# Generated by FakeRAM 2.0
VERSION 5.7 ;
BUSBITCHARS "[]" ;
PROPERTYDEFINITIONS
  MACRO width INTEGER ;
  MACRO depth INTEGER ;
  MACRO banks INTEGER ;
END PROPERTYDEFINITIONS
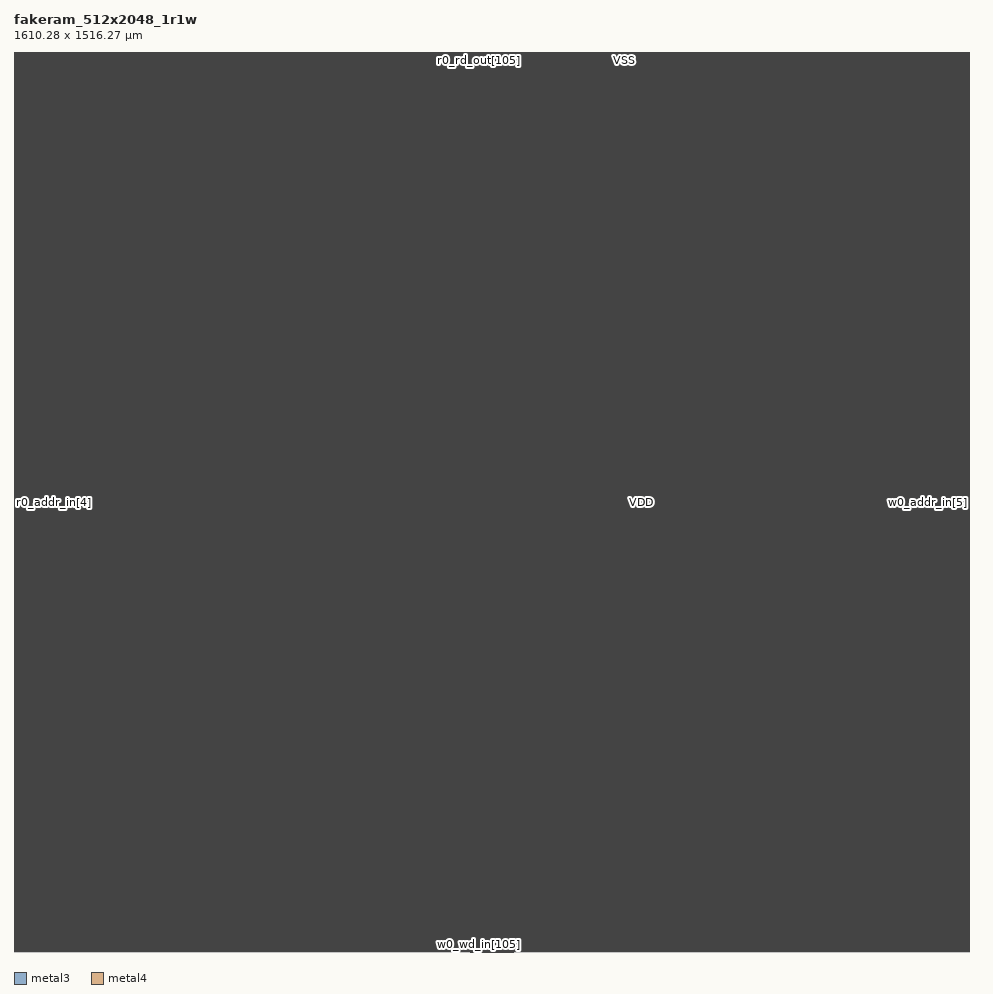
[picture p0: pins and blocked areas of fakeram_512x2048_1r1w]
MACRO fakeram_512x2048_1r1w
  PROPERTY width 512 ;
  PROPERTY depth 2048 ;
  PROPERTY banks 1 ;
  FOREIGN fakeram_512x2048_1r1w 0 0 ;
  SYMMETRY X Y R90 ;
  SIZE 1610.280 BY 1516.270 ;
  CLASS BLOCK ;
  PIN r0_addr_in[0]
    DIRECTION INPUT ;
    USE SIGNAL ;
    SHAPE ABUTMENT ;
    PORT
      LAYER metal3 ;
      RECT 0.000 757.260 0.070 757.330 ;
    END
  END r0_addr_in[0]
  PIN r0_addr_in[1]
    DIRECTION INPUT ;
    USE SIGNAL ;
    SHAPE ABUTMENT ;
    PORT
      LAYER metal3 ;
      RECT 0.000 757.400 0.070 757.470 ;
    END
  END r0_addr_in[1]
  PIN r0_addr_in[2]
    DIRECTION INPUT ;
    USE SIGNAL ;
    SHAPE ABUTMENT ;
    PORT
      LAYER metal3 ;
      RECT 0.000 757.540 0.070 757.610 ;
    END
  END r0_addr_in[2]
  PIN r0_addr_in[3]
    DIRECTION INPUT ;
    USE SIGNAL ;
    SHAPE ABUTMENT ;
    PORT
      LAYER metal3 ;
      RECT 0.000 757.680 0.070 757.750 ;
    END
  END r0_addr_in[3]
  PIN r0_addr_in[4]
    DIRECTION INPUT ;
    USE SIGNAL ;
    SHAPE ABUTMENT ;
    PORT
      LAYER metal3 ;
      RECT 0.000 757.820 0.070 757.890 ;
    END
  END r0_addr_in[4]
  PIN r0_addr_in[5]
    DIRECTION INPUT ;
    USE SIGNAL ;
    SHAPE ABUTMENT ;
    PORT
      LAYER metal3 ;
      RECT 0.000 757.960 0.070 758.030 ;
    END
  END r0_addr_in[5]
  PIN r0_addr_in[6]
    DIRECTION INPUT ;
    USE SIGNAL ;
    SHAPE ABUTMENT ;
    PORT
      LAYER metal3 ;
      RECT 0.000 758.100 0.070 758.170 ;
    END
  END r0_addr_in[6]
  PIN r0_addr_in[7]
    DIRECTION INPUT ;
    USE SIGNAL ;
    SHAPE ABUTMENT ;
    PORT
      LAYER metal3 ;
      RECT 0.000 758.240 0.070 758.310 ;
    END
  END r0_addr_in[7]
  PIN r0_addr_in[8]
    DIRECTION INPUT ;
    USE SIGNAL ;
    SHAPE ABUTMENT ;
    PORT
      LAYER metal3 ;
      RECT 0.000 758.380 0.070 758.450 ;
    END
  END r0_addr_in[8]
  PIN r0_addr_in[9]
    DIRECTION INPUT ;
    USE SIGNAL ;
    SHAPE ABUTMENT ;
    PORT
      LAYER metal3 ;
      RECT 0.000 758.520 0.070 758.590 ;
    END
  END r0_addr_in[9]
  PIN r0_addr_in[10]
    DIRECTION INPUT ;
    USE SIGNAL ;
    SHAPE ABUTMENT ;
    PORT
      LAYER metal3 ;
      RECT 0.000 758.660 0.070 758.730 ;
    END
  END r0_addr_in[10]
  PIN r0_ce_in
    DIRECTION INPUT ;
    USE SIGNAL ;
    SHAPE ABUTMENT ;
    PORT
      LAYER metal3 ;
      RECT 0.000 758.940 0.070 759.010 ;
    END
  END r0_ce_in
  PIN r0_clk
    DIRECTION INPUT ;
    USE SIGNAL ;
    SHAPE ABUTMENT ;
    PORT
      LAYER metal3 ;
      RECT 0.000 759.080 0.070 759.150 ;
    END
  END r0_clk
  PIN r0_rd_out[0]
    DIRECTION OUTPUT ;
    USE SIGNAL ;
    SHAPE ABUTMENT ;
    PORT
      LAYER metal3 ;
      RECT 769.125 1516.200 769.195 1516.270 ;
    END
  END r0_rd_out[0]
  PIN r0_rd_out[1]
    DIRECTION OUTPUT ;
    USE SIGNAL ;
    SHAPE ABUTMENT ;
    PORT
      LAYER metal3 ;
      RECT 769.265 1516.200 769.335 1516.270 ;
    END
  END r0_rd_out[1]
  PIN r0_rd_out[2]
    DIRECTION OUTPUT ;
    USE SIGNAL ;
    SHAPE ABUTMENT ;
    PORT
      LAYER metal3 ;
      RECT 769.405 1516.200 769.475 1516.270 ;
    END
  END r0_rd_out[2]
  PIN r0_rd_out[3]
    DIRECTION OUTPUT ;
    USE SIGNAL ;
    SHAPE ABUTMENT ;
    PORT
      LAYER metal3 ;
      RECT 769.545 1516.200 769.615 1516.270 ;
    END
  END r0_rd_out[3]
  PIN r0_rd_out[4]
    DIRECTION OUTPUT ;
    USE SIGNAL ;
    SHAPE ABUTMENT ;
    PORT
      LAYER metal3 ;
      RECT 769.685 1516.200 769.755 1516.270 ;
    END
  END r0_rd_out[4]
  PIN r0_rd_out[5]
    DIRECTION OUTPUT ;
    USE SIGNAL ;
    SHAPE ABUTMENT ;
    PORT
      LAYER metal3 ;
      RECT 769.825 1516.200 769.895 1516.270 ;
    END
  END r0_rd_out[5]
  PIN r0_rd_out[6]
    DIRECTION OUTPUT ;
    USE SIGNAL ;
    SHAPE ABUTMENT ;
    PORT
      LAYER metal3 ;
      RECT 769.965 1516.200 770.035 1516.270 ;
    END
  END r0_rd_out[6]
  PIN r0_rd_out[7]
    DIRECTION OUTPUT ;
    USE SIGNAL ;
    SHAPE ABUTMENT ;
    PORT
      LAYER metal3 ;
      RECT 770.105 1516.200 770.175 1516.270 ;
    END
  END r0_rd_out[7]
  PIN r0_rd_out[8]
    DIRECTION OUTPUT ;
    USE SIGNAL ;
    SHAPE ABUTMENT ;
    PORT
      LAYER metal3 ;
      RECT 770.245 1516.200 770.315 1516.270 ;
    END
  END r0_rd_out[8]
  PIN r0_rd_out[9]
    DIRECTION OUTPUT ;
    USE SIGNAL ;
    SHAPE ABUTMENT ;
    PORT
      LAYER metal3 ;
      RECT 770.385 1516.200 770.455 1516.270 ;
    END
  END r0_rd_out[9]
  PIN r0_rd_out[10]
    DIRECTION OUTPUT ;
    USE SIGNAL ;
    SHAPE ABUTMENT ;
    PORT
      LAYER metal3 ;
      RECT 770.525 1516.200 770.595 1516.270 ;
    END
  END r0_rd_out[10]
  PIN r0_rd_out[11]
    DIRECTION OUTPUT ;
    USE SIGNAL ;
    SHAPE ABUTMENT ;
    PORT
      LAYER metal3 ;
      RECT 770.665 1516.200 770.735 1516.270 ;
    END
  END r0_rd_out[11]
  PIN r0_rd_out[12]
    DIRECTION OUTPUT ;
    USE SIGNAL ;
    SHAPE ABUTMENT ;
    PORT
      LAYER metal3 ;
      RECT 770.805 1516.200 770.875 1516.270 ;
    END
  END r0_rd_out[12]
  PIN r0_rd_out[13]
    DIRECTION OUTPUT ;
    USE SIGNAL ;
    SHAPE ABUTMENT ;
    PORT
      LAYER metal3 ;
      RECT 770.945 1516.200 771.015 1516.270 ;
    END
  END r0_rd_out[13]
  PIN r0_rd_out[14]
    DIRECTION OUTPUT ;
    USE SIGNAL ;
    SHAPE ABUTMENT ;
    PORT
      LAYER metal3 ;
      RECT 771.085 1516.200 771.155 1516.270 ;
    END
  END r0_rd_out[14]
  PIN r0_rd_out[15]
    DIRECTION OUTPUT ;
    USE SIGNAL ;
    SHAPE ABUTMENT ;
    PORT
      LAYER metal3 ;
      RECT 771.225 1516.200 771.295 1516.270 ;
    END
  END r0_rd_out[15]
  PIN r0_rd_out[16]
    DIRECTION OUTPUT ;
    USE SIGNAL ;
    SHAPE ABUTMENT ;
    PORT
      LAYER metal3 ;
      RECT 771.365 1516.200 771.435 1516.270 ;
    END
  END r0_rd_out[16]
  PIN r0_rd_out[17]
    DIRECTION OUTPUT ;
    USE SIGNAL ;
    SHAPE ABUTMENT ;
    PORT
      LAYER metal3 ;
      RECT 771.505 1516.200 771.575 1516.270 ;
    END
  END r0_rd_out[17]
  PIN r0_rd_out[18]
    DIRECTION OUTPUT ;
    USE SIGNAL ;
    SHAPE ABUTMENT ;
    PORT
      LAYER metal3 ;
      RECT 771.645 1516.200 771.715 1516.270 ;
    END
  END r0_rd_out[18]
  PIN r0_rd_out[19]
    DIRECTION OUTPUT ;
    USE SIGNAL ;
    SHAPE ABUTMENT ;
    PORT
      LAYER metal3 ;
      RECT 771.785 1516.200 771.855 1516.270 ;
    END
  END r0_rd_out[19]
  PIN r0_rd_out[20]
    DIRECTION OUTPUT ;
    USE SIGNAL ;
    SHAPE ABUTMENT ;
    PORT
      LAYER metal3 ;
      RECT 771.925 1516.200 771.995 1516.270 ;
    END
  END r0_rd_out[20]
  PIN r0_rd_out[21]
    DIRECTION OUTPUT ;
    USE SIGNAL ;
    SHAPE ABUTMENT ;
    PORT
      LAYER metal3 ;
      RECT 772.065 1516.200 772.135 1516.270 ;
    END
  END r0_rd_out[21]
  PIN r0_rd_out[22]
    DIRECTION OUTPUT ;
    USE SIGNAL ;
    SHAPE ABUTMENT ;
    PORT
      LAYER metal3 ;
      RECT 772.205 1516.200 772.275 1516.270 ;
    END
  END r0_rd_out[22]
  PIN r0_rd_out[23]
    DIRECTION OUTPUT ;
    USE SIGNAL ;
    SHAPE ABUTMENT ;
    PORT
      LAYER metal3 ;
      RECT 772.345 1516.200 772.415 1516.270 ;
    END
  END r0_rd_out[23]
  PIN r0_rd_out[24]
    DIRECTION OUTPUT ;
    USE SIGNAL ;
    SHAPE ABUTMENT ;
    PORT
      LAYER metal3 ;
      RECT 772.485 1516.200 772.555 1516.270 ;
    END
  END r0_rd_out[24]
  PIN r0_rd_out[25]
    DIRECTION OUTPUT ;
    USE SIGNAL ;
    SHAPE ABUTMENT ;
    PORT
      LAYER metal3 ;
      RECT 772.625 1516.200 772.695 1516.270 ;
    END
  END r0_rd_out[25]
  PIN r0_rd_out[26]
    DIRECTION OUTPUT ;
    USE SIGNAL ;
    SHAPE ABUTMENT ;
    PORT
      LAYER metal3 ;
      RECT 772.765 1516.200 772.835 1516.270 ;
    END
  END r0_rd_out[26]
  PIN r0_rd_out[27]
    DIRECTION OUTPUT ;
    USE SIGNAL ;
    SHAPE ABUTMENT ;
    PORT
      LAYER metal3 ;
      RECT 772.905 1516.200 772.975 1516.270 ;
    END
  END r0_rd_out[27]
  PIN r0_rd_out[28]
    DIRECTION OUTPUT ;
    USE SIGNAL ;
    SHAPE ABUTMENT ;
    PORT
      LAYER metal3 ;
      RECT 773.045 1516.200 773.115 1516.270 ;
    END
  END r0_rd_out[28]
  PIN r0_rd_out[29]
    DIRECTION OUTPUT ;
    USE SIGNAL ;
    SHAPE ABUTMENT ;
    PORT
      LAYER metal3 ;
      RECT 773.185 1516.200 773.255 1516.270 ;
    END
  END r0_rd_out[29]
  PIN r0_rd_out[30]
    DIRECTION OUTPUT ;
    USE SIGNAL ;
    SHAPE ABUTMENT ;
    PORT
      LAYER metal3 ;
      RECT 773.325 1516.200 773.395 1516.270 ;
    END
  END r0_rd_out[30]
  PIN r0_rd_out[31]
    DIRECTION OUTPUT ;
    USE SIGNAL ;
    SHAPE ABUTMENT ;
    PORT
      LAYER metal3 ;
      RECT 773.465 1516.200 773.535 1516.270 ;
    END
  END r0_rd_out[31]
  PIN r0_rd_out[32]
    DIRECTION OUTPUT ;
    USE SIGNAL ;
    SHAPE ABUTMENT ;
    PORT
      LAYER metal3 ;
      RECT 773.605 1516.200 773.675 1516.270 ;
    END
  END r0_rd_out[32]
  PIN r0_rd_out[33]
    DIRECTION OUTPUT ;
    USE SIGNAL ;
    SHAPE ABUTMENT ;
    PORT
      LAYER metal3 ;
      RECT 773.745 1516.200 773.815 1516.270 ;
    END
  END r0_rd_out[33]
  PIN r0_rd_out[34]
    DIRECTION OUTPUT ;
    USE SIGNAL ;
    SHAPE ABUTMENT ;
    PORT
      LAYER metal3 ;
      RECT 773.885 1516.200 773.955 1516.270 ;
    END
  END r0_rd_out[34]
  PIN r0_rd_out[35]
    DIRECTION OUTPUT ;
    USE SIGNAL ;
    SHAPE ABUTMENT ;
    PORT
      LAYER metal3 ;
      RECT 774.025 1516.200 774.095 1516.270 ;
    END
  END r0_rd_out[35]
  PIN r0_rd_out[36]
    DIRECTION OUTPUT ;
    USE SIGNAL ;
    SHAPE ABUTMENT ;
    PORT
      LAYER metal3 ;
      RECT 774.165 1516.200 774.235 1516.270 ;
    END
  END r0_rd_out[36]
  PIN r0_rd_out[37]
    DIRECTION OUTPUT ;
    USE SIGNAL ;
    SHAPE ABUTMENT ;
    PORT
      LAYER metal3 ;
      RECT 774.305 1516.200 774.375 1516.270 ;
    END
  END r0_rd_out[37]
  PIN r0_rd_out[38]
    DIRECTION OUTPUT ;
    USE SIGNAL ;
    SHAPE ABUTMENT ;
    PORT
      LAYER metal3 ;
      RECT 774.445 1516.200 774.515 1516.270 ;
    END
  END r0_rd_out[38]
  PIN r0_rd_out[39]
    DIRECTION OUTPUT ;
    USE SIGNAL ;
    SHAPE ABUTMENT ;
    PORT
      LAYER metal3 ;
      RECT 774.585 1516.200 774.655 1516.270 ;
    END
  END r0_rd_out[39]
  PIN r0_rd_out[40]
    DIRECTION OUTPUT ;
    USE SIGNAL ;
    SHAPE ABUTMENT ;
    PORT
      LAYER metal3 ;
      RECT 774.725 1516.200 774.795 1516.270 ;
    END
  END r0_rd_out[40]
  PIN r0_rd_out[41]
    DIRECTION OUTPUT ;
    USE SIGNAL ;
    SHAPE ABUTMENT ;
    PORT
      LAYER metal3 ;
      RECT 774.865 1516.200 774.935 1516.270 ;
    END
  END r0_rd_out[41]
  PIN r0_rd_out[42]
    DIRECTION OUTPUT ;
    USE SIGNAL ;
    SHAPE ABUTMENT ;
    PORT
      LAYER metal3 ;
      RECT 775.005 1516.200 775.075 1516.270 ;
    END
  END r0_rd_out[42]
  PIN r0_rd_out[43]
    DIRECTION OUTPUT ;
    USE SIGNAL ;
    SHAPE ABUTMENT ;
    PORT
      LAYER metal3 ;
      RECT 775.145 1516.200 775.215 1516.270 ;
    END
  END r0_rd_out[43]
  PIN r0_rd_out[44]
    DIRECTION OUTPUT ;
    USE SIGNAL ;
    SHAPE ABUTMENT ;
    PORT
      LAYER metal3 ;
      RECT 775.285 1516.200 775.355 1516.270 ;
    END
  END r0_rd_out[44]
  PIN r0_rd_out[45]
    DIRECTION OUTPUT ;
    USE SIGNAL ;
    SHAPE ABUTMENT ;
    PORT
      LAYER metal3 ;
      RECT 775.425 1516.200 775.495 1516.270 ;
    END
  END r0_rd_out[45]
  PIN r0_rd_out[46]
    DIRECTION OUTPUT ;
    USE SIGNAL ;
    SHAPE ABUTMENT ;
    PORT
      LAYER metal3 ;
      RECT 775.565 1516.200 775.635 1516.270 ;
    END
  END r0_rd_out[46]
  PIN r0_rd_out[47]
    DIRECTION OUTPUT ;
    USE SIGNAL ;
    SHAPE ABUTMENT ;
    PORT
      LAYER metal3 ;
      RECT 775.705 1516.200 775.775 1516.270 ;
    END
  END r0_rd_out[47]
  PIN r0_rd_out[48]
    DIRECTION OUTPUT ;
    USE SIGNAL ;
    SHAPE ABUTMENT ;
    PORT
      LAYER metal3 ;
      RECT 775.845 1516.200 775.915 1516.270 ;
    END
  END r0_rd_out[48]
  PIN r0_rd_out[49]
    DIRECTION OUTPUT ;
    USE SIGNAL ;
    SHAPE ABUTMENT ;
    PORT
      LAYER metal3 ;
      RECT 775.985 1516.200 776.055 1516.270 ;
    END
  END r0_rd_out[49]
  PIN r0_rd_out[50]
    DIRECTION OUTPUT ;
    USE SIGNAL ;
    SHAPE ABUTMENT ;
    PORT
      LAYER metal3 ;
      RECT 776.125 1516.200 776.195 1516.270 ;
    END
  END r0_rd_out[50]
  PIN r0_rd_out[51]
    DIRECTION OUTPUT ;
    USE SIGNAL ;
    SHAPE ABUTMENT ;
    PORT
      LAYER metal3 ;
      RECT 776.265 1516.200 776.335 1516.270 ;
    END
  END r0_rd_out[51]
  PIN r0_rd_out[52]
    DIRECTION OUTPUT ;
    USE SIGNAL ;
    SHAPE ABUTMENT ;
    PORT
      LAYER metal3 ;
      RECT 776.405 1516.200 776.475 1516.270 ;
    END
  END r0_rd_out[52]
  PIN r0_rd_out[53]
    DIRECTION OUTPUT ;
    USE SIGNAL ;
    SHAPE ABUTMENT ;
    PORT
      LAYER metal3 ;
      RECT 776.545 1516.200 776.615 1516.270 ;
    END
  END r0_rd_out[53]
  PIN r0_rd_out[54]
    DIRECTION OUTPUT ;
    USE SIGNAL ;
    SHAPE ABUTMENT ;
    PORT
      LAYER metal3 ;
      RECT 776.685 1516.200 776.755 1516.270 ;
    END
  END r0_rd_out[54]
  PIN r0_rd_out[55]
    DIRECTION OUTPUT ;
    USE SIGNAL ;
    SHAPE ABUTMENT ;
    PORT
      LAYER metal3 ;
      RECT 776.825 1516.200 776.895 1516.270 ;
    END
  END r0_rd_out[55]
  PIN r0_rd_out[56]
    DIRECTION OUTPUT ;
    USE SIGNAL ;
    SHAPE ABUTMENT ;
    PORT
      LAYER metal3 ;
      RECT 776.965 1516.200 777.035 1516.270 ;
    END
  END r0_rd_out[56]
  PIN r0_rd_out[57]
    DIRECTION OUTPUT ;
    USE SIGNAL ;
    SHAPE ABUTMENT ;
    PORT
      LAYER metal3 ;
      RECT 777.105 1516.200 777.175 1516.270 ;
    END
  END r0_rd_out[57]
  PIN r0_rd_out[58]
    DIRECTION OUTPUT ;
    USE SIGNAL ;
    SHAPE ABUTMENT ;
    PORT
      LAYER metal3 ;
      RECT 777.245 1516.200 777.315 1516.270 ;
    END
  END r0_rd_out[58]
  PIN r0_rd_out[59]
    DIRECTION OUTPUT ;
    USE SIGNAL ;
    SHAPE ABUTMENT ;
    PORT
      LAYER metal3 ;
      RECT 777.385 1516.200 777.455 1516.270 ;
    END
  END r0_rd_out[59]
  PIN r0_rd_out[60]
    DIRECTION OUTPUT ;
    USE SIGNAL ;
    SHAPE ABUTMENT ;
    PORT
      LAYER metal3 ;
      RECT 777.525 1516.200 777.595 1516.270 ;
    END
  END r0_rd_out[60]
  PIN r0_rd_out[61]
    DIRECTION OUTPUT ;
    USE SIGNAL ;
    SHAPE ABUTMENT ;
    PORT
      LAYER metal3 ;
      RECT 777.665 1516.200 777.735 1516.270 ;
    END
  END r0_rd_out[61]
  PIN r0_rd_out[62]
    DIRECTION OUTPUT ;
    USE SIGNAL ;
    SHAPE ABUTMENT ;
    PORT
      LAYER metal3 ;
      RECT 777.805 1516.200 777.875 1516.270 ;
    END
  END r0_rd_out[62]
  PIN r0_rd_out[63]
    DIRECTION OUTPUT ;
    USE SIGNAL ;
    SHAPE ABUTMENT ;
    PORT
      LAYER metal3 ;
      RECT 777.945 1516.200 778.015 1516.270 ;
    END
  END r0_rd_out[63]
  PIN r0_rd_out[64]
    DIRECTION OUTPUT ;
    USE SIGNAL ;
    SHAPE ABUTMENT ;
    PORT
      LAYER metal3 ;
      RECT 778.085 1516.200 778.155 1516.270 ;
    END
  END r0_rd_out[64]
  PIN r0_rd_out[65]
    DIRECTION OUTPUT ;
    USE SIGNAL ;
    SHAPE ABUTMENT ;
    PORT
      LAYER metal3 ;
      RECT 778.225 1516.200 778.295 1516.270 ;
    END
  END r0_rd_out[65]
  PIN r0_rd_out[66]
    DIRECTION OUTPUT ;
    USE SIGNAL ;
    SHAPE ABUTMENT ;
    PORT
      LAYER metal3 ;
      RECT 778.365 1516.200 778.435 1516.270 ;
    END
  END r0_rd_out[66]
  PIN r0_rd_out[67]
    DIRECTION OUTPUT ;
    USE SIGNAL ;
    SHAPE ABUTMENT ;
    PORT
      LAYER metal3 ;
      RECT 778.505 1516.200 778.575 1516.270 ;
    END
  END r0_rd_out[67]
  PIN r0_rd_out[68]
    DIRECTION OUTPUT ;
    USE SIGNAL ;
    SHAPE ABUTMENT ;
    PORT
      LAYER metal3 ;
      RECT 778.645 1516.200 778.715 1516.270 ;
    END
  END r0_rd_out[68]
  PIN r0_rd_out[69]
    DIRECTION OUTPUT ;
    USE SIGNAL ;
    SHAPE ABUTMENT ;
    PORT
      LAYER metal3 ;
      RECT 778.785 1516.200 778.855 1516.270 ;
    END
  END r0_rd_out[69]
  PIN r0_rd_out[70]
    DIRECTION OUTPUT ;
    USE SIGNAL ;
    SHAPE ABUTMENT ;
    PORT
      LAYER metal3 ;
      RECT 778.925 1516.200 778.995 1516.270 ;
    END
  END r0_rd_out[70]
  PIN r0_rd_out[71]
    DIRECTION OUTPUT ;
    USE SIGNAL ;
    SHAPE ABUTMENT ;
    PORT
      LAYER metal3 ;
      RECT 779.065 1516.200 779.135 1516.270 ;
    END
  END r0_rd_out[71]
  PIN r0_rd_out[72]
    DIRECTION OUTPUT ;
    USE SIGNAL ;
    SHAPE ABUTMENT ;
    PORT
      LAYER metal3 ;
      RECT 779.205 1516.200 779.275 1516.270 ;
    END
  END r0_rd_out[72]
  PIN r0_rd_out[73]
    DIRECTION OUTPUT ;
    USE SIGNAL ;
    SHAPE ABUTMENT ;
    PORT
      LAYER metal3 ;
      RECT 779.345 1516.200 779.415 1516.270 ;
    END
  END r0_rd_out[73]
  PIN r0_rd_out[74]
    DIRECTION OUTPUT ;
    USE SIGNAL ;
    SHAPE ABUTMENT ;
    PORT
      LAYER metal3 ;
      RECT 779.485 1516.200 779.555 1516.270 ;
    END
  END r0_rd_out[74]
  PIN r0_rd_out[75]
    DIRECTION OUTPUT ;
    USE SIGNAL ;
    SHAPE ABUTMENT ;
    PORT
      LAYER metal3 ;
      RECT 779.625 1516.200 779.695 1516.270 ;
    END
  END r0_rd_out[75]
  PIN r0_rd_out[76]
    DIRECTION OUTPUT ;
    USE SIGNAL ;
    SHAPE ABUTMENT ;
    PORT
      LAYER metal3 ;
      RECT 779.765 1516.200 779.835 1516.270 ;
    END
  END r0_rd_out[76]
  PIN r0_rd_out[77]
    DIRECTION OUTPUT ;
    USE SIGNAL ;
    SHAPE ABUTMENT ;
    PORT
      LAYER metal3 ;
      RECT 779.905 1516.200 779.975 1516.270 ;
    END
  END r0_rd_out[77]
  PIN r0_rd_out[78]
    DIRECTION OUTPUT ;
    USE SIGNAL ;
    SHAPE ABUTMENT ;
    PORT
      LAYER metal3 ;
      RECT 780.045 1516.200 780.115 1516.270 ;
    END
  END r0_rd_out[78]
  PIN r0_rd_out[79]
    DIRECTION OUTPUT ;
    USE SIGNAL ;
    SHAPE ABUTMENT ;
    PORT
      LAYER metal3 ;
      RECT 780.185 1516.200 780.255 1516.270 ;
    END
  END r0_rd_out[79]
  PIN r0_rd_out[80]
    DIRECTION OUTPUT ;
    USE SIGNAL ;
    SHAPE ABUTMENT ;
    PORT
      LAYER metal3 ;
      RECT 780.325 1516.200 780.395 1516.270 ;
    END
  END r0_rd_out[80]
  PIN r0_rd_out[81]
    DIRECTION OUTPUT ;
    USE SIGNAL ;
    SHAPE ABUTMENT ;
    PORT
      LAYER metal3 ;
      RECT 780.465 1516.200 780.535 1516.270 ;
    END
  END r0_rd_out[81]
  PIN r0_rd_out[82]
    DIRECTION OUTPUT ;
    USE SIGNAL ;
    SHAPE ABUTMENT ;
    PORT
      LAYER metal3 ;
      RECT 780.605 1516.200 780.675 1516.270 ;
    END
  END r0_rd_out[82]
  PIN r0_rd_out[83]
    DIRECTION OUTPUT ;
    USE SIGNAL ;
    SHAPE ABUTMENT ;
    PORT
      LAYER metal3 ;
      RECT 780.745 1516.200 780.815 1516.270 ;
    END
  END r0_rd_out[83]
  PIN r0_rd_out[84]
    DIRECTION OUTPUT ;
    USE SIGNAL ;
    SHAPE ABUTMENT ;
    PORT
      LAYER metal3 ;
      RECT 780.885 1516.200 780.955 1516.270 ;
    END
  END r0_rd_out[84]
  PIN r0_rd_out[85]
    DIRECTION OUTPUT ;
    USE SIGNAL ;
    SHAPE ABUTMENT ;
    PORT
      LAYER metal3 ;
      RECT 781.025 1516.200 781.095 1516.270 ;
    END
  END r0_rd_out[85]
  PIN r0_rd_out[86]
    DIRECTION OUTPUT ;
    USE SIGNAL ;
    SHAPE ABUTMENT ;
    PORT
      LAYER metal3 ;
      RECT 781.165 1516.200 781.235 1516.270 ;
    END
  END r0_rd_out[86]
  PIN r0_rd_out[87]
    DIRECTION OUTPUT ;
    USE SIGNAL ;
    SHAPE ABUTMENT ;
    PORT
      LAYER metal3 ;
      RECT 781.305 1516.200 781.375 1516.270 ;
    END
  END r0_rd_out[87]
  PIN r0_rd_out[88]
    DIRECTION OUTPUT ;
    USE SIGNAL ;
    SHAPE ABUTMENT ;
    PORT
      LAYER metal3 ;
      RECT 781.445 1516.200 781.515 1516.270 ;
    END
  END r0_rd_out[88]
  PIN r0_rd_out[89]
    DIRECTION OUTPUT ;
    USE SIGNAL ;
    SHAPE ABUTMENT ;
    PORT
      LAYER metal3 ;
      RECT 781.585 1516.200 781.655 1516.270 ;
    END
  END r0_rd_out[89]
  PIN r0_rd_out[90]
    DIRECTION OUTPUT ;
    USE SIGNAL ;
    SHAPE ABUTMENT ;
    PORT
      LAYER metal3 ;
      RECT 781.725 1516.200 781.795 1516.270 ;
    END
  END r0_rd_out[90]
  PIN r0_rd_out[91]
    DIRECTION OUTPUT ;
    USE SIGNAL ;
    SHAPE ABUTMENT ;
    PORT
      LAYER metal3 ;
      RECT 781.865 1516.200 781.935 1516.270 ;
    END
  END r0_rd_out[91]
  PIN r0_rd_out[92]
    DIRECTION OUTPUT ;
    USE SIGNAL ;
    SHAPE ABUTMENT ;
    PORT
      LAYER metal3 ;
      RECT 782.005 1516.200 782.075 1516.270 ;
    END
  END r0_rd_out[92]
  PIN r0_rd_out[93]
    DIRECTION OUTPUT ;
    USE SIGNAL ;
    SHAPE ABUTMENT ;
    PORT
      LAYER metal3 ;
      RECT 782.145 1516.200 782.215 1516.270 ;
    END
  END r0_rd_out[93]
  PIN r0_rd_out[94]
    DIRECTION OUTPUT ;
    USE SIGNAL ;
    SHAPE ABUTMENT ;
    PORT
      LAYER metal3 ;
      RECT 782.285 1516.200 782.355 1516.270 ;
    END
  END r0_rd_out[94]
  PIN r0_rd_out[95]
    DIRECTION OUTPUT ;
    USE SIGNAL ;
    SHAPE ABUTMENT ;
    PORT
      LAYER metal3 ;
      RECT 782.425 1516.200 782.495 1516.270 ;
    END
  END r0_rd_out[95]
  PIN r0_rd_out[96]
    DIRECTION OUTPUT ;
    USE SIGNAL ;
    SHAPE ABUTMENT ;
    PORT
      LAYER metal3 ;
      RECT 782.565 1516.200 782.635 1516.270 ;
    END
  END r0_rd_out[96]
  PIN r0_rd_out[97]
    DIRECTION OUTPUT ;
    USE SIGNAL ;
    SHAPE ABUTMENT ;
    PORT
      LAYER metal3 ;
      RECT 782.705 1516.200 782.775 1516.270 ;
    END
  END r0_rd_out[97]
  PIN r0_rd_out[98]
    DIRECTION OUTPUT ;
    USE SIGNAL ;
    SHAPE ABUTMENT ;
    PORT
      LAYER metal3 ;
      RECT 782.845 1516.200 782.915 1516.270 ;
    END
  END r0_rd_out[98]
  PIN r0_rd_out[99]
    DIRECTION OUTPUT ;
    USE SIGNAL ;
    SHAPE ABUTMENT ;
    PORT
      LAYER metal3 ;
      RECT 782.985 1516.200 783.055 1516.270 ;
    END
  END r0_rd_out[99]
  PIN r0_rd_out[100]
    DIRECTION OUTPUT ;
    USE SIGNAL ;
    SHAPE ABUTMENT ;
    PORT
      LAYER metal3 ;
      RECT 783.125 1516.200 783.195 1516.270 ;
    END
  END r0_rd_out[100]
  PIN r0_rd_out[101]
    DIRECTION OUTPUT ;
    USE SIGNAL ;
    SHAPE ABUTMENT ;
    PORT
      LAYER metal3 ;
      RECT 783.265 1516.200 783.335 1516.270 ;
    END
  END r0_rd_out[101]
  PIN r0_rd_out[102]
    DIRECTION OUTPUT ;
    USE SIGNAL ;
    SHAPE ABUTMENT ;
    PORT
      LAYER metal3 ;
      RECT 783.405 1516.200 783.475 1516.270 ;
    END
  END r0_rd_out[102]
  PIN r0_rd_out[103]
    DIRECTION OUTPUT ;
    USE SIGNAL ;
    SHAPE ABUTMENT ;
    PORT
      LAYER metal3 ;
      RECT 783.545 1516.200 783.615 1516.270 ;
    END
  END r0_rd_out[103]
  PIN r0_rd_out[104]
    DIRECTION OUTPUT ;
    USE SIGNAL ;
    SHAPE ABUTMENT ;
    PORT
      LAYER metal3 ;
      RECT 783.685 1516.200 783.755 1516.270 ;
    END
  END r0_rd_out[104]
  PIN r0_rd_out[105]
    DIRECTION OUTPUT ;
    USE SIGNAL ;
    SHAPE ABUTMENT ;
    PORT
      LAYER metal3 ;
      RECT 783.825 1516.200 783.895 1516.270 ;
    END
  END r0_rd_out[105]
  PIN r0_rd_out[106]
    DIRECTION OUTPUT ;
    USE SIGNAL ;
    SHAPE ABUTMENT ;
    PORT
      LAYER metal3 ;
      RECT 783.965 1516.200 784.035 1516.270 ;
    END
  END r0_rd_out[106]
  PIN r0_rd_out[107]
    DIRECTION OUTPUT ;
    USE SIGNAL ;
    SHAPE ABUTMENT ;
    PORT
      LAYER metal3 ;
      RECT 784.105 1516.200 784.175 1516.270 ;
    END
  END r0_rd_out[107]
  PIN r0_rd_out[108]
    DIRECTION OUTPUT ;
    USE SIGNAL ;
    SHAPE ABUTMENT ;
    PORT
      LAYER metal3 ;
      RECT 784.245 1516.200 784.315 1516.270 ;
    END
  END r0_rd_out[108]
  PIN r0_rd_out[109]
    DIRECTION OUTPUT ;
    USE SIGNAL ;
    SHAPE ABUTMENT ;
    PORT
      LAYER metal3 ;
      RECT 784.385 1516.200 784.455 1516.270 ;
    END
  END r0_rd_out[109]
  PIN r0_rd_out[110]
    DIRECTION OUTPUT ;
    USE SIGNAL ;
    SHAPE ABUTMENT ;
    PORT
      LAYER metal3 ;
      RECT 784.525 1516.200 784.595 1516.270 ;
    END
  END r0_rd_out[110]
  PIN r0_rd_out[111]
    DIRECTION OUTPUT ;
    USE SIGNAL ;
    SHAPE ABUTMENT ;
    PORT
      LAYER metal3 ;
      RECT 784.665 1516.200 784.735 1516.270 ;
    END
  END r0_rd_out[111]
  PIN r0_rd_out[112]
    DIRECTION OUTPUT ;
    USE SIGNAL ;
    SHAPE ABUTMENT ;
    PORT
      LAYER metal3 ;
      RECT 784.805 1516.200 784.875 1516.270 ;
    END
  END r0_rd_out[112]
  PIN r0_rd_out[113]
    DIRECTION OUTPUT ;
    USE SIGNAL ;
    SHAPE ABUTMENT ;
    PORT
      LAYER metal3 ;
      RECT 784.945 1516.200 785.015 1516.270 ;
    END
  END r0_rd_out[113]
  PIN r0_rd_out[114]
    DIRECTION OUTPUT ;
    USE SIGNAL ;
    SHAPE ABUTMENT ;
    PORT
      LAYER metal3 ;
      RECT 785.085 1516.200 785.155 1516.270 ;
    END
  END r0_rd_out[114]
  PIN r0_rd_out[115]
    DIRECTION OUTPUT ;
    USE SIGNAL ;
    SHAPE ABUTMENT ;
    PORT
      LAYER metal3 ;
      RECT 785.225 1516.200 785.295 1516.270 ;
    END
  END r0_rd_out[115]
  PIN r0_rd_out[116]
    DIRECTION OUTPUT ;
    USE SIGNAL ;
    SHAPE ABUTMENT ;
    PORT
      LAYER metal3 ;
      RECT 785.365 1516.200 785.435 1516.270 ;
    END
  END r0_rd_out[116]
  PIN r0_rd_out[117]
    DIRECTION OUTPUT ;
    USE SIGNAL ;
    SHAPE ABUTMENT ;
    PORT
      LAYER metal3 ;
      RECT 785.505 1516.200 785.575 1516.270 ;
    END
  END r0_rd_out[117]
  PIN r0_rd_out[118]
    DIRECTION OUTPUT ;
    USE SIGNAL ;
    SHAPE ABUTMENT ;
    PORT
      LAYER metal3 ;
      RECT 785.645 1516.200 785.715 1516.270 ;
    END
  END r0_rd_out[118]
  PIN r0_rd_out[119]
    DIRECTION OUTPUT ;
    USE SIGNAL ;
    SHAPE ABUTMENT ;
    PORT
      LAYER metal3 ;
      RECT 785.785 1516.200 785.855 1516.270 ;
    END
  END r0_rd_out[119]
  PIN r0_rd_out[120]
    DIRECTION OUTPUT ;
    USE SIGNAL ;
    SHAPE ABUTMENT ;
    PORT
      LAYER metal3 ;
      RECT 785.925 1516.200 785.995 1516.270 ;
    END
  END r0_rd_out[120]
  PIN r0_rd_out[121]
    DIRECTION OUTPUT ;
    USE SIGNAL ;
    SHAPE ABUTMENT ;
    PORT
      LAYER metal3 ;
      RECT 786.065 1516.200 786.135 1516.270 ;
    END
  END r0_rd_out[121]
  PIN r0_rd_out[122]
    DIRECTION OUTPUT ;
    USE SIGNAL ;
    SHAPE ABUTMENT ;
    PORT
      LAYER metal3 ;
      RECT 786.205 1516.200 786.275 1516.270 ;
    END
  END r0_rd_out[122]
  PIN r0_rd_out[123]
    DIRECTION OUTPUT ;
    USE SIGNAL ;
    SHAPE ABUTMENT ;
    PORT
      LAYER metal3 ;
      RECT 786.345 1516.200 786.415 1516.270 ;
    END
  END r0_rd_out[123]
  PIN r0_rd_out[124]
    DIRECTION OUTPUT ;
    USE SIGNAL ;
    SHAPE ABUTMENT ;
    PORT
      LAYER metal3 ;
      RECT 786.485 1516.200 786.555 1516.270 ;
    END
  END r0_rd_out[124]
  PIN r0_rd_out[125]
    DIRECTION OUTPUT ;
    USE SIGNAL ;
    SHAPE ABUTMENT ;
    PORT
      LAYER metal3 ;
      RECT 786.625 1516.200 786.695 1516.270 ;
    END
  END r0_rd_out[125]
  PIN r0_rd_out[126]
    DIRECTION OUTPUT ;
    USE SIGNAL ;
    SHAPE ABUTMENT ;
    PORT
      LAYER metal3 ;
      RECT 786.765 1516.200 786.835 1516.270 ;
    END
  END r0_rd_out[126]
  PIN r0_rd_out[127]
    DIRECTION OUTPUT ;
    USE SIGNAL ;
    SHAPE ABUTMENT ;
    PORT
      LAYER metal3 ;
      RECT 786.905 1516.200 786.975 1516.270 ;
    END
  END r0_rd_out[127]
  PIN r0_rd_out[128]
    DIRECTION OUTPUT ;
    USE SIGNAL ;
    SHAPE ABUTMENT ;
    PORT
      LAYER metal3 ;
      RECT 787.045 1516.200 787.115 1516.270 ;
    END
  END r0_rd_out[128]
  PIN r0_rd_out[129]
    DIRECTION OUTPUT ;
    USE SIGNAL ;
    SHAPE ABUTMENT ;
    PORT
      LAYER metal3 ;
      RECT 787.185 1516.200 787.255 1516.270 ;
    END
  END r0_rd_out[129]
  PIN r0_rd_out[130]
    DIRECTION OUTPUT ;
    USE SIGNAL ;
    SHAPE ABUTMENT ;
    PORT
      LAYER metal3 ;
      RECT 787.325 1516.200 787.395 1516.270 ;
    END
  END r0_rd_out[130]
  PIN r0_rd_out[131]
    DIRECTION OUTPUT ;
    USE SIGNAL ;
    SHAPE ABUTMENT ;
    PORT
      LAYER metal3 ;
      RECT 787.465 1516.200 787.535 1516.270 ;
    END
  END r0_rd_out[131]
  PIN r0_rd_out[132]
    DIRECTION OUTPUT ;
    USE SIGNAL ;
    SHAPE ABUTMENT ;
    PORT
      LAYER metal3 ;
      RECT 787.605 1516.200 787.675 1516.270 ;
    END
  END r0_rd_out[132]
  PIN r0_rd_out[133]
    DIRECTION OUTPUT ;
    USE SIGNAL ;
    SHAPE ABUTMENT ;
    PORT
      LAYER metal3 ;
      RECT 787.745 1516.200 787.815 1516.270 ;
    END
  END r0_rd_out[133]
  PIN r0_rd_out[134]
    DIRECTION OUTPUT ;
    USE SIGNAL ;
    SHAPE ABUTMENT ;
    PORT
      LAYER metal3 ;
      RECT 787.885 1516.200 787.955 1516.270 ;
    END
  END r0_rd_out[134]
  PIN r0_rd_out[135]
    DIRECTION OUTPUT ;
    USE SIGNAL ;
    SHAPE ABUTMENT ;
    PORT
      LAYER metal3 ;
      RECT 788.025 1516.200 788.095 1516.270 ;
    END
  END r0_rd_out[135]
  PIN r0_rd_out[136]
    DIRECTION OUTPUT ;
    USE SIGNAL ;
    SHAPE ABUTMENT ;
    PORT
      LAYER metal3 ;
      RECT 788.165 1516.200 788.235 1516.270 ;
    END
  END r0_rd_out[136]
  PIN r0_rd_out[137]
    DIRECTION OUTPUT ;
    USE SIGNAL ;
    SHAPE ABUTMENT ;
    PORT
      LAYER metal3 ;
      RECT 788.305 1516.200 788.375 1516.270 ;
    END
  END r0_rd_out[137]
  PIN r0_rd_out[138]
    DIRECTION OUTPUT ;
    USE SIGNAL ;
    SHAPE ABUTMENT ;
    PORT
      LAYER metal3 ;
      RECT 788.445 1516.200 788.515 1516.270 ;
    END
  END r0_rd_out[138]
  PIN r0_rd_out[139]
    DIRECTION OUTPUT ;
    USE SIGNAL ;
    SHAPE ABUTMENT ;
    PORT
      LAYER metal3 ;
      RECT 788.585 1516.200 788.655 1516.270 ;
    END
  END r0_rd_out[139]
  PIN r0_rd_out[140]
    DIRECTION OUTPUT ;
    USE SIGNAL ;
    SHAPE ABUTMENT ;
    PORT
      LAYER metal3 ;
      RECT 788.725 1516.200 788.795 1516.270 ;
    END
  END r0_rd_out[140]
  PIN r0_rd_out[141]
    DIRECTION OUTPUT ;
    USE SIGNAL ;
    SHAPE ABUTMENT ;
    PORT
      LAYER metal3 ;
      RECT 788.865 1516.200 788.935 1516.270 ;
    END
  END r0_rd_out[141]
  PIN r0_rd_out[142]
    DIRECTION OUTPUT ;
    USE SIGNAL ;
    SHAPE ABUTMENT ;
    PORT
      LAYER metal3 ;
      RECT 789.005 1516.200 789.075 1516.270 ;
    END
  END r0_rd_out[142]
  PIN r0_rd_out[143]
    DIRECTION OUTPUT ;
    USE SIGNAL ;
    SHAPE ABUTMENT ;
    PORT
      LAYER metal3 ;
      RECT 789.145 1516.200 789.215 1516.270 ;
    END
  END r0_rd_out[143]
  PIN r0_rd_out[144]
    DIRECTION OUTPUT ;
    USE SIGNAL ;
    SHAPE ABUTMENT ;
    PORT
      LAYER metal3 ;
      RECT 789.285 1516.200 789.355 1516.270 ;
    END
  END r0_rd_out[144]
  PIN r0_rd_out[145]
    DIRECTION OUTPUT ;
    USE SIGNAL ;
    SHAPE ABUTMENT ;
    PORT
      LAYER metal3 ;
      RECT 789.425 1516.200 789.495 1516.270 ;
    END
  END r0_rd_out[145]
  PIN r0_rd_out[146]
    DIRECTION OUTPUT ;
    USE SIGNAL ;
    SHAPE ABUTMENT ;
    PORT
      LAYER metal3 ;
      RECT 789.565 1516.200 789.635 1516.270 ;
    END
  END r0_rd_out[146]
  PIN r0_rd_out[147]
    DIRECTION OUTPUT ;
    USE SIGNAL ;
    SHAPE ABUTMENT ;
    PORT
      LAYER metal3 ;
      RECT 789.705 1516.200 789.775 1516.270 ;
    END
  END r0_rd_out[147]
  PIN r0_rd_out[148]
    DIRECTION OUTPUT ;
    USE SIGNAL ;
    SHAPE ABUTMENT ;
    PORT
      LAYER metal3 ;
      RECT 789.845 1516.200 789.915 1516.270 ;
    END
  END r0_rd_out[148]
  PIN r0_rd_out[149]
    DIRECTION OUTPUT ;
    USE SIGNAL ;
    SHAPE ABUTMENT ;
    PORT
      LAYER metal3 ;
      RECT 789.985 1516.200 790.055 1516.270 ;
    END
  END r0_rd_out[149]
  PIN r0_rd_out[150]
    DIRECTION OUTPUT ;
    USE SIGNAL ;
    SHAPE ABUTMENT ;
    PORT
      LAYER metal3 ;
      RECT 790.125 1516.200 790.195 1516.270 ;
    END
  END r0_rd_out[150]
  PIN r0_rd_out[151]
    DIRECTION OUTPUT ;
    USE SIGNAL ;
    SHAPE ABUTMENT ;
    PORT
      LAYER metal3 ;
      RECT 790.265 1516.200 790.335 1516.270 ;
    END
  END r0_rd_out[151]
  PIN r0_rd_out[152]
    DIRECTION OUTPUT ;
    USE SIGNAL ;
    SHAPE ABUTMENT ;
    PORT
      LAYER metal3 ;
      RECT 790.405 1516.200 790.475 1516.270 ;
    END
  END r0_rd_out[152]
  PIN r0_rd_out[153]
    DIRECTION OUTPUT ;
    USE SIGNAL ;
    SHAPE ABUTMENT ;
    PORT
      LAYER metal3 ;
      RECT 790.545 1516.200 790.615 1516.270 ;
    END
  END r0_rd_out[153]
  PIN r0_rd_out[154]
    DIRECTION OUTPUT ;
    USE SIGNAL ;
    SHAPE ABUTMENT ;
    PORT
      LAYER metal3 ;
      RECT 790.685 1516.200 790.755 1516.270 ;
    END
  END r0_rd_out[154]
  PIN r0_rd_out[155]
    DIRECTION OUTPUT ;
    USE SIGNAL ;
    SHAPE ABUTMENT ;
    PORT
      LAYER metal3 ;
      RECT 790.825 1516.200 790.895 1516.270 ;
    END
  END r0_rd_out[155]
  PIN r0_rd_out[156]
    DIRECTION OUTPUT ;
    USE SIGNAL ;
    SHAPE ABUTMENT ;
    PORT
      LAYER metal3 ;
      RECT 790.965 1516.200 791.035 1516.270 ;
    END
  END r0_rd_out[156]
  PIN r0_rd_out[157]
    DIRECTION OUTPUT ;
    USE SIGNAL ;
    SHAPE ABUTMENT ;
    PORT
      LAYER metal3 ;
      RECT 791.105 1516.200 791.175 1516.270 ;
    END
  END r0_rd_out[157]
  PIN r0_rd_out[158]
    DIRECTION OUTPUT ;
    USE SIGNAL ;
    SHAPE ABUTMENT ;
    PORT
      LAYER metal3 ;
      RECT 791.245 1516.200 791.315 1516.270 ;
    END
  END r0_rd_out[158]
  PIN r0_rd_out[159]
    DIRECTION OUTPUT ;
    USE SIGNAL ;
    SHAPE ABUTMENT ;
    PORT
      LAYER metal3 ;
      RECT 791.385 1516.200 791.455 1516.270 ;
    END
  END r0_rd_out[159]
  PIN r0_rd_out[160]
    DIRECTION OUTPUT ;
    USE SIGNAL ;
    SHAPE ABUTMENT ;
    PORT
      LAYER metal3 ;
      RECT 791.525 1516.200 791.595 1516.270 ;
    END
  END r0_rd_out[160]
  PIN r0_rd_out[161]
    DIRECTION OUTPUT ;
    USE SIGNAL ;
    SHAPE ABUTMENT ;
    PORT
      LAYER metal3 ;
      RECT 791.665 1516.200 791.735 1516.270 ;
    END
  END r0_rd_out[161]
  PIN r0_rd_out[162]
    DIRECTION OUTPUT ;
    USE SIGNAL ;
    SHAPE ABUTMENT ;
    PORT
      LAYER metal3 ;
      RECT 791.805 1516.200 791.875 1516.270 ;
    END
  END r0_rd_out[162]
  PIN r0_rd_out[163]
    DIRECTION OUTPUT ;
    USE SIGNAL ;
    SHAPE ABUTMENT ;
    PORT
      LAYER metal3 ;
      RECT 791.945 1516.200 792.015 1516.270 ;
    END
  END r0_rd_out[163]
  PIN r0_rd_out[164]
    DIRECTION OUTPUT ;
    USE SIGNAL ;
    SHAPE ABUTMENT ;
    PORT
      LAYER metal3 ;
      RECT 792.085 1516.200 792.155 1516.270 ;
    END
  END r0_rd_out[164]
  PIN r0_rd_out[165]
    DIRECTION OUTPUT ;
    USE SIGNAL ;
    SHAPE ABUTMENT ;
    PORT
      LAYER metal3 ;
      RECT 792.225 1516.200 792.295 1516.270 ;
    END
  END r0_rd_out[165]
  PIN r0_rd_out[166]
    DIRECTION OUTPUT ;
    USE SIGNAL ;
    SHAPE ABUTMENT ;
    PORT
      LAYER metal3 ;
      RECT 792.365 1516.200 792.435 1516.270 ;
    END
  END r0_rd_out[166]
  PIN r0_rd_out[167]
    DIRECTION OUTPUT ;
    USE SIGNAL ;
    SHAPE ABUTMENT ;
    PORT
      LAYER metal3 ;
      RECT 792.505 1516.200 792.575 1516.270 ;
    END
  END r0_rd_out[167]
  PIN r0_rd_out[168]
    DIRECTION OUTPUT ;
    USE SIGNAL ;
    SHAPE ABUTMENT ;
    PORT
      LAYER metal3 ;
      RECT 792.645 1516.200 792.715 1516.270 ;
    END
  END r0_rd_out[168]
  PIN r0_rd_out[169]
    DIRECTION OUTPUT ;
    USE SIGNAL ;
    SHAPE ABUTMENT ;
    PORT
      LAYER metal3 ;
      RECT 792.785 1516.200 792.855 1516.270 ;
    END
  END r0_rd_out[169]
  PIN r0_rd_out[170]
    DIRECTION OUTPUT ;
    USE SIGNAL ;
    SHAPE ABUTMENT ;
    PORT
      LAYER metal3 ;
      RECT 792.925 1516.200 792.995 1516.270 ;
    END
  END r0_rd_out[170]
  PIN r0_rd_out[171]
    DIRECTION OUTPUT ;
    USE SIGNAL ;
    SHAPE ABUTMENT ;
    PORT
      LAYER metal3 ;
      RECT 793.065 1516.200 793.135 1516.270 ;
    END
  END r0_rd_out[171]
  PIN r0_rd_out[172]
    DIRECTION OUTPUT ;
    USE SIGNAL ;
    SHAPE ABUTMENT ;
    PORT
      LAYER metal3 ;
      RECT 793.205 1516.200 793.275 1516.270 ;
    END
  END r0_rd_out[172]
  PIN r0_rd_out[173]
    DIRECTION OUTPUT ;
    USE SIGNAL ;
    SHAPE ABUTMENT ;
    PORT
      LAYER metal3 ;
      RECT 793.345 1516.200 793.415 1516.270 ;
    END
  END r0_rd_out[173]
  PIN r0_rd_out[174]
    DIRECTION OUTPUT ;
    USE SIGNAL ;
    SHAPE ABUTMENT ;
    PORT
      LAYER metal3 ;
      RECT 793.485 1516.200 793.555 1516.270 ;
    END
  END r0_rd_out[174]
  PIN r0_rd_out[175]
    DIRECTION OUTPUT ;
    USE SIGNAL ;
    SHAPE ABUTMENT ;
    PORT
      LAYER metal3 ;
      RECT 793.625 1516.200 793.695 1516.270 ;
    END
  END r0_rd_out[175]
  PIN r0_rd_out[176]
    DIRECTION OUTPUT ;
    USE SIGNAL ;
    SHAPE ABUTMENT ;
    PORT
      LAYER metal3 ;
      RECT 793.765 1516.200 793.835 1516.270 ;
    END
  END r0_rd_out[176]
  PIN r0_rd_out[177]
    DIRECTION OUTPUT ;
    USE SIGNAL ;
    SHAPE ABUTMENT ;
    PORT
      LAYER metal3 ;
      RECT 793.905 1516.200 793.975 1516.270 ;
    END
  END r0_rd_out[177]
  PIN r0_rd_out[178]
    DIRECTION OUTPUT ;
    USE SIGNAL ;
    SHAPE ABUTMENT ;
    PORT
      LAYER metal3 ;
      RECT 794.045 1516.200 794.115 1516.270 ;
    END
  END r0_rd_out[178]
  PIN r0_rd_out[179]
    DIRECTION OUTPUT ;
    USE SIGNAL ;
    SHAPE ABUTMENT ;
    PORT
      LAYER metal3 ;
      RECT 794.185 1516.200 794.255 1516.270 ;
    END
  END r0_rd_out[179]
  PIN r0_rd_out[180]
    DIRECTION OUTPUT ;
    USE SIGNAL ;
    SHAPE ABUTMENT ;
    PORT
      LAYER metal3 ;
      RECT 794.325 1516.200 794.395 1516.270 ;
    END
  END r0_rd_out[180]
  PIN r0_rd_out[181]
    DIRECTION OUTPUT ;
    USE SIGNAL ;
    SHAPE ABUTMENT ;
    PORT
      LAYER metal3 ;
      RECT 794.465 1516.200 794.535 1516.270 ;
    END
  END r0_rd_out[181]
  PIN r0_rd_out[182]
    DIRECTION OUTPUT ;
    USE SIGNAL ;
    SHAPE ABUTMENT ;
    PORT
      LAYER metal3 ;
      RECT 794.605 1516.200 794.675 1516.270 ;
    END
  END r0_rd_out[182]
  PIN r0_rd_out[183]
    DIRECTION OUTPUT ;
    USE SIGNAL ;
    SHAPE ABUTMENT ;
    PORT
      LAYER metal3 ;
      RECT 794.745 1516.200 794.815 1516.270 ;
    END
  END r0_rd_out[183]
  PIN r0_rd_out[184]
    DIRECTION OUTPUT ;
    USE SIGNAL ;
    SHAPE ABUTMENT ;
    PORT
      LAYER metal3 ;
      RECT 794.885 1516.200 794.955 1516.270 ;
    END
  END r0_rd_out[184]
  PIN r0_rd_out[185]
    DIRECTION OUTPUT ;
    USE SIGNAL ;
    SHAPE ABUTMENT ;
    PORT
      LAYER metal3 ;
      RECT 795.025 1516.200 795.095 1516.270 ;
    END
  END r0_rd_out[185]
  PIN r0_rd_out[186]
    DIRECTION OUTPUT ;
    USE SIGNAL ;
    SHAPE ABUTMENT ;
    PORT
      LAYER metal3 ;
      RECT 795.165 1516.200 795.235 1516.270 ;
    END
  END r0_rd_out[186]
  PIN r0_rd_out[187]
    DIRECTION OUTPUT ;
    USE SIGNAL ;
    SHAPE ABUTMENT ;
    PORT
      LAYER metal3 ;
      RECT 795.305 1516.200 795.375 1516.270 ;
    END
  END r0_rd_out[187]
  PIN r0_rd_out[188]
    DIRECTION OUTPUT ;
    USE SIGNAL ;
    SHAPE ABUTMENT ;
    PORT
      LAYER metal3 ;
      RECT 795.445 1516.200 795.515 1516.270 ;
    END
  END r0_rd_out[188]
  PIN r0_rd_out[189]
    DIRECTION OUTPUT ;
    USE SIGNAL ;
    SHAPE ABUTMENT ;
    PORT
      LAYER metal3 ;
      RECT 795.585 1516.200 795.655 1516.270 ;
    END
  END r0_rd_out[189]
  PIN r0_rd_out[190]
    DIRECTION OUTPUT ;
    USE SIGNAL ;
    SHAPE ABUTMENT ;
    PORT
      LAYER metal3 ;
      RECT 795.725 1516.200 795.795 1516.270 ;
    END
  END r0_rd_out[190]
  PIN r0_rd_out[191]
    DIRECTION OUTPUT ;
    USE SIGNAL ;
    SHAPE ABUTMENT ;
    PORT
      LAYER metal3 ;
      RECT 795.865 1516.200 795.935 1516.270 ;
    END
  END r0_rd_out[191]
  PIN r0_rd_out[192]
    DIRECTION OUTPUT ;
    USE SIGNAL ;
    SHAPE ABUTMENT ;
    PORT
      LAYER metal3 ;
      RECT 796.005 1516.200 796.075 1516.270 ;
    END
  END r0_rd_out[192]
  PIN r0_rd_out[193]
    DIRECTION OUTPUT ;
    USE SIGNAL ;
    SHAPE ABUTMENT ;
    PORT
      LAYER metal3 ;
      RECT 796.145 1516.200 796.215 1516.270 ;
    END
  END r0_rd_out[193]
  PIN r0_rd_out[194]
    DIRECTION OUTPUT ;
    USE SIGNAL ;
    SHAPE ABUTMENT ;
    PORT
      LAYER metal3 ;
      RECT 796.285 1516.200 796.355 1516.270 ;
    END
  END r0_rd_out[194]
  PIN r0_rd_out[195]
    DIRECTION OUTPUT ;
    USE SIGNAL ;
    SHAPE ABUTMENT ;
    PORT
      LAYER metal3 ;
      RECT 796.425 1516.200 796.495 1516.270 ;
    END
  END r0_rd_out[195]
  PIN r0_rd_out[196]
    DIRECTION OUTPUT ;
    USE SIGNAL ;
    SHAPE ABUTMENT ;
    PORT
      LAYER metal3 ;
      RECT 796.565 1516.200 796.635 1516.270 ;
    END
  END r0_rd_out[196]
  PIN r0_rd_out[197]
    DIRECTION OUTPUT ;
    USE SIGNAL ;
    SHAPE ABUTMENT ;
    PORT
      LAYER metal3 ;
      RECT 796.705 1516.200 796.775 1516.270 ;
    END
  END r0_rd_out[197]
  PIN r0_rd_out[198]
    DIRECTION OUTPUT ;
    USE SIGNAL ;
    SHAPE ABUTMENT ;
    PORT
      LAYER metal3 ;
      RECT 796.845 1516.200 796.915 1516.270 ;
    END
  END r0_rd_out[198]
  PIN r0_rd_out[199]
    DIRECTION OUTPUT ;
    USE SIGNAL ;
    SHAPE ABUTMENT ;
    PORT
      LAYER metal3 ;
      RECT 796.985 1516.200 797.055 1516.270 ;
    END
  END r0_rd_out[199]
  PIN r0_rd_out[200]
    DIRECTION OUTPUT ;
    USE SIGNAL ;
    SHAPE ABUTMENT ;
    PORT
      LAYER metal3 ;
      RECT 797.125 1516.200 797.195 1516.270 ;
    END
  END r0_rd_out[200]
  PIN r0_rd_out[201]
    DIRECTION OUTPUT ;
    USE SIGNAL ;
    SHAPE ABUTMENT ;
    PORT
      LAYER metal3 ;
      RECT 797.265 1516.200 797.335 1516.270 ;
    END
  END r0_rd_out[201]
  PIN r0_rd_out[202]
    DIRECTION OUTPUT ;
    USE SIGNAL ;
    SHAPE ABUTMENT ;
    PORT
      LAYER metal3 ;
      RECT 797.405 1516.200 797.475 1516.270 ;
    END
  END r0_rd_out[202]
  PIN r0_rd_out[203]
    DIRECTION OUTPUT ;
    USE SIGNAL ;
    SHAPE ABUTMENT ;
    PORT
      LAYER metal3 ;
      RECT 797.545 1516.200 797.615 1516.270 ;
    END
  END r0_rd_out[203]
  PIN r0_rd_out[204]
    DIRECTION OUTPUT ;
    USE SIGNAL ;
    SHAPE ABUTMENT ;
    PORT
      LAYER metal3 ;
      RECT 797.685 1516.200 797.755 1516.270 ;
    END
  END r0_rd_out[204]
  PIN r0_rd_out[205]
    DIRECTION OUTPUT ;
    USE SIGNAL ;
    SHAPE ABUTMENT ;
    PORT
      LAYER metal3 ;
      RECT 797.825 1516.200 797.895 1516.270 ;
    END
  END r0_rd_out[205]
  PIN r0_rd_out[206]
    DIRECTION OUTPUT ;
    USE SIGNAL ;
    SHAPE ABUTMENT ;
    PORT
      LAYER metal3 ;
      RECT 797.965 1516.200 798.035 1516.270 ;
    END
  END r0_rd_out[206]
  PIN r0_rd_out[207]
    DIRECTION OUTPUT ;
    USE SIGNAL ;
    SHAPE ABUTMENT ;
    PORT
      LAYER metal3 ;
      RECT 798.105 1516.200 798.175 1516.270 ;
    END
  END r0_rd_out[207]
  PIN r0_rd_out[208]
    DIRECTION OUTPUT ;
    USE SIGNAL ;
    SHAPE ABUTMENT ;
    PORT
      LAYER metal3 ;
      RECT 798.245 1516.200 798.315 1516.270 ;
    END
  END r0_rd_out[208]
  PIN r0_rd_out[209]
    DIRECTION OUTPUT ;
    USE SIGNAL ;
    SHAPE ABUTMENT ;
    PORT
      LAYER metal3 ;
      RECT 798.385 1516.200 798.455 1516.270 ;
    END
  END r0_rd_out[209]
  PIN r0_rd_out[210]
    DIRECTION OUTPUT ;
    USE SIGNAL ;
    SHAPE ABUTMENT ;
    PORT
      LAYER metal3 ;
      RECT 798.525 1516.200 798.595 1516.270 ;
    END
  END r0_rd_out[210]
  PIN r0_rd_out[211]
    DIRECTION OUTPUT ;
    USE SIGNAL ;
    SHAPE ABUTMENT ;
    PORT
      LAYER metal3 ;
      RECT 798.665 1516.200 798.735 1516.270 ;
    END
  END r0_rd_out[211]
  PIN r0_rd_out[212]
    DIRECTION OUTPUT ;
    USE SIGNAL ;
    SHAPE ABUTMENT ;
    PORT
      LAYER metal3 ;
      RECT 798.805 1516.200 798.875 1516.270 ;
    END
  END r0_rd_out[212]
  PIN r0_rd_out[213]
    DIRECTION OUTPUT ;
    USE SIGNAL ;
    SHAPE ABUTMENT ;
    PORT
      LAYER metal3 ;
      RECT 798.945 1516.200 799.015 1516.270 ;
    END
  END r0_rd_out[213]
  PIN r0_rd_out[214]
    DIRECTION OUTPUT ;
    USE SIGNAL ;
    SHAPE ABUTMENT ;
    PORT
      LAYER metal3 ;
      RECT 799.085 1516.200 799.155 1516.270 ;
    END
  END r0_rd_out[214]
  PIN r0_rd_out[215]
    DIRECTION OUTPUT ;
    USE SIGNAL ;
    SHAPE ABUTMENT ;
    PORT
      LAYER metal3 ;
      RECT 799.225 1516.200 799.295 1516.270 ;
    END
  END r0_rd_out[215]
  PIN r0_rd_out[216]
    DIRECTION OUTPUT ;
    USE SIGNAL ;
    SHAPE ABUTMENT ;
    PORT
      LAYER metal3 ;
      RECT 799.365 1516.200 799.435 1516.270 ;
    END
  END r0_rd_out[216]
  PIN r0_rd_out[217]
    DIRECTION OUTPUT ;
    USE SIGNAL ;
    SHAPE ABUTMENT ;
    PORT
      LAYER metal3 ;
      RECT 799.505 1516.200 799.575 1516.270 ;
    END
  END r0_rd_out[217]
  PIN r0_rd_out[218]
    DIRECTION OUTPUT ;
    USE SIGNAL ;
    SHAPE ABUTMENT ;
    PORT
      LAYER metal3 ;
      RECT 799.645 1516.200 799.715 1516.270 ;
    END
  END r0_rd_out[218]
  PIN r0_rd_out[219]
    DIRECTION OUTPUT ;
    USE SIGNAL ;
    SHAPE ABUTMENT ;
    PORT
      LAYER metal3 ;
      RECT 799.785 1516.200 799.855 1516.270 ;
    END
  END r0_rd_out[219]
  PIN r0_rd_out[220]
    DIRECTION OUTPUT ;
    USE SIGNAL ;
    SHAPE ABUTMENT ;
    PORT
      LAYER metal3 ;
      RECT 799.925 1516.200 799.995 1516.270 ;
    END
  END r0_rd_out[220]
  PIN r0_rd_out[221]
    DIRECTION OUTPUT ;
    USE SIGNAL ;
    SHAPE ABUTMENT ;
    PORT
      LAYER metal3 ;
      RECT 800.065 1516.200 800.135 1516.270 ;
    END
  END r0_rd_out[221]
  PIN r0_rd_out[222]
    DIRECTION OUTPUT ;
    USE SIGNAL ;
    SHAPE ABUTMENT ;
    PORT
      LAYER metal3 ;
      RECT 800.205 1516.200 800.275 1516.270 ;
    END
  END r0_rd_out[222]
  PIN r0_rd_out[223]
    DIRECTION OUTPUT ;
    USE SIGNAL ;
    SHAPE ABUTMENT ;
    PORT
      LAYER metal3 ;
      RECT 800.345 1516.200 800.415 1516.270 ;
    END
  END r0_rd_out[223]
  PIN r0_rd_out[224]
    DIRECTION OUTPUT ;
    USE SIGNAL ;
    SHAPE ABUTMENT ;
    PORT
      LAYER metal3 ;
      RECT 800.485 1516.200 800.555 1516.270 ;
    END
  END r0_rd_out[224]
  PIN r0_rd_out[225]
    DIRECTION OUTPUT ;
    USE SIGNAL ;
    SHAPE ABUTMENT ;
    PORT
      LAYER metal3 ;
      RECT 800.625 1516.200 800.695 1516.270 ;
    END
  END r0_rd_out[225]
  PIN r0_rd_out[226]
    DIRECTION OUTPUT ;
    USE SIGNAL ;
    SHAPE ABUTMENT ;
    PORT
      LAYER metal3 ;
      RECT 800.765 1516.200 800.835 1516.270 ;
    END
  END r0_rd_out[226]
  PIN r0_rd_out[227]
    DIRECTION OUTPUT ;
    USE SIGNAL ;
    SHAPE ABUTMENT ;
    PORT
      LAYER metal3 ;
      RECT 800.905 1516.200 800.975 1516.270 ;
    END
  END r0_rd_out[227]
  PIN r0_rd_out[228]
    DIRECTION OUTPUT ;
    USE SIGNAL ;
    SHAPE ABUTMENT ;
    PORT
      LAYER metal3 ;
      RECT 801.045 1516.200 801.115 1516.270 ;
    END
  END r0_rd_out[228]
  PIN r0_rd_out[229]
    DIRECTION OUTPUT ;
    USE SIGNAL ;
    SHAPE ABUTMENT ;
    PORT
      LAYER metal3 ;
      RECT 801.185 1516.200 801.255 1516.270 ;
    END
  END r0_rd_out[229]
  PIN r0_rd_out[230]
    DIRECTION OUTPUT ;
    USE SIGNAL ;
    SHAPE ABUTMENT ;
    PORT
      LAYER metal3 ;
      RECT 801.325 1516.200 801.395 1516.270 ;
    END
  END r0_rd_out[230]
  PIN r0_rd_out[231]
    DIRECTION OUTPUT ;
    USE SIGNAL ;
    SHAPE ABUTMENT ;
    PORT
      LAYER metal3 ;
      RECT 801.465 1516.200 801.535 1516.270 ;
    END
  END r0_rd_out[231]
  PIN r0_rd_out[232]
    DIRECTION OUTPUT ;
    USE SIGNAL ;
    SHAPE ABUTMENT ;
    PORT
      LAYER metal3 ;
      RECT 801.605 1516.200 801.675 1516.270 ;
    END
  END r0_rd_out[232]
  PIN r0_rd_out[233]
    DIRECTION OUTPUT ;
    USE SIGNAL ;
    SHAPE ABUTMENT ;
    PORT
      LAYER metal3 ;
      RECT 801.745 1516.200 801.815 1516.270 ;
    END
  END r0_rd_out[233]
  PIN r0_rd_out[234]
    DIRECTION OUTPUT ;
    USE SIGNAL ;
    SHAPE ABUTMENT ;
    PORT
      LAYER metal3 ;
      RECT 801.885 1516.200 801.955 1516.270 ;
    END
  END r0_rd_out[234]
  PIN r0_rd_out[235]
    DIRECTION OUTPUT ;
    USE SIGNAL ;
    SHAPE ABUTMENT ;
    PORT
      LAYER metal3 ;
      RECT 802.025 1516.200 802.095 1516.270 ;
    END
  END r0_rd_out[235]
  PIN r0_rd_out[236]
    DIRECTION OUTPUT ;
    USE SIGNAL ;
    SHAPE ABUTMENT ;
    PORT
      LAYER metal3 ;
      RECT 802.165 1516.200 802.235 1516.270 ;
    END
  END r0_rd_out[236]
  PIN r0_rd_out[237]
    DIRECTION OUTPUT ;
    USE SIGNAL ;
    SHAPE ABUTMENT ;
    PORT
      LAYER metal3 ;
      RECT 802.305 1516.200 802.375 1516.270 ;
    END
  END r0_rd_out[237]
  PIN r0_rd_out[238]
    DIRECTION OUTPUT ;
    USE SIGNAL ;
    SHAPE ABUTMENT ;
    PORT
      LAYER metal3 ;
      RECT 802.445 1516.200 802.515 1516.270 ;
    END
  END r0_rd_out[238]
  PIN r0_rd_out[239]
    DIRECTION OUTPUT ;
    USE SIGNAL ;
    SHAPE ABUTMENT ;
    PORT
      LAYER metal3 ;
      RECT 802.585 1516.200 802.655 1516.270 ;
    END
  END r0_rd_out[239]
  PIN r0_rd_out[240]
    DIRECTION OUTPUT ;
    USE SIGNAL ;
    SHAPE ABUTMENT ;
    PORT
      LAYER metal3 ;
      RECT 802.725 1516.200 802.795 1516.270 ;
    END
  END r0_rd_out[240]
  PIN r0_rd_out[241]
    DIRECTION OUTPUT ;
    USE SIGNAL ;
    SHAPE ABUTMENT ;
    PORT
      LAYER metal3 ;
      RECT 802.865 1516.200 802.935 1516.270 ;
    END
  END r0_rd_out[241]
  PIN r0_rd_out[242]
    DIRECTION OUTPUT ;
    USE SIGNAL ;
    SHAPE ABUTMENT ;
    PORT
      LAYER metal3 ;
      RECT 803.005 1516.200 803.075 1516.270 ;
    END
  END r0_rd_out[242]
  PIN r0_rd_out[243]
    DIRECTION OUTPUT ;
    USE SIGNAL ;
    SHAPE ABUTMENT ;
    PORT
      LAYER metal3 ;
      RECT 803.145 1516.200 803.215 1516.270 ;
    END
  END r0_rd_out[243]
  PIN r0_rd_out[244]
    DIRECTION OUTPUT ;
    USE SIGNAL ;
    SHAPE ABUTMENT ;
    PORT
      LAYER metal3 ;
      RECT 803.285 1516.200 803.355 1516.270 ;
    END
  END r0_rd_out[244]
  PIN r0_rd_out[245]
    DIRECTION OUTPUT ;
    USE SIGNAL ;
    SHAPE ABUTMENT ;
    PORT
      LAYER metal3 ;
      RECT 803.425 1516.200 803.495 1516.270 ;
    END
  END r0_rd_out[245]
  PIN r0_rd_out[246]
    DIRECTION OUTPUT ;
    USE SIGNAL ;
    SHAPE ABUTMENT ;
    PORT
      LAYER metal3 ;
      RECT 803.565 1516.200 803.635 1516.270 ;
    END
  END r0_rd_out[246]
  PIN r0_rd_out[247]
    DIRECTION OUTPUT ;
    USE SIGNAL ;
    SHAPE ABUTMENT ;
    PORT
      LAYER metal3 ;
      RECT 803.705 1516.200 803.775 1516.270 ;
    END
  END r0_rd_out[247]
  PIN r0_rd_out[248]
    DIRECTION OUTPUT ;
    USE SIGNAL ;
    SHAPE ABUTMENT ;
    PORT
      LAYER metal3 ;
      RECT 803.845 1516.200 803.915 1516.270 ;
    END
  END r0_rd_out[248]
  PIN r0_rd_out[249]
    DIRECTION OUTPUT ;
    USE SIGNAL ;
    SHAPE ABUTMENT ;
    PORT
      LAYER metal3 ;
      RECT 803.985 1516.200 804.055 1516.270 ;
    END
  END r0_rd_out[249]
  PIN r0_rd_out[250]
    DIRECTION OUTPUT ;
    USE SIGNAL ;
    SHAPE ABUTMENT ;
    PORT
      LAYER metal3 ;
      RECT 804.125 1516.200 804.195 1516.270 ;
    END
  END r0_rd_out[250]
  PIN r0_rd_out[251]
    DIRECTION OUTPUT ;
    USE SIGNAL ;
    SHAPE ABUTMENT ;
    PORT
      LAYER metal3 ;
      RECT 804.265 1516.200 804.335 1516.270 ;
    END
  END r0_rd_out[251]
  PIN r0_rd_out[252]
    DIRECTION OUTPUT ;
    USE SIGNAL ;
    SHAPE ABUTMENT ;
    PORT
      LAYER metal3 ;
      RECT 804.405 1516.200 804.475 1516.270 ;
    END
  END r0_rd_out[252]
  PIN r0_rd_out[253]
    DIRECTION OUTPUT ;
    USE SIGNAL ;
    SHAPE ABUTMENT ;
    PORT
      LAYER metal3 ;
      RECT 804.545 1516.200 804.615 1516.270 ;
    END
  END r0_rd_out[253]
  PIN r0_rd_out[254]
    DIRECTION OUTPUT ;
    USE SIGNAL ;
    SHAPE ABUTMENT ;
    PORT
      LAYER metal3 ;
      RECT 804.685 1516.200 804.755 1516.270 ;
    END
  END r0_rd_out[254]
  PIN r0_rd_out[255]
    DIRECTION OUTPUT ;
    USE SIGNAL ;
    SHAPE ABUTMENT ;
    PORT
      LAYER metal3 ;
      RECT 804.825 1516.200 804.895 1516.270 ;
    END
  END r0_rd_out[255]
  PIN r0_rd_out[256]
    DIRECTION OUTPUT ;
    USE SIGNAL ;
    SHAPE ABUTMENT ;
    PORT
      LAYER metal3 ;
      RECT 804.965 1516.200 805.035 1516.270 ;
    END
  END r0_rd_out[256]
  PIN r0_rd_out[257]
    DIRECTION OUTPUT ;
    USE SIGNAL ;
    SHAPE ABUTMENT ;
    PORT
      LAYER metal3 ;
      RECT 805.105 1516.200 805.175 1516.270 ;
    END
  END r0_rd_out[257]
  PIN r0_rd_out[258]
    DIRECTION OUTPUT ;
    USE SIGNAL ;
    SHAPE ABUTMENT ;
    PORT
      LAYER metal3 ;
      RECT 805.245 1516.200 805.315 1516.270 ;
    END
  END r0_rd_out[258]
  PIN r0_rd_out[259]
    DIRECTION OUTPUT ;
    USE SIGNAL ;
    SHAPE ABUTMENT ;
    PORT
      LAYER metal3 ;
      RECT 805.385 1516.200 805.455 1516.270 ;
    END
  END r0_rd_out[259]
  PIN r0_rd_out[260]
    DIRECTION OUTPUT ;
    USE SIGNAL ;
    SHAPE ABUTMENT ;
    PORT
      LAYER metal3 ;
      RECT 805.525 1516.200 805.595 1516.270 ;
    END
  END r0_rd_out[260]
  PIN r0_rd_out[261]
    DIRECTION OUTPUT ;
    USE SIGNAL ;
    SHAPE ABUTMENT ;
    PORT
      LAYER metal3 ;
      RECT 805.665 1516.200 805.735 1516.270 ;
    END
  END r0_rd_out[261]
  PIN r0_rd_out[262]
    DIRECTION OUTPUT ;
    USE SIGNAL ;
    SHAPE ABUTMENT ;
    PORT
      LAYER metal3 ;
      RECT 805.805 1516.200 805.875 1516.270 ;
    END
  END r0_rd_out[262]
  PIN r0_rd_out[263]
    DIRECTION OUTPUT ;
    USE SIGNAL ;
    SHAPE ABUTMENT ;
    PORT
      LAYER metal3 ;
      RECT 805.945 1516.200 806.015 1516.270 ;
    END
  END r0_rd_out[263]
  PIN r0_rd_out[264]
    DIRECTION OUTPUT ;
    USE SIGNAL ;
    SHAPE ABUTMENT ;
    PORT
      LAYER metal3 ;
      RECT 806.085 1516.200 806.155 1516.270 ;
    END
  END r0_rd_out[264]
  PIN r0_rd_out[265]
    DIRECTION OUTPUT ;
    USE SIGNAL ;
    SHAPE ABUTMENT ;
    PORT
      LAYER metal3 ;
      RECT 806.225 1516.200 806.295 1516.270 ;
    END
  END r0_rd_out[265]
  PIN r0_rd_out[266]
    DIRECTION OUTPUT ;
    USE SIGNAL ;
    SHAPE ABUTMENT ;
    PORT
      LAYER metal3 ;
      RECT 806.365 1516.200 806.435 1516.270 ;
    END
  END r0_rd_out[266]
  PIN r0_rd_out[267]
    DIRECTION OUTPUT ;
    USE SIGNAL ;
    SHAPE ABUTMENT ;
    PORT
      LAYER metal3 ;
      RECT 806.505 1516.200 806.575 1516.270 ;
    END
  END r0_rd_out[267]
  PIN r0_rd_out[268]
    DIRECTION OUTPUT ;
    USE SIGNAL ;
    SHAPE ABUTMENT ;
    PORT
      LAYER metal3 ;
      RECT 806.645 1516.200 806.715 1516.270 ;
    END
  END r0_rd_out[268]
  PIN r0_rd_out[269]
    DIRECTION OUTPUT ;
    USE SIGNAL ;
    SHAPE ABUTMENT ;
    PORT
      LAYER metal3 ;
      RECT 806.785 1516.200 806.855 1516.270 ;
    END
  END r0_rd_out[269]
  PIN r0_rd_out[270]
    DIRECTION OUTPUT ;
    USE SIGNAL ;
    SHAPE ABUTMENT ;
    PORT
      LAYER metal3 ;
      RECT 806.925 1516.200 806.995 1516.270 ;
    END
  END r0_rd_out[270]
  PIN r0_rd_out[271]
    DIRECTION OUTPUT ;
    USE SIGNAL ;
    SHAPE ABUTMENT ;
    PORT
      LAYER metal3 ;
      RECT 807.065 1516.200 807.135 1516.270 ;
    END
  END r0_rd_out[271]
  PIN r0_rd_out[272]
    DIRECTION OUTPUT ;
    USE SIGNAL ;
    SHAPE ABUTMENT ;
    PORT
      LAYER metal3 ;
      RECT 807.205 1516.200 807.275 1516.270 ;
    END
  END r0_rd_out[272]
  PIN r0_rd_out[273]
    DIRECTION OUTPUT ;
    USE SIGNAL ;
    SHAPE ABUTMENT ;
    PORT
      LAYER metal3 ;
      RECT 807.345 1516.200 807.415 1516.270 ;
    END
  END r0_rd_out[273]
  PIN r0_rd_out[274]
    DIRECTION OUTPUT ;
    USE SIGNAL ;
    SHAPE ABUTMENT ;
    PORT
      LAYER metal3 ;
      RECT 807.485 1516.200 807.555 1516.270 ;
    END
  END r0_rd_out[274]
  PIN r0_rd_out[275]
    DIRECTION OUTPUT ;
    USE SIGNAL ;
    SHAPE ABUTMENT ;
    PORT
      LAYER metal3 ;
      RECT 807.625 1516.200 807.695 1516.270 ;
    END
  END r0_rd_out[275]
  PIN r0_rd_out[276]
    DIRECTION OUTPUT ;
    USE SIGNAL ;
    SHAPE ABUTMENT ;
    PORT
      LAYER metal3 ;
      RECT 807.765 1516.200 807.835 1516.270 ;
    END
  END r0_rd_out[276]
  PIN r0_rd_out[277]
    DIRECTION OUTPUT ;
    USE SIGNAL ;
    SHAPE ABUTMENT ;
    PORT
      LAYER metal3 ;
      RECT 807.905 1516.200 807.975 1516.270 ;
    END
  END r0_rd_out[277]
  PIN r0_rd_out[278]
    DIRECTION OUTPUT ;
    USE SIGNAL ;
    SHAPE ABUTMENT ;
    PORT
      LAYER metal3 ;
      RECT 808.045 1516.200 808.115 1516.270 ;
    END
  END r0_rd_out[278]
  PIN r0_rd_out[279]
    DIRECTION OUTPUT ;
    USE SIGNAL ;
    SHAPE ABUTMENT ;
    PORT
      LAYER metal3 ;
      RECT 808.185 1516.200 808.255 1516.270 ;
    END
  END r0_rd_out[279]
  PIN r0_rd_out[280]
    DIRECTION OUTPUT ;
    USE SIGNAL ;
    SHAPE ABUTMENT ;
    PORT
      LAYER metal3 ;
      RECT 808.325 1516.200 808.395 1516.270 ;
    END
  END r0_rd_out[280]
  PIN r0_rd_out[281]
    DIRECTION OUTPUT ;
    USE SIGNAL ;
    SHAPE ABUTMENT ;
    PORT
      LAYER metal3 ;
      RECT 808.465 1516.200 808.535 1516.270 ;
    END
  END r0_rd_out[281]
  PIN r0_rd_out[282]
    DIRECTION OUTPUT ;
    USE SIGNAL ;
    SHAPE ABUTMENT ;
    PORT
      LAYER metal3 ;
      RECT 808.605 1516.200 808.675 1516.270 ;
    END
  END r0_rd_out[282]
  PIN r0_rd_out[283]
    DIRECTION OUTPUT ;
    USE SIGNAL ;
    SHAPE ABUTMENT ;
    PORT
      LAYER metal3 ;
      RECT 808.745 1516.200 808.815 1516.270 ;
    END
  END r0_rd_out[283]
  PIN r0_rd_out[284]
    DIRECTION OUTPUT ;
    USE SIGNAL ;
    SHAPE ABUTMENT ;
    PORT
      LAYER metal3 ;
      RECT 808.885 1516.200 808.955 1516.270 ;
    END
  END r0_rd_out[284]
  PIN r0_rd_out[285]
    DIRECTION OUTPUT ;
    USE SIGNAL ;
    SHAPE ABUTMENT ;
    PORT
      LAYER metal3 ;
      RECT 809.025 1516.200 809.095 1516.270 ;
    END
  END r0_rd_out[285]
  PIN r0_rd_out[286]
    DIRECTION OUTPUT ;
    USE SIGNAL ;
    SHAPE ABUTMENT ;
    PORT
      LAYER metal3 ;
      RECT 809.165 1516.200 809.235 1516.270 ;
    END
  END r0_rd_out[286]
  PIN r0_rd_out[287]
    DIRECTION OUTPUT ;
    USE SIGNAL ;
    SHAPE ABUTMENT ;
    PORT
      LAYER metal3 ;
      RECT 809.305 1516.200 809.375 1516.270 ;
    END
  END r0_rd_out[287]
  PIN r0_rd_out[288]
    DIRECTION OUTPUT ;
    USE SIGNAL ;
    SHAPE ABUTMENT ;
    PORT
      LAYER metal3 ;
      RECT 809.445 1516.200 809.515 1516.270 ;
    END
  END r0_rd_out[288]
  PIN r0_rd_out[289]
    DIRECTION OUTPUT ;
    USE SIGNAL ;
    SHAPE ABUTMENT ;
    PORT
      LAYER metal3 ;
      RECT 809.585 1516.200 809.655 1516.270 ;
    END
  END r0_rd_out[289]
  PIN r0_rd_out[290]
    DIRECTION OUTPUT ;
    USE SIGNAL ;
    SHAPE ABUTMENT ;
    PORT
      LAYER metal3 ;
      RECT 809.725 1516.200 809.795 1516.270 ;
    END
  END r0_rd_out[290]
  PIN r0_rd_out[291]
    DIRECTION OUTPUT ;
    USE SIGNAL ;
    SHAPE ABUTMENT ;
    PORT
      LAYER metal3 ;
      RECT 809.865 1516.200 809.935 1516.270 ;
    END
  END r0_rd_out[291]
  PIN r0_rd_out[292]
    DIRECTION OUTPUT ;
    USE SIGNAL ;
    SHAPE ABUTMENT ;
    PORT
      LAYER metal3 ;
      RECT 810.005 1516.200 810.075 1516.270 ;
    END
  END r0_rd_out[292]
  PIN r0_rd_out[293]
    DIRECTION OUTPUT ;
    USE SIGNAL ;
    SHAPE ABUTMENT ;
    PORT
      LAYER metal3 ;
      RECT 810.145 1516.200 810.215 1516.270 ;
    END
  END r0_rd_out[293]
  PIN r0_rd_out[294]
    DIRECTION OUTPUT ;
    USE SIGNAL ;
    SHAPE ABUTMENT ;
    PORT
      LAYER metal3 ;
      RECT 810.285 1516.200 810.355 1516.270 ;
    END
  END r0_rd_out[294]
  PIN r0_rd_out[295]
    DIRECTION OUTPUT ;
    USE SIGNAL ;
    SHAPE ABUTMENT ;
    PORT
      LAYER metal3 ;
      RECT 810.425 1516.200 810.495 1516.270 ;
    END
  END r0_rd_out[295]
  PIN r0_rd_out[296]
    DIRECTION OUTPUT ;
    USE SIGNAL ;
    SHAPE ABUTMENT ;
    PORT
      LAYER metal3 ;
      RECT 810.565 1516.200 810.635 1516.270 ;
    END
  END r0_rd_out[296]
  PIN r0_rd_out[297]
    DIRECTION OUTPUT ;
    USE SIGNAL ;
    SHAPE ABUTMENT ;
    PORT
      LAYER metal3 ;
      RECT 810.705 1516.200 810.775 1516.270 ;
    END
  END r0_rd_out[297]
  PIN r0_rd_out[298]
    DIRECTION OUTPUT ;
    USE SIGNAL ;
    SHAPE ABUTMENT ;
    PORT
      LAYER metal3 ;
      RECT 810.845 1516.200 810.915 1516.270 ;
    END
  END r0_rd_out[298]
  PIN r0_rd_out[299]
    DIRECTION OUTPUT ;
    USE SIGNAL ;
    SHAPE ABUTMENT ;
    PORT
      LAYER metal3 ;
      RECT 810.985 1516.200 811.055 1516.270 ;
    END
  END r0_rd_out[299]
  PIN r0_rd_out[300]
    DIRECTION OUTPUT ;
    USE SIGNAL ;
    SHAPE ABUTMENT ;
    PORT
      LAYER metal3 ;
      RECT 811.125 1516.200 811.195 1516.270 ;
    END
  END r0_rd_out[300]
  PIN r0_rd_out[301]
    DIRECTION OUTPUT ;
    USE SIGNAL ;
    SHAPE ABUTMENT ;
    PORT
      LAYER metal3 ;
      RECT 811.265 1516.200 811.335 1516.270 ;
    END
  END r0_rd_out[301]
  PIN r0_rd_out[302]
    DIRECTION OUTPUT ;
    USE SIGNAL ;
    SHAPE ABUTMENT ;
    PORT
      LAYER metal3 ;
      RECT 811.405 1516.200 811.475 1516.270 ;
    END
  END r0_rd_out[302]
  PIN r0_rd_out[303]
    DIRECTION OUTPUT ;
    USE SIGNAL ;
    SHAPE ABUTMENT ;
    PORT
      LAYER metal3 ;
      RECT 811.545 1516.200 811.615 1516.270 ;
    END
  END r0_rd_out[303]
  PIN r0_rd_out[304]
    DIRECTION OUTPUT ;
    USE SIGNAL ;
    SHAPE ABUTMENT ;
    PORT
      LAYER metal3 ;
      RECT 811.685 1516.200 811.755 1516.270 ;
    END
  END r0_rd_out[304]
  PIN r0_rd_out[305]
    DIRECTION OUTPUT ;
    USE SIGNAL ;
    SHAPE ABUTMENT ;
    PORT
      LAYER metal3 ;
      RECT 811.825 1516.200 811.895 1516.270 ;
    END
  END r0_rd_out[305]
  PIN r0_rd_out[306]
    DIRECTION OUTPUT ;
    USE SIGNAL ;
    SHAPE ABUTMENT ;
    PORT
      LAYER metal3 ;
      RECT 811.965 1516.200 812.035 1516.270 ;
    END
  END r0_rd_out[306]
  PIN r0_rd_out[307]
    DIRECTION OUTPUT ;
    USE SIGNAL ;
    SHAPE ABUTMENT ;
    PORT
      LAYER metal3 ;
      RECT 812.105 1516.200 812.175 1516.270 ;
    END
  END r0_rd_out[307]
  PIN r0_rd_out[308]
    DIRECTION OUTPUT ;
    USE SIGNAL ;
    SHAPE ABUTMENT ;
    PORT
      LAYER metal3 ;
      RECT 812.245 1516.200 812.315 1516.270 ;
    END
  END r0_rd_out[308]
  PIN r0_rd_out[309]
    DIRECTION OUTPUT ;
    USE SIGNAL ;
    SHAPE ABUTMENT ;
    PORT
      LAYER metal3 ;
      RECT 812.385 1516.200 812.455 1516.270 ;
    END
  END r0_rd_out[309]
  PIN r0_rd_out[310]
    DIRECTION OUTPUT ;
    USE SIGNAL ;
    SHAPE ABUTMENT ;
    PORT
      LAYER metal3 ;
      RECT 812.525 1516.200 812.595 1516.270 ;
    END
  END r0_rd_out[310]
  PIN r0_rd_out[311]
    DIRECTION OUTPUT ;
    USE SIGNAL ;
    SHAPE ABUTMENT ;
    PORT
      LAYER metal3 ;
      RECT 812.665 1516.200 812.735 1516.270 ;
    END
  END r0_rd_out[311]
  PIN r0_rd_out[312]
    DIRECTION OUTPUT ;
    USE SIGNAL ;
    SHAPE ABUTMENT ;
    PORT
      LAYER metal3 ;
      RECT 812.805 1516.200 812.875 1516.270 ;
    END
  END r0_rd_out[312]
  PIN r0_rd_out[313]
    DIRECTION OUTPUT ;
    USE SIGNAL ;
    SHAPE ABUTMENT ;
    PORT
      LAYER metal3 ;
      RECT 812.945 1516.200 813.015 1516.270 ;
    END
  END r0_rd_out[313]
  PIN r0_rd_out[314]
    DIRECTION OUTPUT ;
    USE SIGNAL ;
    SHAPE ABUTMENT ;
    PORT
      LAYER metal3 ;
      RECT 813.085 1516.200 813.155 1516.270 ;
    END
  END r0_rd_out[314]
  PIN r0_rd_out[315]
    DIRECTION OUTPUT ;
    USE SIGNAL ;
    SHAPE ABUTMENT ;
    PORT
      LAYER metal3 ;
      RECT 813.225 1516.200 813.295 1516.270 ;
    END
  END r0_rd_out[315]
  PIN r0_rd_out[316]
    DIRECTION OUTPUT ;
    USE SIGNAL ;
    SHAPE ABUTMENT ;
    PORT
      LAYER metal3 ;
      RECT 813.365 1516.200 813.435 1516.270 ;
    END
  END r0_rd_out[316]
  PIN r0_rd_out[317]
    DIRECTION OUTPUT ;
    USE SIGNAL ;
    SHAPE ABUTMENT ;
    PORT
      LAYER metal3 ;
      RECT 813.505 1516.200 813.575 1516.270 ;
    END
  END r0_rd_out[317]
  PIN r0_rd_out[318]
    DIRECTION OUTPUT ;
    USE SIGNAL ;
    SHAPE ABUTMENT ;
    PORT
      LAYER metal3 ;
      RECT 813.645 1516.200 813.715 1516.270 ;
    END
  END r0_rd_out[318]
  PIN r0_rd_out[319]
    DIRECTION OUTPUT ;
    USE SIGNAL ;
    SHAPE ABUTMENT ;
    PORT
      LAYER metal3 ;
      RECT 813.785 1516.200 813.855 1516.270 ;
    END
  END r0_rd_out[319]
  PIN r0_rd_out[320]
    DIRECTION OUTPUT ;
    USE SIGNAL ;
    SHAPE ABUTMENT ;
    PORT
      LAYER metal3 ;
      RECT 813.925 1516.200 813.995 1516.270 ;
    END
  END r0_rd_out[320]
  PIN r0_rd_out[321]
    DIRECTION OUTPUT ;
    USE SIGNAL ;
    SHAPE ABUTMENT ;
    PORT
      LAYER metal3 ;
      RECT 814.065 1516.200 814.135 1516.270 ;
    END
  END r0_rd_out[321]
  PIN r0_rd_out[322]
    DIRECTION OUTPUT ;
    USE SIGNAL ;
    SHAPE ABUTMENT ;
    PORT
      LAYER metal3 ;
      RECT 814.205 1516.200 814.275 1516.270 ;
    END
  END r0_rd_out[322]
  PIN r0_rd_out[323]
    DIRECTION OUTPUT ;
    USE SIGNAL ;
    SHAPE ABUTMENT ;
    PORT
      LAYER metal3 ;
      RECT 814.345 1516.200 814.415 1516.270 ;
    END
  END r0_rd_out[323]
  PIN r0_rd_out[324]
    DIRECTION OUTPUT ;
    USE SIGNAL ;
    SHAPE ABUTMENT ;
    PORT
      LAYER metal3 ;
      RECT 814.485 1516.200 814.555 1516.270 ;
    END
  END r0_rd_out[324]
  PIN r0_rd_out[325]
    DIRECTION OUTPUT ;
    USE SIGNAL ;
    SHAPE ABUTMENT ;
    PORT
      LAYER metal3 ;
      RECT 814.625 1516.200 814.695 1516.270 ;
    END
  END r0_rd_out[325]
  PIN r0_rd_out[326]
    DIRECTION OUTPUT ;
    USE SIGNAL ;
    SHAPE ABUTMENT ;
    PORT
      LAYER metal3 ;
      RECT 814.765 1516.200 814.835 1516.270 ;
    END
  END r0_rd_out[326]
  PIN r0_rd_out[327]
    DIRECTION OUTPUT ;
    USE SIGNAL ;
    SHAPE ABUTMENT ;
    PORT
      LAYER metal3 ;
      RECT 814.905 1516.200 814.975 1516.270 ;
    END
  END r0_rd_out[327]
  PIN r0_rd_out[328]
    DIRECTION OUTPUT ;
    USE SIGNAL ;
    SHAPE ABUTMENT ;
    PORT
      LAYER metal3 ;
      RECT 815.045 1516.200 815.115 1516.270 ;
    END
  END r0_rd_out[328]
  PIN r0_rd_out[329]
    DIRECTION OUTPUT ;
    USE SIGNAL ;
    SHAPE ABUTMENT ;
    PORT
      LAYER metal3 ;
      RECT 815.185 1516.200 815.255 1516.270 ;
    END
  END r0_rd_out[329]
  PIN r0_rd_out[330]
    DIRECTION OUTPUT ;
    USE SIGNAL ;
    SHAPE ABUTMENT ;
    PORT
      LAYER metal3 ;
      RECT 815.325 1516.200 815.395 1516.270 ;
    END
  END r0_rd_out[330]
  PIN r0_rd_out[331]
    DIRECTION OUTPUT ;
    USE SIGNAL ;
    SHAPE ABUTMENT ;
    PORT
      LAYER metal3 ;
      RECT 815.465 1516.200 815.535 1516.270 ;
    END
  END r0_rd_out[331]
  PIN r0_rd_out[332]
    DIRECTION OUTPUT ;
    USE SIGNAL ;
    SHAPE ABUTMENT ;
    PORT
      LAYER metal3 ;
      RECT 815.605 1516.200 815.675 1516.270 ;
    END
  END r0_rd_out[332]
  PIN r0_rd_out[333]
    DIRECTION OUTPUT ;
    USE SIGNAL ;
    SHAPE ABUTMENT ;
    PORT
      LAYER metal3 ;
      RECT 815.745 1516.200 815.815 1516.270 ;
    END
  END r0_rd_out[333]
  PIN r0_rd_out[334]
    DIRECTION OUTPUT ;
    USE SIGNAL ;
    SHAPE ABUTMENT ;
    PORT
      LAYER metal3 ;
      RECT 815.885 1516.200 815.955 1516.270 ;
    END
  END r0_rd_out[334]
  PIN r0_rd_out[335]
    DIRECTION OUTPUT ;
    USE SIGNAL ;
    SHAPE ABUTMENT ;
    PORT
      LAYER metal3 ;
      RECT 816.025 1516.200 816.095 1516.270 ;
    END
  END r0_rd_out[335]
  PIN r0_rd_out[336]
    DIRECTION OUTPUT ;
    USE SIGNAL ;
    SHAPE ABUTMENT ;
    PORT
      LAYER metal3 ;
      RECT 816.165 1516.200 816.235 1516.270 ;
    END
  END r0_rd_out[336]
  PIN r0_rd_out[337]
    DIRECTION OUTPUT ;
    USE SIGNAL ;
    SHAPE ABUTMENT ;
    PORT
      LAYER metal3 ;
      RECT 816.305 1516.200 816.375 1516.270 ;
    END
  END r0_rd_out[337]
  PIN r0_rd_out[338]
    DIRECTION OUTPUT ;
    USE SIGNAL ;
    SHAPE ABUTMENT ;
    PORT
      LAYER metal3 ;
      RECT 816.445 1516.200 816.515 1516.270 ;
    END
  END r0_rd_out[338]
  PIN r0_rd_out[339]
    DIRECTION OUTPUT ;
    USE SIGNAL ;
    SHAPE ABUTMENT ;
    PORT
      LAYER metal3 ;
      RECT 816.585 1516.200 816.655 1516.270 ;
    END
  END r0_rd_out[339]
  PIN r0_rd_out[340]
    DIRECTION OUTPUT ;
    USE SIGNAL ;
    SHAPE ABUTMENT ;
    PORT
      LAYER metal3 ;
      RECT 816.725 1516.200 816.795 1516.270 ;
    END
  END r0_rd_out[340]
  PIN r0_rd_out[341]
    DIRECTION OUTPUT ;
    USE SIGNAL ;
    SHAPE ABUTMENT ;
    PORT
      LAYER metal3 ;
      RECT 816.865 1516.200 816.935 1516.270 ;
    END
  END r0_rd_out[341]
  PIN r0_rd_out[342]
    DIRECTION OUTPUT ;
    USE SIGNAL ;
    SHAPE ABUTMENT ;
    PORT
      LAYER metal3 ;
      RECT 817.005 1516.200 817.075 1516.270 ;
    END
  END r0_rd_out[342]
  PIN r0_rd_out[343]
    DIRECTION OUTPUT ;
    USE SIGNAL ;
    SHAPE ABUTMENT ;
    PORT
      LAYER metal3 ;
      RECT 817.145 1516.200 817.215 1516.270 ;
    END
  END r0_rd_out[343]
  PIN r0_rd_out[344]
    DIRECTION OUTPUT ;
    USE SIGNAL ;
    SHAPE ABUTMENT ;
    PORT
      LAYER metal3 ;
      RECT 817.285 1516.200 817.355 1516.270 ;
    END
  END r0_rd_out[344]
  PIN r0_rd_out[345]
    DIRECTION OUTPUT ;
    USE SIGNAL ;
    SHAPE ABUTMENT ;
    PORT
      LAYER metal3 ;
      RECT 817.425 1516.200 817.495 1516.270 ;
    END
  END r0_rd_out[345]
  PIN r0_rd_out[346]
    DIRECTION OUTPUT ;
    USE SIGNAL ;
    SHAPE ABUTMENT ;
    PORT
      LAYER metal3 ;
      RECT 817.565 1516.200 817.635 1516.270 ;
    END
  END r0_rd_out[346]
  PIN r0_rd_out[347]
    DIRECTION OUTPUT ;
    USE SIGNAL ;
    SHAPE ABUTMENT ;
    PORT
      LAYER metal3 ;
      RECT 817.705 1516.200 817.775 1516.270 ;
    END
  END r0_rd_out[347]
  PIN r0_rd_out[348]
    DIRECTION OUTPUT ;
    USE SIGNAL ;
    SHAPE ABUTMENT ;
    PORT
      LAYER metal3 ;
      RECT 817.845 1516.200 817.915 1516.270 ;
    END
  END r0_rd_out[348]
  PIN r0_rd_out[349]
    DIRECTION OUTPUT ;
    USE SIGNAL ;
    SHAPE ABUTMENT ;
    PORT
      LAYER metal3 ;
      RECT 817.985 1516.200 818.055 1516.270 ;
    END
  END r0_rd_out[349]
  PIN r0_rd_out[350]
    DIRECTION OUTPUT ;
    USE SIGNAL ;
    SHAPE ABUTMENT ;
    PORT
      LAYER metal3 ;
      RECT 818.125 1516.200 818.195 1516.270 ;
    END
  END r0_rd_out[350]
  PIN r0_rd_out[351]
    DIRECTION OUTPUT ;
    USE SIGNAL ;
    SHAPE ABUTMENT ;
    PORT
      LAYER metal3 ;
      RECT 818.265 1516.200 818.335 1516.270 ;
    END
  END r0_rd_out[351]
  PIN r0_rd_out[352]
    DIRECTION OUTPUT ;
    USE SIGNAL ;
    SHAPE ABUTMENT ;
    PORT
      LAYER metal3 ;
      RECT 818.405 1516.200 818.475 1516.270 ;
    END
  END r0_rd_out[352]
  PIN r0_rd_out[353]
    DIRECTION OUTPUT ;
    USE SIGNAL ;
    SHAPE ABUTMENT ;
    PORT
      LAYER metal3 ;
      RECT 818.545 1516.200 818.615 1516.270 ;
    END
  END r0_rd_out[353]
  PIN r0_rd_out[354]
    DIRECTION OUTPUT ;
    USE SIGNAL ;
    SHAPE ABUTMENT ;
    PORT
      LAYER metal3 ;
      RECT 818.685 1516.200 818.755 1516.270 ;
    END
  END r0_rd_out[354]
  PIN r0_rd_out[355]
    DIRECTION OUTPUT ;
    USE SIGNAL ;
    SHAPE ABUTMENT ;
    PORT
      LAYER metal3 ;
      RECT 818.825 1516.200 818.895 1516.270 ;
    END
  END r0_rd_out[355]
  PIN r0_rd_out[356]
    DIRECTION OUTPUT ;
    USE SIGNAL ;
    SHAPE ABUTMENT ;
    PORT
      LAYER metal3 ;
      RECT 818.965 1516.200 819.035 1516.270 ;
    END
  END r0_rd_out[356]
  PIN r0_rd_out[357]
    DIRECTION OUTPUT ;
    USE SIGNAL ;
    SHAPE ABUTMENT ;
    PORT
      LAYER metal3 ;
      RECT 819.105 1516.200 819.175 1516.270 ;
    END
  END r0_rd_out[357]
  PIN r0_rd_out[358]
    DIRECTION OUTPUT ;
    USE SIGNAL ;
    SHAPE ABUTMENT ;
    PORT
      LAYER metal3 ;
      RECT 819.245 1516.200 819.315 1516.270 ;
    END
  END r0_rd_out[358]
  PIN r0_rd_out[359]
    DIRECTION OUTPUT ;
    USE SIGNAL ;
    SHAPE ABUTMENT ;
    PORT
      LAYER metal3 ;
      RECT 819.385 1516.200 819.455 1516.270 ;
    END
  END r0_rd_out[359]
  PIN r0_rd_out[360]
    DIRECTION OUTPUT ;
    USE SIGNAL ;
    SHAPE ABUTMENT ;
    PORT
      LAYER metal3 ;
      RECT 819.525 1516.200 819.595 1516.270 ;
    END
  END r0_rd_out[360]
  PIN r0_rd_out[361]
    DIRECTION OUTPUT ;
    USE SIGNAL ;
    SHAPE ABUTMENT ;
    PORT
      LAYER metal3 ;
      RECT 819.665 1516.200 819.735 1516.270 ;
    END
  END r0_rd_out[361]
  PIN r0_rd_out[362]
    DIRECTION OUTPUT ;
    USE SIGNAL ;
    SHAPE ABUTMENT ;
    PORT
      LAYER metal3 ;
      RECT 819.805 1516.200 819.875 1516.270 ;
    END
  END r0_rd_out[362]
  PIN r0_rd_out[363]
    DIRECTION OUTPUT ;
    USE SIGNAL ;
    SHAPE ABUTMENT ;
    PORT
      LAYER metal3 ;
      RECT 819.945 1516.200 820.015 1516.270 ;
    END
  END r0_rd_out[363]
  PIN r0_rd_out[364]
    DIRECTION OUTPUT ;
    USE SIGNAL ;
    SHAPE ABUTMENT ;
    PORT
      LAYER metal3 ;
      RECT 820.085 1516.200 820.155 1516.270 ;
    END
  END r0_rd_out[364]
  PIN r0_rd_out[365]
    DIRECTION OUTPUT ;
    USE SIGNAL ;
    SHAPE ABUTMENT ;
    PORT
      LAYER metal3 ;
      RECT 820.225 1516.200 820.295 1516.270 ;
    END
  END r0_rd_out[365]
  PIN r0_rd_out[366]
    DIRECTION OUTPUT ;
    USE SIGNAL ;
    SHAPE ABUTMENT ;
    PORT
      LAYER metal3 ;
      RECT 820.365 1516.200 820.435 1516.270 ;
    END
  END r0_rd_out[366]
  PIN r0_rd_out[367]
    DIRECTION OUTPUT ;
    USE SIGNAL ;
    SHAPE ABUTMENT ;
    PORT
      LAYER metal3 ;
      RECT 820.505 1516.200 820.575 1516.270 ;
    END
  END r0_rd_out[367]
  PIN r0_rd_out[368]
    DIRECTION OUTPUT ;
    USE SIGNAL ;
    SHAPE ABUTMENT ;
    PORT
      LAYER metal3 ;
      RECT 820.645 1516.200 820.715 1516.270 ;
    END
  END r0_rd_out[368]
  PIN r0_rd_out[369]
    DIRECTION OUTPUT ;
    USE SIGNAL ;
    SHAPE ABUTMENT ;
    PORT
      LAYER metal3 ;
      RECT 820.785 1516.200 820.855 1516.270 ;
    END
  END r0_rd_out[369]
  PIN r0_rd_out[370]
    DIRECTION OUTPUT ;
    USE SIGNAL ;
    SHAPE ABUTMENT ;
    PORT
      LAYER metal3 ;
      RECT 820.925 1516.200 820.995 1516.270 ;
    END
  END r0_rd_out[370]
  PIN r0_rd_out[371]
    DIRECTION OUTPUT ;
    USE SIGNAL ;
    SHAPE ABUTMENT ;
    PORT
      LAYER metal3 ;
      RECT 821.065 1516.200 821.135 1516.270 ;
    END
  END r0_rd_out[371]
  PIN r0_rd_out[372]
    DIRECTION OUTPUT ;
    USE SIGNAL ;
    SHAPE ABUTMENT ;
    PORT
      LAYER metal3 ;
      RECT 821.205 1516.200 821.275 1516.270 ;
    END
  END r0_rd_out[372]
  PIN r0_rd_out[373]
    DIRECTION OUTPUT ;
    USE SIGNAL ;
    SHAPE ABUTMENT ;
    PORT
      LAYER metal3 ;
      RECT 821.345 1516.200 821.415 1516.270 ;
    END
  END r0_rd_out[373]
  PIN r0_rd_out[374]
    DIRECTION OUTPUT ;
    USE SIGNAL ;
    SHAPE ABUTMENT ;
    PORT
      LAYER metal3 ;
      RECT 821.485 1516.200 821.555 1516.270 ;
    END
  END r0_rd_out[374]
  PIN r0_rd_out[375]
    DIRECTION OUTPUT ;
    USE SIGNAL ;
    SHAPE ABUTMENT ;
    PORT
      LAYER metal3 ;
      RECT 821.625 1516.200 821.695 1516.270 ;
    END
  END r0_rd_out[375]
  PIN r0_rd_out[376]
    DIRECTION OUTPUT ;
    USE SIGNAL ;
    SHAPE ABUTMENT ;
    PORT
      LAYER metal3 ;
      RECT 821.765 1516.200 821.835 1516.270 ;
    END
  END r0_rd_out[376]
  PIN r0_rd_out[377]
    DIRECTION OUTPUT ;
    USE SIGNAL ;
    SHAPE ABUTMENT ;
    PORT
      LAYER metal3 ;
      RECT 821.905 1516.200 821.975 1516.270 ;
    END
  END r0_rd_out[377]
  PIN r0_rd_out[378]
    DIRECTION OUTPUT ;
    USE SIGNAL ;
    SHAPE ABUTMENT ;
    PORT
      LAYER metal3 ;
      RECT 822.045 1516.200 822.115 1516.270 ;
    END
  END r0_rd_out[378]
  PIN r0_rd_out[379]
    DIRECTION OUTPUT ;
    USE SIGNAL ;
    SHAPE ABUTMENT ;
    PORT
      LAYER metal3 ;
      RECT 822.185 1516.200 822.255 1516.270 ;
    END
  END r0_rd_out[379]
  PIN r0_rd_out[380]
    DIRECTION OUTPUT ;
    USE SIGNAL ;
    SHAPE ABUTMENT ;
    PORT
      LAYER metal3 ;
      RECT 822.325 1516.200 822.395 1516.270 ;
    END
  END r0_rd_out[380]
  PIN r0_rd_out[381]
    DIRECTION OUTPUT ;
    USE SIGNAL ;
    SHAPE ABUTMENT ;
    PORT
      LAYER metal3 ;
      RECT 822.465 1516.200 822.535 1516.270 ;
    END
  END r0_rd_out[381]
  PIN r0_rd_out[382]
    DIRECTION OUTPUT ;
    USE SIGNAL ;
    SHAPE ABUTMENT ;
    PORT
      LAYER metal3 ;
      RECT 822.605 1516.200 822.675 1516.270 ;
    END
  END r0_rd_out[382]
  PIN r0_rd_out[383]
    DIRECTION OUTPUT ;
    USE SIGNAL ;
    SHAPE ABUTMENT ;
    PORT
      LAYER metal3 ;
      RECT 822.745 1516.200 822.815 1516.270 ;
    END
  END r0_rd_out[383]
  PIN r0_rd_out[384]
    DIRECTION OUTPUT ;
    USE SIGNAL ;
    SHAPE ABUTMENT ;
    PORT
      LAYER metal3 ;
      RECT 822.885 1516.200 822.955 1516.270 ;
    END
  END r0_rd_out[384]
  PIN r0_rd_out[385]
    DIRECTION OUTPUT ;
    USE SIGNAL ;
    SHAPE ABUTMENT ;
    PORT
      LAYER metal3 ;
      RECT 823.025 1516.200 823.095 1516.270 ;
    END
  END r0_rd_out[385]
  PIN r0_rd_out[386]
    DIRECTION OUTPUT ;
    USE SIGNAL ;
    SHAPE ABUTMENT ;
    PORT
      LAYER metal3 ;
      RECT 823.165 1516.200 823.235 1516.270 ;
    END
  END r0_rd_out[386]
  PIN r0_rd_out[387]
    DIRECTION OUTPUT ;
    USE SIGNAL ;
    SHAPE ABUTMENT ;
    PORT
      LAYER metal3 ;
      RECT 823.305 1516.200 823.375 1516.270 ;
    END
  END r0_rd_out[387]
  PIN r0_rd_out[388]
    DIRECTION OUTPUT ;
    USE SIGNAL ;
    SHAPE ABUTMENT ;
    PORT
      LAYER metal3 ;
      RECT 823.445 1516.200 823.515 1516.270 ;
    END
  END r0_rd_out[388]
  PIN r0_rd_out[389]
    DIRECTION OUTPUT ;
    USE SIGNAL ;
    SHAPE ABUTMENT ;
    PORT
      LAYER metal3 ;
      RECT 823.585 1516.200 823.655 1516.270 ;
    END
  END r0_rd_out[389]
  PIN r0_rd_out[390]
    DIRECTION OUTPUT ;
    USE SIGNAL ;
    SHAPE ABUTMENT ;
    PORT
      LAYER metal3 ;
      RECT 823.725 1516.200 823.795 1516.270 ;
    END
  END r0_rd_out[390]
  PIN r0_rd_out[391]
    DIRECTION OUTPUT ;
    USE SIGNAL ;
    SHAPE ABUTMENT ;
    PORT
      LAYER metal3 ;
      RECT 823.865 1516.200 823.935 1516.270 ;
    END
  END r0_rd_out[391]
  PIN r0_rd_out[392]
    DIRECTION OUTPUT ;
    USE SIGNAL ;
    SHAPE ABUTMENT ;
    PORT
      LAYER metal3 ;
      RECT 824.005 1516.200 824.075 1516.270 ;
    END
  END r0_rd_out[392]
  PIN r0_rd_out[393]
    DIRECTION OUTPUT ;
    USE SIGNAL ;
    SHAPE ABUTMENT ;
    PORT
      LAYER metal3 ;
      RECT 824.145 1516.200 824.215 1516.270 ;
    END
  END r0_rd_out[393]
  PIN r0_rd_out[394]
    DIRECTION OUTPUT ;
    USE SIGNAL ;
    SHAPE ABUTMENT ;
    PORT
      LAYER metal3 ;
      RECT 824.285 1516.200 824.355 1516.270 ;
    END
  END r0_rd_out[394]
  PIN r0_rd_out[395]
    DIRECTION OUTPUT ;
    USE SIGNAL ;
    SHAPE ABUTMENT ;
    PORT
      LAYER metal3 ;
      RECT 824.425 1516.200 824.495 1516.270 ;
    END
  END r0_rd_out[395]
  PIN r0_rd_out[396]
    DIRECTION OUTPUT ;
    USE SIGNAL ;
    SHAPE ABUTMENT ;
    PORT
      LAYER metal3 ;
      RECT 824.565 1516.200 824.635 1516.270 ;
    END
  END r0_rd_out[396]
  PIN r0_rd_out[397]
    DIRECTION OUTPUT ;
    USE SIGNAL ;
    SHAPE ABUTMENT ;
    PORT
      LAYER metal3 ;
      RECT 824.705 1516.200 824.775 1516.270 ;
    END
  END r0_rd_out[397]
  PIN r0_rd_out[398]
    DIRECTION OUTPUT ;
    USE SIGNAL ;
    SHAPE ABUTMENT ;
    PORT
      LAYER metal3 ;
      RECT 824.845 1516.200 824.915 1516.270 ;
    END
  END r0_rd_out[398]
  PIN r0_rd_out[399]
    DIRECTION OUTPUT ;
    USE SIGNAL ;
    SHAPE ABUTMENT ;
    PORT
      LAYER metal3 ;
      RECT 824.985 1516.200 825.055 1516.270 ;
    END
  END r0_rd_out[399]
  PIN r0_rd_out[400]
    DIRECTION OUTPUT ;
    USE SIGNAL ;
    SHAPE ABUTMENT ;
    PORT
      LAYER metal3 ;
      RECT 825.125 1516.200 825.195 1516.270 ;
    END
  END r0_rd_out[400]
  PIN r0_rd_out[401]
    DIRECTION OUTPUT ;
    USE SIGNAL ;
    SHAPE ABUTMENT ;
    PORT
      LAYER metal3 ;
      RECT 825.265 1516.200 825.335 1516.270 ;
    END
  END r0_rd_out[401]
  PIN r0_rd_out[402]
    DIRECTION OUTPUT ;
    USE SIGNAL ;
    SHAPE ABUTMENT ;
    PORT
      LAYER metal3 ;
      RECT 825.405 1516.200 825.475 1516.270 ;
    END
  END r0_rd_out[402]
  PIN r0_rd_out[403]
    DIRECTION OUTPUT ;
    USE SIGNAL ;
    SHAPE ABUTMENT ;
    PORT
      LAYER metal3 ;
      RECT 825.545 1516.200 825.615 1516.270 ;
    END
  END r0_rd_out[403]
  PIN r0_rd_out[404]
    DIRECTION OUTPUT ;
    USE SIGNAL ;
    SHAPE ABUTMENT ;
    PORT
      LAYER metal3 ;
      RECT 825.685 1516.200 825.755 1516.270 ;
    END
  END r0_rd_out[404]
  PIN r0_rd_out[405]
    DIRECTION OUTPUT ;
    USE SIGNAL ;
    SHAPE ABUTMENT ;
    PORT
      LAYER metal3 ;
      RECT 825.825 1516.200 825.895 1516.270 ;
    END
  END r0_rd_out[405]
  PIN r0_rd_out[406]
    DIRECTION OUTPUT ;
    USE SIGNAL ;
    SHAPE ABUTMENT ;
    PORT
      LAYER metal3 ;
      RECT 825.965 1516.200 826.035 1516.270 ;
    END
  END r0_rd_out[406]
  PIN r0_rd_out[407]
    DIRECTION OUTPUT ;
    USE SIGNAL ;
    SHAPE ABUTMENT ;
    PORT
      LAYER metal3 ;
      RECT 826.105 1516.200 826.175 1516.270 ;
    END
  END r0_rd_out[407]
  PIN r0_rd_out[408]
    DIRECTION OUTPUT ;
    USE SIGNAL ;
    SHAPE ABUTMENT ;
    PORT
      LAYER metal3 ;
      RECT 826.245 1516.200 826.315 1516.270 ;
    END
  END r0_rd_out[408]
  PIN r0_rd_out[409]
    DIRECTION OUTPUT ;
    USE SIGNAL ;
    SHAPE ABUTMENT ;
    PORT
      LAYER metal3 ;
      RECT 826.385 1516.200 826.455 1516.270 ;
    END
  END r0_rd_out[409]
  PIN r0_rd_out[410]
    DIRECTION OUTPUT ;
    USE SIGNAL ;
    SHAPE ABUTMENT ;
    PORT
      LAYER metal3 ;
      RECT 826.525 1516.200 826.595 1516.270 ;
    END
  END r0_rd_out[410]
  PIN r0_rd_out[411]
    DIRECTION OUTPUT ;
    USE SIGNAL ;
    SHAPE ABUTMENT ;
    PORT
      LAYER metal3 ;
      RECT 826.665 1516.200 826.735 1516.270 ;
    END
  END r0_rd_out[411]
  PIN r0_rd_out[412]
    DIRECTION OUTPUT ;
    USE SIGNAL ;
    SHAPE ABUTMENT ;
    PORT
      LAYER metal3 ;
      RECT 826.805 1516.200 826.875 1516.270 ;
    END
  END r0_rd_out[412]
  PIN r0_rd_out[413]
    DIRECTION OUTPUT ;
    USE SIGNAL ;
    SHAPE ABUTMENT ;
    PORT
      LAYER metal3 ;
      RECT 826.945 1516.200 827.015 1516.270 ;
    END
  END r0_rd_out[413]
  PIN r0_rd_out[414]
    DIRECTION OUTPUT ;
    USE SIGNAL ;
    SHAPE ABUTMENT ;
    PORT
      LAYER metal3 ;
      RECT 827.085 1516.200 827.155 1516.270 ;
    END
  END r0_rd_out[414]
  PIN r0_rd_out[415]
    DIRECTION OUTPUT ;
    USE SIGNAL ;
    SHAPE ABUTMENT ;
    PORT
      LAYER metal3 ;
      RECT 827.225 1516.200 827.295 1516.270 ;
    END
  END r0_rd_out[415]
  PIN r0_rd_out[416]
    DIRECTION OUTPUT ;
    USE SIGNAL ;
    SHAPE ABUTMENT ;
    PORT
      LAYER metal3 ;
      RECT 827.365 1516.200 827.435 1516.270 ;
    END
  END r0_rd_out[416]
  PIN r0_rd_out[417]
    DIRECTION OUTPUT ;
    USE SIGNAL ;
    SHAPE ABUTMENT ;
    PORT
      LAYER metal3 ;
      RECT 827.505 1516.200 827.575 1516.270 ;
    END
  END r0_rd_out[417]
  PIN r0_rd_out[418]
    DIRECTION OUTPUT ;
    USE SIGNAL ;
    SHAPE ABUTMENT ;
    PORT
      LAYER metal3 ;
      RECT 827.645 1516.200 827.715 1516.270 ;
    END
  END r0_rd_out[418]
  PIN r0_rd_out[419]
    DIRECTION OUTPUT ;
    USE SIGNAL ;
    SHAPE ABUTMENT ;
    PORT
      LAYER metal3 ;
      RECT 827.785 1516.200 827.855 1516.270 ;
    END
  END r0_rd_out[419]
  PIN r0_rd_out[420]
    DIRECTION OUTPUT ;
    USE SIGNAL ;
    SHAPE ABUTMENT ;
    PORT
      LAYER metal3 ;
      RECT 827.925 1516.200 827.995 1516.270 ;
    END
  END r0_rd_out[420]
  PIN r0_rd_out[421]
    DIRECTION OUTPUT ;
    USE SIGNAL ;
    SHAPE ABUTMENT ;
    PORT
      LAYER metal3 ;
      RECT 828.065 1516.200 828.135 1516.270 ;
    END
  END r0_rd_out[421]
  PIN r0_rd_out[422]
    DIRECTION OUTPUT ;
    USE SIGNAL ;
    SHAPE ABUTMENT ;
    PORT
      LAYER metal3 ;
      RECT 828.205 1516.200 828.275 1516.270 ;
    END
  END r0_rd_out[422]
  PIN r0_rd_out[423]
    DIRECTION OUTPUT ;
    USE SIGNAL ;
    SHAPE ABUTMENT ;
    PORT
      LAYER metal3 ;
      RECT 828.345 1516.200 828.415 1516.270 ;
    END
  END r0_rd_out[423]
  PIN r0_rd_out[424]
    DIRECTION OUTPUT ;
    USE SIGNAL ;
    SHAPE ABUTMENT ;
    PORT
      LAYER metal3 ;
      RECT 828.485 1516.200 828.555 1516.270 ;
    END
  END r0_rd_out[424]
  PIN r0_rd_out[425]
    DIRECTION OUTPUT ;
    USE SIGNAL ;
    SHAPE ABUTMENT ;
    PORT
      LAYER metal3 ;
      RECT 828.625 1516.200 828.695 1516.270 ;
    END
  END r0_rd_out[425]
  PIN r0_rd_out[426]
    DIRECTION OUTPUT ;
    USE SIGNAL ;
    SHAPE ABUTMENT ;
    PORT
      LAYER metal3 ;
      RECT 828.765 1516.200 828.835 1516.270 ;
    END
  END r0_rd_out[426]
  PIN r0_rd_out[427]
    DIRECTION OUTPUT ;
    USE SIGNAL ;
    SHAPE ABUTMENT ;
    PORT
      LAYER metal3 ;
      RECT 828.905 1516.200 828.975 1516.270 ;
    END
  END r0_rd_out[427]
  PIN r0_rd_out[428]
    DIRECTION OUTPUT ;
    USE SIGNAL ;
    SHAPE ABUTMENT ;
    PORT
      LAYER metal3 ;
      RECT 829.045 1516.200 829.115 1516.270 ;
    END
  END r0_rd_out[428]
  PIN r0_rd_out[429]
    DIRECTION OUTPUT ;
    USE SIGNAL ;
    SHAPE ABUTMENT ;
    PORT
      LAYER metal3 ;
      RECT 829.185 1516.200 829.255 1516.270 ;
    END
  END r0_rd_out[429]
  PIN r0_rd_out[430]
    DIRECTION OUTPUT ;
    USE SIGNAL ;
    SHAPE ABUTMENT ;
    PORT
      LAYER metal3 ;
      RECT 829.325 1516.200 829.395 1516.270 ;
    END
  END r0_rd_out[430]
  PIN r0_rd_out[431]
    DIRECTION OUTPUT ;
    USE SIGNAL ;
    SHAPE ABUTMENT ;
    PORT
      LAYER metal3 ;
      RECT 829.465 1516.200 829.535 1516.270 ;
    END
  END r0_rd_out[431]
  PIN r0_rd_out[432]
    DIRECTION OUTPUT ;
    USE SIGNAL ;
    SHAPE ABUTMENT ;
    PORT
      LAYER metal3 ;
      RECT 829.605 1516.200 829.675 1516.270 ;
    END
  END r0_rd_out[432]
  PIN r0_rd_out[433]
    DIRECTION OUTPUT ;
    USE SIGNAL ;
    SHAPE ABUTMENT ;
    PORT
      LAYER metal3 ;
      RECT 829.745 1516.200 829.815 1516.270 ;
    END
  END r0_rd_out[433]
  PIN r0_rd_out[434]
    DIRECTION OUTPUT ;
    USE SIGNAL ;
    SHAPE ABUTMENT ;
    PORT
      LAYER metal3 ;
      RECT 829.885 1516.200 829.955 1516.270 ;
    END
  END r0_rd_out[434]
  PIN r0_rd_out[435]
    DIRECTION OUTPUT ;
    USE SIGNAL ;
    SHAPE ABUTMENT ;
    PORT
      LAYER metal3 ;
      RECT 830.025 1516.200 830.095 1516.270 ;
    END
  END r0_rd_out[435]
  PIN r0_rd_out[436]
    DIRECTION OUTPUT ;
    USE SIGNAL ;
    SHAPE ABUTMENT ;
    PORT
      LAYER metal3 ;
      RECT 830.165 1516.200 830.235 1516.270 ;
    END
  END r0_rd_out[436]
  PIN r0_rd_out[437]
    DIRECTION OUTPUT ;
    USE SIGNAL ;
    SHAPE ABUTMENT ;
    PORT
      LAYER metal3 ;
      RECT 830.305 1516.200 830.375 1516.270 ;
    END
  END r0_rd_out[437]
  PIN r0_rd_out[438]
    DIRECTION OUTPUT ;
    USE SIGNAL ;
    SHAPE ABUTMENT ;
    PORT
      LAYER metal3 ;
      RECT 830.445 1516.200 830.515 1516.270 ;
    END
  END r0_rd_out[438]
  PIN r0_rd_out[439]
    DIRECTION OUTPUT ;
    USE SIGNAL ;
    SHAPE ABUTMENT ;
    PORT
      LAYER metal3 ;
      RECT 830.585 1516.200 830.655 1516.270 ;
    END
  END r0_rd_out[439]
  PIN r0_rd_out[440]
    DIRECTION OUTPUT ;
    USE SIGNAL ;
    SHAPE ABUTMENT ;
    PORT
      LAYER metal3 ;
      RECT 830.725 1516.200 830.795 1516.270 ;
    END
  END r0_rd_out[440]
  PIN r0_rd_out[441]
    DIRECTION OUTPUT ;
    USE SIGNAL ;
    SHAPE ABUTMENT ;
    PORT
      LAYER metal3 ;
      RECT 830.865 1516.200 830.935 1516.270 ;
    END
  END r0_rd_out[441]
  PIN r0_rd_out[442]
    DIRECTION OUTPUT ;
    USE SIGNAL ;
    SHAPE ABUTMENT ;
    PORT
      LAYER metal3 ;
      RECT 831.005 1516.200 831.075 1516.270 ;
    END
  END r0_rd_out[442]
  PIN r0_rd_out[443]
    DIRECTION OUTPUT ;
    USE SIGNAL ;
    SHAPE ABUTMENT ;
    PORT
      LAYER metal3 ;
      RECT 831.145 1516.200 831.215 1516.270 ;
    END
  END r0_rd_out[443]
  PIN r0_rd_out[444]
    DIRECTION OUTPUT ;
    USE SIGNAL ;
    SHAPE ABUTMENT ;
    PORT
      LAYER metal3 ;
      RECT 831.285 1516.200 831.355 1516.270 ;
    END
  END r0_rd_out[444]
  PIN r0_rd_out[445]
    DIRECTION OUTPUT ;
    USE SIGNAL ;
    SHAPE ABUTMENT ;
    PORT
      LAYER metal3 ;
      RECT 831.425 1516.200 831.495 1516.270 ;
    END
  END r0_rd_out[445]
  PIN r0_rd_out[446]
    DIRECTION OUTPUT ;
    USE SIGNAL ;
    SHAPE ABUTMENT ;
    PORT
      LAYER metal3 ;
      RECT 831.565 1516.200 831.635 1516.270 ;
    END
  END r0_rd_out[446]
  PIN r0_rd_out[447]
    DIRECTION OUTPUT ;
    USE SIGNAL ;
    SHAPE ABUTMENT ;
    PORT
      LAYER metal3 ;
      RECT 831.705 1516.200 831.775 1516.270 ;
    END
  END r0_rd_out[447]
  PIN r0_rd_out[448]
    DIRECTION OUTPUT ;
    USE SIGNAL ;
    SHAPE ABUTMENT ;
    PORT
      LAYER metal3 ;
      RECT 831.845 1516.200 831.915 1516.270 ;
    END
  END r0_rd_out[448]
  PIN r0_rd_out[449]
    DIRECTION OUTPUT ;
    USE SIGNAL ;
    SHAPE ABUTMENT ;
    PORT
      LAYER metal3 ;
      RECT 831.985 1516.200 832.055 1516.270 ;
    END
  END r0_rd_out[449]
  PIN r0_rd_out[450]
    DIRECTION OUTPUT ;
    USE SIGNAL ;
    SHAPE ABUTMENT ;
    PORT
      LAYER metal3 ;
      RECT 832.125 1516.200 832.195 1516.270 ;
    END
  END r0_rd_out[450]
  PIN r0_rd_out[451]
    DIRECTION OUTPUT ;
    USE SIGNAL ;
    SHAPE ABUTMENT ;
    PORT
      LAYER metal3 ;
      RECT 832.265 1516.200 832.335 1516.270 ;
    END
  END r0_rd_out[451]
  PIN r0_rd_out[452]
    DIRECTION OUTPUT ;
    USE SIGNAL ;
    SHAPE ABUTMENT ;
    PORT
      LAYER metal3 ;
      RECT 832.405 1516.200 832.475 1516.270 ;
    END
  END r0_rd_out[452]
  PIN r0_rd_out[453]
    DIRECTION OUTPUT ;
    USE SIGNAL ;
    SHAPE ABUTMENT ;
    PORT
      LAYER metal3 ;
      RECT 832.545 1516.200 832.615 1516.270 ;
    END
  END r0_rd_out[453]
  PIN r0_rd_out[454]
    DIRECTION OUTPUT ;
    USE SIGNAL ;
    SHAPE ABUTMENT ;
    PORT
      LAYER metal3 ;
      RECT 832.685 1516.200 832.755 1516.270 ;
    END
  END r0_rd_out[454]
  PIN r0_rd_out[455]
    DIRECTION OUTPUT ;
    USE SIGNAL ;
    SHAPE ABUTMENT ;
    PORT
      LAYER metal3 ;
      RECT 832.825 1516.200 832.895 1516.270 ;
    END
  END r0_rd_out[455]
  PIN r0_rd_out[456]
    DIRECTION OUTPUT ;
    USE SIGNAL ;
    SHAPE ABUTMENT ;
    PORT
      LAYER metal3 ;
      RECT 832.965 1516.200 833.035 1516.270 ;
    END
  END r0_rd_out[456]
  PIN r0_rd_out[457]
    DIRECTION OUTPUT ;
    USE SIGNAL ;
    SHAPE ABUTMENT ;
    PORT
      LAYER metal3 ;
      RECT 833.105 1516.200 833.175 1516.270 ;
    END
  END r0_rd_out[457]
  PIN r0_rd_out[458]
    DIRECTION OUTPUT ;
    USE SIGNAL ;
    SHAPE ABUTMENT ;
    PORT
      LAYER metal3 ;
      RECT 833.245 1516.200 833.315 1516.270 ;
    END
  END r0_rd_out[458]
  PIN r0_rd_out[459]
    DIRECTION OUTPUT ;
    USE SIGNAL ;
    SHAPE ABUTMENT ;
    PORT
      LAYER metal3 ;
      RECT 833.385 1516.200 833.455 1516.270 ;
    END
  END r0_rd_out[459]
  PIN r0_rd_out[460]
    DIRECTION OUTPUT ;
    USE SIGNAL ;
    SHAPE ABUTMENT ;
    PORT
      LAYER metal3 ;
      RECT 833.525 1516.200 833.595 1516.270 ;
    END
  END r0_rd_out[460]
  PIN r0_rd_out[461]
    DIRECTION OUTPUT ;
    USE SIGNAL ;
    SHAPE ABUTMENT ;
    PORT
      LAYER metal3 ;
      RECT 833.665 1516.200 833.735 1516.270 ;
    END
  END r0_rd_out[461]
  PIN r0_rd_out[462]
    DIRECTION OUTPUT ;
    USE SIGNAL ;
    SHAPE ABUTMENT ;
    PORT
      LAYER metal3 ;
      RECT 833.805 1516.200 833.875 1516.270 ;
    END
  END r0_rd_out[462]
  PIN r0_rd_out[463]
    DIRECTION OUTPUT ;
    USE SIGNAL ;
    SHAPE ABUTMENT ;
    PORT
      LAYER metal3 ;
      RECT 833.945 1516.200 834.015 1516.270 ;
    END
  END r0_rd_out[463]
  PIN r0_rd_out[464]
    DIRECTION OUTPUT ;
    USE SIGNAL ;
    SHAPE ABUTMENT ;
    PORT
      LAYER metal3 ;
      RECT 834.085 1516.200 834.155 1516.270 ;
    END
  END r0_rd_out[464]
  PIN r0_rd_out[465]
    DIRECTION OUTPUT ;
    USE SIGNAL ;
    SHAPE ABUTMENT ;
    PORT
      LAYER metal3 ;
      RECT 834.225 1516.200 834.295 1516.270 ;
    END
  END r0_rd_out[465]
  PIN r0_rd_out[466]
    DIRECTION OUTPUT ;
    USE SIGNAL ;
    SHAPE ABUTMENT ;
    PORT
      LAYER metal3 ;
      RECT 834.365 1516.200 834.435 1516.270 ;
    END
  END r0_rd_out[466]
  PIN r0_rd_out[467]
    DIRECTION OUTPUT ;
    USE SIGNAL ;
    SHAPE ABUTMENT ;
    PORT
      LAYER metal3 ;
      RECT 834.505 1516.200 834.575 1516.270 ;
    END
  END r0_rd_out[467]
  PIN r0_rd_out[468]
    DIRECTION OUTPUT ;
    USE SIGNAL ;
    SHAPE ABUTMENT ;
    PORT
      LAYER metal3 ;
      RECT 834.645 1516.200 834.715 1516.270 ;
    END
  END r0_rd_out[468]
  PIN r0_rd_out[469]
    DIRECTION OUTPUT ;
    USE SIGNAL ;
    SHAPE ABUTMENT ;
    PORT
      LAYER metal3 ;
      RECT 834.785 1516.200 834.855 1516.270 ;
    END
  END r0_rd_out[469]
  PIN r0_rd_out[470]
    DIRECTION OUTPUT ;
    USE SIGNAL ;
    SHAPE ABUTMENT ;
    PORT
      LAYER metal3 ;
      RECT 834.925 1516.200 834.995 1516.270 ;
    END
  END r0_rd_out[470]
  PIN r0_rd_out[471]
    DIRECTION OUTPUT ;
    USE SIGNAL ;
    SHAPE ABUTMENT ;
    PORT
      LAYER metal3 ;
      RECT 835.065 1516.200 835.135 1516.270 ;
    END
  END r0_rd_out[471]
  PIN r0_rd_out[472]
    DIRECTION OUTPUT ;
    USE SIGNAL ;
    SHAPE ABUTMENT ;
    PORT
      LAYER metal3 ;
      RECT 835.205 1516.200 835.275 1516.270 ;
    END
  END r0_rd_out[472]
  PIN r0_rd_out[473]
    DIRECTION OUTPUT ;
    USE SIGNAL ;
    SHAPE ABUTMENT ;
    PORT
      LAYER metal3 ;
      RECT 835.345 1516.200 835.415 1516.270 ;
    END
  END r0_rd_out[473]
  PIN r0_rd_out[474]
    DIRECTION OUTPUT ;
    USE SIGNAL ;
    SHAPE ABUTMENT ;
    PORT
      LAYER metal3 ;
      RECT 835.485 1516.200 835.555 1516.270 ;
    END
  END r0_rd_out[474]
  PIN r0_rd_out[475]
    DIRECTION OUTPUT ;
    USE SIGNAL ;
    SHAPE ABUTMENT ;
    PORT
      LAYER metal3 ;
      RECT 835.625 1516.200 835.695 1516.270 ;
    END
  END r0_rd_out[475]
  PIN r0_rd_out[476]
    DIRECTION OUTPUT ;
    USE SIGNAL ;
    SHAPE ABUTMENT ;
    PORT
      LAYER metal3 ;
      RECT 835.765 1516.200 835.835 1516.270 ;
    END
  END r0_rd_out[476]
  PIN r0_rd_out[477]
    DIRECTION OUTPUT ;
    USE SIGNAL ;
    SHAPE ABUTMENT ;
    PORT
      LAYER metal3 ;
      RECT 835.905 1516.200 835.975 1516.270 ;
    END
  END r0_rd_out[477]
  PIN r0_rd_out[478]
    DIRECTION OUTPUT ;
    USE SIGNAL ;
    SHAPE ABUTMENT ;
    PORT
      LAYER metal3 ;
      RECT 836.045 1516.200 836.115 1516.270 ;
    END
  END r0_rd_out[478]
  PIN r0_rd_out[479]
    DIRECTION OUTPUT ;
    USE SIGNAL ;
    SHAPE ABUTMENT ;
    PORT
      LAYER metal3 ;
      RECT 836.185 1516.200 836.255 1516.270 ;
    END
  END r0_rd_out[479]
  PIN r0_rd_out[480]
    DIRECTION OUTPUT ;
    USE SIGNAL ;
    SHAPE ABUTMENT ;
    PORT
      LAYER metal3 ;
      RECT 836.325 1516.200 836.395 1516.270 ;
    END
  END r0_rd_out[480]
  PIN r0_rd_out[481]
    DIRECTION OUTPUT ;
    USE SIGNAL ;
    SHAPE ABUTMENT ;
    PORT
      LAYER metal3 ;
      RECT 836.465 1516.200 836.535 1516.270 ;
    END
  END r0_rd_out[481]
  PIN r0_rd_out[482]
    DIRECTION OUTPUT ;
    USE SIGNAL ;
    SHAPE ABUTMENT ;
    PORT
      LAYER metal3 ;
      RECT 836.605 1516.200 836.675 1516.270 ;
    END
  END r0_rd_out[482]
  PIN r0_rd_out[483]
    DIRECTION OUTPUT ;
    USE SIGNAL ;
    SHAPE ABUTMENT ;
    PORT
      LAYER metal3 ;
      RECT 836.745 1516.200 836.815 1516.270 ;
    END
  END r0_rd_out[483]
  PIN r0_rd_out[484]
    DIRECTION OUTPUT ;
    USE SIGNAL ;
    SHAPE ABUTMENT ;
    PORT
      LAYER metal3 ;
      RECT 836.885 1516.200 836.955 1516.270 ;
    END
  END r0_rd_out[484]
  PIN r0_rd_out[485]
    DIRECTION OUTPUT ;
    USE SIGNAL ;
    SHAPE ABUTMENT ;
    PORT
      LAYER metal3 ;
      RECT 837.025 1516.200 837.095 1516.270 ;
    END
  END r0_rd_out[485]
  PIN r0_rd_out[486]
    DIRECTION OUTPUT ;
    USE SIGNAL ;
    SHAPE ABUTMENT ;
    PORT
      LAYER metal3 ;
      RECT 837.165 1516.200 837.235 1516.270 ;
    END
  END r0_rd_out[486]
  PIN r0_rd_out[487]
    DIRECTION OUTPUT ;
    USE SIGNAL ;
    SHAPE ABUTMENT ;
    PORT
      LAYER metal3 ;
      RECT 837.305 1516.200 837.375 1516.270 ;
    END
  END r0_rd_out[487]
  PIN r0_rd_out[488]
    DIRECTION OUTPUT ;
    USE SIGNAL ;
    SHAPE ABUTMENT ;
    PORT
      LAYER metal3 ;
      RECT 837.445 1516.200 837.515 1516.270 ;
    END
  END r0_rd_out[488]
  PIN r0_rd_out[489]
    DIRECTION OUTPUT ;
    USE SIGNAL ;
    SHAPE ABUTMENT ;
    PORT
      LAYER metal3 ;
      RECT 837.585 1516.200 837.655 1516.270 ;
    END
  END r0_rd_out[489]
  PIN r0_rd_out[490]
    DIRECTION OUTPUT ;
    USE SIGNAL ;
    SHAPE ABUTMENT ;
    PORT
      LAYER metal3 ;
      RECT 837.725 1516.200 837.795 1516.270 ;
    END
  END r0_rd_out[490]
  PIN r0_rd_out[491]
    DIRECTION OUTPUT ;
    USE SIGNAL ;
    SHAPE ABUTMENT ;
    PORT
      LAYER metal3 ;
      RECT 837.865 1516.200 837.935 1516.270 ;
    END
  END r0_rd_out[491]
  PIN r0_rd_out[492]
    DIRECTION OUTPUT ;
    USE SIGNAL ;
    SHAPE ABUTMENT ;
    PORT
      LAYER metal3 ;
      RECT 838.005 1516.200 838.075 1516.270 ;
    END
  END r0_rd_out[492]
  PIN r0_rd_out[493]
    DIRECTION OUTPUT ;
    USE SIGNAL ;
    SHAPE ABUTMENT ;
    PORT
      LAYER metal3 ;
      RECT 838.145 1516.200 838.215 1516.270 ;
    END
  END r0_rd_out[493]
  PIN r0_rd_out[494]
    DIRECTION OUTPUT ;
    USE SIGNAL ;
    SHAPE ABUTMENT ;
    PORT
      LAYER metal3 ;
      RECT 838.285 1516.200 838.355 1516.270 ;
    END
  END r0_rd_out[494]
  PIN r0_rd_out[495]
    DIRECTION OUTPUT ;
    USE SIGNAL ;
    SHAPE ABUTMENT ;
    PORT
      LAYER metal3 ;
      RECT 838.425 1516.200 838.495 1516.270 ;
    END
  END r0_rd_out[495]
  PIN r0_rd_out[496]
    DIRECTION OUTPUT ;
    USE SIGNAL ;
    SHAPE ABUTMENT ;
    PORT
      LAYER metal3 ;
      RECT 838.565 1516.200 838.635 1516.270 ;
    END
  END r0_rd_out[496]
  PIN r0_rd_out[497]
    DIRECTION OUTPUT ;
    USE SIGNAL ;
    SHAPE ABUTMENT ;
    PORT
      LAYER metal3 ;
      RECT 838.705 1516.200 838.775 1516.270 ;
    END
  END r0_rd_out[497]
  PIN r0_rd_out[498]
    DIRECTION OUTPUT ;
    USE SIGNAL ;
    SHAPE ABUTMENT ;
    PORT
      LAYER metal3 ;
      RECT 838.845 1516.200 838.915 1516.270 ;
    END
  END r0_rd_out[498]
  PIN r0_rd_out[499]
    DIRECTION OUTPUT ;
    USE SIGNAL ;
    SHAPE ABUTMENT ;
    PORT
      LAYER metal3 ;
      RECT 838.985 1516.200 839.055 1516.270 ;
    END
  END r0_rd_out[499]
  PIN r0_rd_out[500]
    DIRECTION OUTPUT ;
    USE SIGNAL ;
    SHAPE ABUTMENT ;
    PORT
      LAYER metal3 ;
      RECT 839.125 1516.200 839.195 1516.270 ;
    END
  END r0_rd_out[500]
  PIN r0_rd_out[501]
    DIRECTION OUTPUT ;
    USE SIGNAL ;
    SHAPE ABUTMENT ;
    PORT
      LAYER metal3 ;
      RECT 839.265 1516.200 839.335 1516.270 ;
    END
  END r0_rd_out[501]
  PIN r0_rd_out[502]
    DIRECTION OUTPUT ;
    USE SIGNAL ;
    SHAPE ABUTMENT ;
    PORT
      LAYER metal3 ;
      RECT 839.405 1516.200 839.475 1516.270 ;
    END
  END r0_rd_out[502]
  PIN r0_rd_out[503]
    DIRECTION OUTPUT ;
    USE SIGNAL ;
    SHAPE ABUTMENT ;
    PORT
      LAYER metal3 ;
      RECT 839.545 1516.200 839.615 1516.270 ;
    END
  END r0_rd_out[503]
  PIN r0_rd_out[504]
    DIRECTION OUTPUT ;
    USE SIGNAL ;
    SHAPE ABUTMENT ;
    PORT
      LAYER metal3 ;
      RECT 839.685 1516.200 839.755 1516.270 ;
    END
  END r0_rd_out[504]
  PIN r0_rd_out[505]
    DIRECTION OUTPUT ;
    USE SIGNAL ;
    SHAPE ABUTMENT ;
    PORT
      LAYER metal3 ;
      RECT 839.825 1516.200 839.895 1516.270 ;
    END
  END r0_rd_out[505]
  PIN r0_rd_out[506]
    DIRECTION OUTPUT ;
    USE SIGNAL ;
    SHAPE ABUTMENT ;
    PORT
      LAYER metal3 ;
      RECT 839.965 1516.200 840.035 1516.270 ;
    END
  END r0_rd_out[506]
  PIN r0_rd_out[507]
    DIRECTION OUTPUT ;
    USE SIGNAL ;
    SHAPE ABUTMENT ;
    PORT
      LAYER metal3 ;
      RECT 840.105 1516.200 840.175 1516.270 ;
    END
  END r0_rd_out[507]
  PIN r0_rd_out[508]
    DIRECTION OUTPUT ;
    USE SIGNAL ;
    SHAPE ABUTMENT ;
    PORT
      LAYER metal3 ;
      RECT 840.245 1516.200 840.315 1516.270 ;
    END
  END r0_rd_out[508]
  PIN r0_rd_out[509]
    DIRECTION OUTPUT ;
    USE SIGNAL ;
    SHAPE ABUTMENT ;
    PORT
      LAYER metal3 ;
      RECT 840.385 1516.200 840.455 1516.270 ;
    END
  END r0_rd_out[509]
  PIN r0_rd_out[510]
    DIRECTION OUTPUT ;
    USE SIGNAL ;
    SHAPE ABUTMENT ;
    PORT
      LAYER metal3 ;
      RECT 840.525 1516.200 840.595 1516.270 ;
    END
  END r0_rd_out[510]
  PIN r0_rd_out[511]
    DIRECTION OUTPUT ;
    USE SIGNAL ;
    SHAPE ABUTMENT ;
    PORT
      LAYER metal3 ;
      RECT 840.665 1516.200 840.735 1516.270 ;
    END
  END r0_rd_out[511]
  PIN w0_addr_in[0]
    DIRECTION INPUT ;
    USE SIGNAL ;
    SHAPE ABUTMENT ;
    PORT
      LAYER metal3 ;
      RECT 1610.210 757.120 1610.280 757.190 ;
    END
  END w0_addr_in[0]
  PIN w0_addr_in[1]
    DIRECTION INPUT ;
    USE SIGNAL ;
    SHAPE ABUTMENT ;
    PORT
      LAYER metal3 ;
      RECT 1610.210 757.260 1610.280 757.330 ;
    END
  END w0_addr_in[1]
  PIN w0_addr_in[2]
    DIRECTION INPUT ;
    USE SIGNAL ;
    SHAPE ABUTMENT ;
    PORT
      LAYER metal3 ;
      RECT 1610.210 757.400 1610.280 757.470 ;
    END
  END w0_addr_in[2]
  PIN w0_addr_in[3]
    DIRECTION INPUT ;
    USE SIGNAL ;
    SHAPE ABUTMENT ;
    PORT
      LAYER metal3 ;
      RECT 1610.210 757.540 1610.280 757.610 ;
    END
  END w0_addr_in[3]
  PIN w0_addr_in[4]
    DIRECTION INPUT ;
    USE SIGNAL ;
    SHAPE ABUTMENT ;
    PORT
      LAYER metal3 ;
      RECT 1610.210 757.680 1610.280 757.750 ;
    END
  END w0_addr_in[4]
  PIN w0_addr_in[5]
    DIRECTION INPUT ;
    USE SIGNAL ;
    SHAPE ABUTMENT ;
    PORT
      LAYER metal3 ;
      RECT 1610.210 757.820 1610.280 757.890 ;
    END
  END w0_addr_in[5]
  PIN w0_addr_in[6]
    DIRECTION INPUT ;
    USE SIGNAL ;
    SHAPE ABUTMENT ;
    PORT
      LAYER metal3 ;
      RECT 1610.210 757.960 1610.280 758.030 ;
    END
  END w0_addr_in[6]
  PIN w0_addr_in[7]
    DIRECTION INPUT ;
    USE SIGNAL ;
    SHAPE ABUTMENT ;
    PORT
      LAYER metal3 ;
      RECT 1610.210 758.100 1610.280 758.170 ;
    END
  END w0_addr_in[7]
  PIN w0_addr_in[8]
    DIRECTION INPUT ;
    USE SIGNAL ;
    SHAPE ABUTMENT ;
    PORT
      LAYER metal3 ;
      RECT 1610.210 758.240 1610.280 758.310 ;
    END
  END w0_addr_in[8]
  PIN w0_addr_in[9]
    DIRECTION INPUT ;
    USE SIGNAL ;
    SHAPE ABUTMENT ;
    PORT
      LAYER metal3 ;
      RECT 1610.210 758.380 1610.280 758.450 ;
    END
  END w0_addr_in[9]
  PIN w0_addr_in[10]
    DIRECTION INPUT ;
    USE SIGNAL ;
    SHAPE ABUTMENT ;
    PORT
      LAYER metal3 ;
      RECT 1610.210 758.520 1610.280 758.590 ;
    END
  END w0_addr_in[10]
  PIN w0_we_in
    DIRECTION INPUT ;
    USE SIGNAL ;
    SHAPE ABUTMENT ;
    PORT
      LAYER metal3 ;
      RECT 1610.210 758.800 1610.280 758.870 ;
    END
  END w0_we_in
  PIN w0_ce_in
    DIRECTION INPUT ;
    USE SIGNAL ;
    SHAPE ABUTMENT ;
    PORT
      LAYER metal3 ;
      RECT 1610.210 758.940 1610.280 759.010 ;
    END
  END w0_ce_in
  PIN w0_clk
    DIRECTION INPUT ;
    USE SIGNAL ;
    SHAPE ABUTMENT ;
    PORT
      LAYER metal3 ;
      RECT 1610.210 759.080 1610.280 759.150 ;
    END
  END w0_clk
  PIN w0_wd_in[0]
    DIRECTION INPUT ;
    USE SIGNAL ;
    SHAPE ABUTMENT ;
    PORT
      LAYER metal3 ;
      RECT 769.125 0.000 769.195 0.070 ;
    END
  END w0_wd_in[0]
  PIN w0_wd_in[1]
    DIRECTION INPUT ;
    USE SIGNAL ;
    SHAPE ABUTMENT ;
    PORT
      LAYER metal3 ;
      RECT 769.265 0.000 769.335 0.070 ;
    END
  END w0_wd_in[1]
  PIN w0_wd_in[2]
    DIRECTION INPUT ;
    USE SIGNAL ;
    SHAPE ABUTMENT ;
    PORT
      LAYER metal3 ;
      RECT 769.405 0.000 769.475 0.070 ;
    END
  END w0_wd_in[2]
  PIN w0_wd_in[3]
    DIRECTION INPUT ;
    USE SIGNAL ;
    SHAPE ABUTMENT ;
    PORT
      LAYER metal3 ;
      RECT 769.545 0.000 769.615 0.070 ;
    END
  END w0_wd_in[3]
  PIN w0_wd_in[4]
    DIRECTION INPUT ;
    USE SIGNAL ;
    SHAPE ABUTMENT ;
    PORT
      LAYER metal3 ;
      RECT 769.685 0.000 769.755 0.070 ;
    END
  END w0_wd_in[4]
  PIN w0_wd_in[5]
    DIRECTION INPUT ;
    USE SIGNAL ;
    SHAPE ABUTMENT ;
    PORT
      LAYER metal3 ;
      RECT 769.825 0.000 769.895 0.070 ;
    END
  END w0_wd_in[5]
  PIN w0_wd_in[6]
    DIRECTION INPUT ;
    USE SIGNAL ;
    SHAPE ABUTMENT ;
    PORT
      LAYER metal3 ;
      RECT 769.965 0.000 770.035 0.070 ;
    END
  END w0_wd_in[6]
  PIN w0_wd_in[7]
    DIRECTION INPUT ;
    USE SIGNAL ;
    SHAPE ABUTMENT ;
    PORT
      LAYER metal3 ;
      RECT 770.105 0.000 770.175 0.070 ;
    END
  END w0_wd_in[7]
  PIN w0_wd_in[8]
    DIRECTION INPUT ;
    USE SIGNAL ;
    SHAPE ABUTMENT ;
    PORT
      LAYER metal3 ;
      RECT 770.245 0.000 770.315 0.070 ;
    END
  END w0_wd_in[8]
  PIN w0_wd_in[9]
    DIRECTION INPUT ;
    USE SIGNAL ;
    SHAPE ABUTMENT ;
    PORT
      LAYER metal3 ;
      RECT 770.385 0.000 770.455 0.070 ;
    END
  END w0_wd_in[9]
  PIN w0_wd_in[10]
    DIRECTION INPUT ;
    USE SIGNAL ;
    SHAPE ABUTMENT ;
    PORT
      LAYER metal3 ;
      RECT 770.525 0.000 770.595 0.070 ;
    END
  END w0_wd_in[10]
  PIN w0_wd_in[11]
    DIRECTION INPUT ;
    USE SIGNAL ;
    SHAPE ABUTMENT ;
    PORT
      LAYER metal3 ;
      RECT 770.665 0.000 770.735 0.070 ;
    END
  END w0_wd_in[11]
  PIN w0_wd_in[12]
    DIRECTION INPUT ;
    USE SIGNAL ;
    SHAPE ABUTMENT ;
    PORT
      LAYER metal3 ;
      RECT 770.805 0.000 770.875 0.070 ;
    END
  END w0_wd_in[12]
  PIN w0_wd_in[13]
    DIRECTION INPUT ;
    USE SIGNAL ;
    SHAPE ABUTMENT ;
    PORT
      LAYER metal3 ;
      RECT 770.945 0.000 771.015 0.070 ;
    END
  END w0_wd_in[13]
  PIN w0_wd_in[14]
    DIRECTION INPUT ;
    USE SIGNAL ;
    SHAPE ABUTMENT ;
    PORT
      LAYER metal3 ;
      RECT 771.085 0.000 771.155 0.070 ;
    END
  END w0_wd_in[14]
  PIN w0_wd_in[15]
    DIRECTION INPUT ;
    USE SIGNAL ;
    SHAPE ABUTMENT ;
    PORT
      LAYER metal3 ;
      RECT 771.225 0.000 771.295 0.070 ;
    END
  END w0_wd_in[15]
  PIN w0_wd_in[16]
    DIRECTION INPUT ;
    USE SIGNAL ;
    SHAPE ABUTMENT ;
    PORT
      LAYER metal3 ;
      RECT 771.365 0.000 771.435 0.070 ;
    END
  END w0_wd_in[16]
  PIN w0_wd_in[17]
    DIRECTION INPUT ;
    USE SIGNAL ;
    SHAPE ABUTMENT ;
    PORT
      LAYER metal3 ;
      RECT 771.505 0.000 771.575 0.070 ;
    END
  END w0_wd_in[17]
  PIN w0_wd_in[18]
    DIRECTION INPUT ;
    USE SIGNAL ;
    SHAPE ABUTMENT ;
    PORT
      LAYER metal3 ;
      RECT 771.645 0.000 771.715 0.070 ;
    END
  END w0_wd_in[18]
  PIN w0_wd_in[19]
    DIRECTION INPUT ;
    USE SIGNAL ;
    SHAPE ABUTMENT ;
    PORT
      LAYER metal3 ;
      RECT 771.785 0.000 771.855 0.070 ;
    END
  END w0_wd_in[19]
  PIN w0_wd_in[20]
    DIRECTION INPUT ;
    USE SIGNAL ;
    SHAPE ABUTMENT ;
    PORT
      LAYER metal3 ;
      RECT 771.925 0.000 771.995 0.070 ;
    END
  END w0_wd_in[20]
  PIN w0_wd_in[21]
    DIRECTION INPUT ;
    USE SIGNAL ;
    SHAPE ABUTMENT ;
    PORT
      LAYER metal3 ;
      RECT 772.065 0.000 772.135 0.070 ;
    END
  END w0_wd_in[21]
  PIN w0_wd_in[22]
    DIRECTION INPUT ;
    USE SIGNAL ;
    SHAPE ABUTMENT ;
    PORT
      LAYER metal3 ;
      RECT 772.205 0.000 772.275 0.070 ;
    END
  END w0_wd_in[22]
  PIN w0_wd_in[23]
    DIRECTION INPUT ;
    USE SIGNAL ;
    SHAPE ABUTMENT ;
    PORT
      LAYER metal3 ;
      RECT 772.345 0.000 772.415 0.070 ;
    END
  END w0_wd_in[23]
  PIN w0_wd_in[24]
    DIRECTION INPUT ;
    USE SIGNAL ;
    SHAPE ABUTMENT ;
    PORT
      LAYER metal3 ;
      RECT 772.485 0.000 772.555 0.070 ;
    END
  END w0_wd_in[24]
  PIN w0_wd_in[25]
    DIRECTION INPUT ;
    USE SIGNAL ;
    SHAPE ABUTMENT ;
    PORT
      LAYER metal3 ;
      RECT 772.625 0.000 772.695 0.070 ;
    END
  END w0_wd_in[25]
  PIN w0_wd_in[26]
    DIRECTION INPUT ;
    USE SIGNAL ;
    SHAPE ABUTMENT ;
    PORT
      LAYER metal3 ;
      RECT 772.765 0.000 772.835 0.070 ;
    END
  END w0_wd_in[26]
  PIN w0_wd_in[27]
    DIRECTION INPUT ;
    USE SIGNAL ;
    SHAPE ABUTMENT ;
    PORT
      LAYER metal3 ;
      RECT 772.905 0.000 772.975 0.070 ;
    END
  END w0_wd_in[27]
  PIN w0_wd_in[28]
    DIRECTION INPUT ;
    USE SIGNAL ;
    SHAPE ABUTMENT ;
    PORT
      LAYER metal3 ;
      RECT 773.045 0.000 773.115 0.070 ;
    END
  END w0_wd_in[28]
  PIN w0_wd_in[29]
    DIRECTION INPUT ;
    USE SIGNAL ;
    SHAPE ABUTMENT ;
    PORT
      LAYER metal3 ;
      RECT 773.185 0.000 773.255 0.070 ;
    END
  END w0_wd_in[29]
  PIN w0_wd_in[30]
    DIRECTION INPUT ;
    USE SIGNAL ;
    SHAPE ABUTMENT ;
    PORT
      LAYER metal3 ;
      RECT 773.325 0.000 773.395 0.070 ;
    END
  END w0_wd_in[30]
  PIN w0_wd_in[31]
    DIRECTION INPUT ;
    USE SIGNAL ;
    SHAPE ABUTMENT ;
    PORT
      LAYER metal3 ;
      RECT 773.465 0.000 773.535 0.070 ;
    END
  END w0_wd_in[31]
  PIN w0_wd_in[32]
    DIRECTION INPUT ;
    USE SIGNAL ;
    SHAPE ABUTMENT ;
    PORT
      LAYER metal3 ;
      RECT 773.605 0.000 773.675 0.070 ;
    END
  END w0_wd_in[32]
  PIN w0_wd_in[33]
    DIRECTION INPUT ;
    USE SIGNAL ;
    SHAPE ABUTMENT ;
    PORT
      LAYER metal3 ;
      RECT 773.745 0.000 773.815 0.070 ;
    END
  END w0_wd_in[33]
  PIN w0_wd_in[34]
    DIRECTION INPUT ;
    USE SIGNAL ;
    SHAPE ABUTMENT ;
    PORT
      LAYER metal3 ;
      RECT 773.885 0.000 773.955 0.070 ;
    END
  END w0_wd_in[34]
  PIN w0_wd_in[35]
    DIRECTION INPUT ;
    USE SIGNAL ;
    SHAPE ABUTMENT ;
    PORT
      LAYER metal3 ;
      RECT 774.025 0.000 774.095 0.070 ;
    END
  END w0_wd_in[35]
  PIN w0_wd_in[36]
    DIRECTION INPUT ;
    USE SIGNAL ;
    SHAPE ABUTMENT ;
    PORT
      LAYER metal3 ;
      RECT 774.165 0.000 774.235 0.070 ;
    END
  END w0_wd_in[36]
  PIN w0_wd_in[37]
    DIRECTION INPUT ;
    USE SIGNAL ;
    SHAPE ABUTMENT ;
    PORT
      LAYER metal3 ;
      RECT 774.305 0.000 774.375 0.070 ;
    END
  END w0_wd_in[37]
  PIN w0_wd_in[38]
    DIRECTION INPUT ;
    USE SIGNAL ;
    SHAPE ABUTMENT ;
    PORT
      LAYER metal3 ;
      RECT 774.445 0.000 774.515 0.070 ;
    END
  END w0_wd_in[38]
  PIN w0_wd_in[39]
    DIRECTION INPUT ;
    USE SIGNAL ;
    SHAPE ABUTMENT ;
    PORT
      LAYER metal3 ;
      RECT 774.585 0.000 774.655 0.070 ;
    END
  END w0_wd_in[39]
  PIN w0_wd_in[40]
    DIRECTION INPUT ;
    USE SIGNAL ;
    SHAPE ABUTMENT ;
    PORT
      LAYER metal3 ;
      RECT 774.725 0.000 774.795 0.070 ;
    END
  END w0_wd_in[40]
  PIN w0_wd_in[41]
    DIRECTION INPUT ;
    USE SIGNAL ;
    SHAPE ABUTMENT ;
    PORT
      LAYER metal3 ;
      RECT 774.865 0.000 774.935 0.070 ;
    END
  END w0_wd_in[41]
  PIN w0_wd_in[42]
    DIRECTION INPUT ;
    USE SIGNAL ;
    SHAPE ABUTMENT ;
    PORT
      LAYER metal3 ;
      RECT 775.005 0.000 775.075 0.070 ;
    END
  END w0_wd_in[42]
  PIN w0_wd_in[43]
    DIRECTION INPUT ;
    USE SIGNAL ;
    SHAPE ABUTMENT ;
    PORT
      LAYER metal3 ;
      RECT 775.145 0.000 775.215 0.070 ;
    END
  END w0_wd_in[43]
  PIN w0_wd_in[44]
    DIRECTION INPUT ;
    USE SIGNAL ;
    SHAPE ABUTMENT ;
    PORT
      LAYER metal3 ;
      RECT 775.285 0.000 775.355 0.070 ;
    END
  END w0_wd_in[44]
  PIN w0_wd_in[45]
    DIRECTION INPUT ;
    USE SIGNAL ;
    SHAPE ABUTMENT ;
    PORT
      LAYER metal3 ;
      RECT 775.425 0.000 775.495 0.070 ;
    END
  END w0_wd_in[45]
  PIN w0_wd_in[46]
    DIRECTION INPUT ;
    USE SIGNAL ;
    SHAPE ABUTMENT ;
    PORT
      LAYER metal3 ;
      RECT 775.565 0.000 775.635 0.070 ;
    END
  END w0_wd_in[46]
  PIN w0_wd_in[47]
    DIRECTION INPUT ;
    USE SIGNAL ;
    SHAPE ABUTMENT ;
    PORT
      LAYER metal3 ;
      RECT 775.705 0.000 775.775 0.070 ;
    END
  END w0_wd_in[47]
  PIN w0_wd_in[48]
    DIRECTION INPUT ;
    USE SIGNAL ;
    SHAPE ABUTMENT ;
    PORT
      LAYER metal3 ;
      RECT 775.845 0.000 775.915 0.070 ;
    END
  END w0_wd_in[48]
  PIN w0_wd_in[49]
    DIRECTION INPUT ;
    USE SIGNAL ;
    SHAPE ABUTMENT ;
    PORT
      LAYER metal3 ;
      RECT 775.985 0.000 776.055 0.070 ;
    END
  END w0_wd_in[49]
  PIN w0_wd_in[50]
    DIRECTION INPUT ;
    USE SIGNAL ;
    SHAPE ABUTMENT ;
    PORT
      LAYER metal3 ;
      RECT 776.125 0.000 776.195 0.070 ;
    END
  END w0_wd_in[50]
  PIN w0_wd_in[51]
    DIRECTION INPUT ;
    USE SIGNAL ;
    SHAPE ABUTMENT ;
    PORT
      LAYER metal3 ;
      RECT 776.265 0.000 776.335 0.070 ;
    END
  END w0_wd_in[51]
  PIN w0_wd_in[52]
    DIRECTION INPUT ;
    USE SIGNAL ;
    SHAPE ABUTMENT ;
    PORT
      LAYER metal3 ;
      RECT 776.405 0.000 776.475 0.070 ;
    END
  END w0_wd_in[52]
  PIN w0_wd_in[53]
    DIRECTION INPUT ;
    USE SIGNAL ;
    SHAPE ABUTMENT ;
    PORT
      LAYER metal3 ;
      RECT 776.545 0.000 776.615 0.070 ;
    END
  END w0_wd_in[53]
  PIN w0_wd_in[54]
    DIRECTION INPUT ;
    USE SIGNAL ;
    SHAPE ABUTMENT ;
    PORT
      LAYER metal3 ;
      RECT 776.685 0.000 776.755 0.070 ;
    END
  END w0_wd_in[54]
  PIN w0_wd_in[55]
    DIRECTION INPUT ;
    USE SIGNAL ;
    SHAPE ABUTMENT ;
    PORT
      LAYER metal3 ;
      RECT 776.825 0.000 776.895 0.070 ;
    END
  END w0_wd_in[55]
  PIN w0_wd_in[56]
    DIRECTION INPUT ;
    USE SIGNAL ;
    SHAPE ABUTMENT ;
    PORT
      LAYER metal3 ;
      RECT 776.965 0.000 777.035 0.070 ;
    END
  END w0_wd_in[56]
  PIN w0_wd_in[57]
    DIRECTION INPUT ;
    USE SIGNAL ;
    SHAPE ABUTMENT ;
    PORT
      LAYER metal3 ;
      RECT 777.105 0.000 777.175 0.070 ;
    END
  END w0_wd_in[57]
  PIN w0_wd_in[58]
    DIRECTION INPUT ;
    USE SIGNAL ;
    SHAPE ABUTMENT ;
    PORT
      LAYER metal3 ;
      RECT 777.245 0.000 777.315 0.070 ;
    END
  END w0_wd_in[58]
  PIN w0_wd_in[59]
    DIRECTION INPUT ;
    USE SIGNAL ;
    SHAPE ABUTMENT ;
    PORT
      LAYER metal3 ;
      RECT 777.385 0.000 777.455 0.070 ;
    END
  END w0_wd_in[59]
  PIN w0_wd_in[60]
    DIRECTION INPUT ;
    USE SIGNAL ;
    SHAPE ABUTMENT ;
    PORT
      LAYER metal3 ;
      RECT 777.525 0.000 777.595 0.070 ;
    END
  END w0_wd_in[60]
  PIN w0_wd_in[61]
    DIRECTION INPUT ;
    USE SIGNAL ;
    SHAPE ABUTMENT ;
    PORT
      LAYER metal3 ;
      RECT 777.665 0.000 777.735 0.070 ;
    END
  END w0_wd_in[61]
  PIN w0_wd_in[62]
    DIRECTION INPUT ;
    USE SIGNAL ;
    SHAPE ABUTMENT ;
    PORT
      LAYER metal3 ;
      RECT 777.805 0.000 777.875 0.070 ;
    END
  END w0_wd_in[62]
  PIN w0_wd_in[63]
    DIRECTION INPUT ;
    USE SIGNAL ;
    SHAPE ABUTMENT ;
    PORT
      LAYER metal3 ;
      RECT 777.945 0.000 778.015 0.070 ;
    END
  END w0_wd_in[63]
  PIN w0_wd_in[64]
    DIRECTION INPUT ;
    USE SIGNAL ;
    SHAPE ABUTMENT ;
    PORT
      LAYER metal3 ;
      RECT 778.085 0.000 778.155 0.070 ;
    END
  END w0_wd_in[64]
  PIN w0_wd_in[65]
    DIRECTION INPUT ;
    USE SIGNAL ;
    SHAPE ABUTMENT ;
    PORT
      LAYER metal3 ;
      RECT 778.225 0.000 778.295 0.070 ;
    END
  END w0_wd_in[65]
  PIN w0_wd_in[66]
    DIRECTION INPUT ;
    USE SIGNAL ;
    SHAPE ABUTMENT ;
    PORT
      LAYER metal3 ;
      RECT 778.365 0.000 778.435 0.070 ;
    END
  END w0_wd_in[66]
  PIN w0_wd_in[67]
    DIRECTION INPUT ;
    USE SIGNAL ;
    SHAPE ABUTMENT ;
    PORT
      LAYER metal3 ;
      RECT 778.505 0.000 778.575 0.070 ;
    END
  END w0_wd_in[67]
  PIN w0_wd_in[68]
    DIRECTION INPUT ;
    USE SIGNAL ;
    SHAPE ABUTMENT ;
    PORT
      LAYER metal3 ;
      RECT 778.645 0.000 778.715 0.070 ;
    END
  END w0_wd_in[68]
  PIN w0_wd_in[69]
    DIRECTION INPUT ;
    USE SIGNAL ;
    SHAPE ABUTMENT ;
    PORT
      LAYER metal3 ;
      RECT 778.785 0.000 778.855 0.070 ;
    END
  END w0_wd_in[69]
  PIN w0_wd_in[70]
    DIRECTION INPUT ;
    USE SIGNAL ;
    SHAPE ABUTMENT ;
    PORT
      LAYER metal3 ;
      RECT 778.925 0.000 778.995 0.070 ;
    END
  END w0_wd_in[70]
  PIN w0_wd_in[71]
    DIRECTION INPUT ;
    USE SIGNAL ;
    SHAPE ABUTMENT ;
    PORT
      LAYER metal3 ;
      RECT 779.065 0.000 779.135 0.070 ;
    END
  END w0_wd_in[71]
  PIN w0_wd_in[72]
    DIRECTION INPUT ;
    USE SIGNAL ;
    SHAPE ABUTMENT ;
    PORT
      LAYER metal3 ;
      RECT 779.205 0.000 779.275 0.070 ;
    END
  END w0_wd_in[72]
  PIN w0_wd_in[73]
    DIRECTION INPUT ;
    USE SIGNAL ;
    SHAPE ABUTMENT ;
    PORT
      LAYER metal3 ;
      RECT 779.345 0.000 779.415 0.070 ;
    END
  END w0_wd_in[73]
  PIN w0_wd_in[74]
    DIRECTION INPUT ;
    USE SIGNAL ;
    SHAPE ABUTMENT ;
    PORT
      LAYER metal3 ;
      RECT 779.485 0.000 779.555 0.070 ;
    END
  END w0_wd_in[74]
  PIN w0_wd_in[75]
    DIRECTION INPUT ;
    USE SIGNAL ;
    SHAPE ABUTMENT ;
    PORT
      LAYER metal3 ;
      RECT 779.625 0.000 779.695 0.070 ;
    END
  END w0_wd_in[75]
  PIN w0_wd_in[76]
    DIRECTION INPUT ;
    USE SIGNAL ;
    SHAPE ABUTMENT ;
    PORT
      LAYER metal3 ;
      RECT 779.765 0.000 779.835 0.070 ;
    END
  END w0_wd_in[76]
  PIN w0_wd_in[77]
    DIRECTION INPUT ;
    USE SIGNAL ;
    SHAPE ABUTMENT ;
    PORT
      LAYER metal3 ;
      RECT 779.905 0.000 779.975 0.070 ;
    END
  END w0_wd_in[77]
  PIN w0_wd_in[78]
    DIRECTION INPUT ;
    USE SIGNAL ;
    SHAPE ABUTMENT ;
    PORT
      LAYER metal3 ;
      RECT 780.045 0.000 780.115 0.070 ;
    END
  END w0_wd_in[78]
  PIN w0_wd_in[79]
    DIRECTION INPUT ;
    USE SIGNAL ;
    SHAPE ABUTMENT ;
    PORT
      LAYER metal3 ;
      RECT 780.185 0.000 780.255 0.070 ;
    END
  END w0_wd_in[79]
  PIN w0_wd_in[80]
    DIRECTION INPUT ;
    USE SIGNAL ;
    SHAPE ABUTMENT ;
    PORT
      LAYER metal3 ;
      RECT 780.325 0.000 780.395 0.070 ;
    END
  END w0_wd_in[80]
  PIN w0_wd_in[81]
    DIRECTION INPUT ;
    USE SIGNAL ;
    SHAPE ABUTMENT ;
    PORT
      LAYER metal3 ;
      RECT 780.465 0.000 780.535 0.070 ;
    END
  END w0_wd_in[81]
  PIN w0_wd_in[82]
    DIRECTION INPUT ;
    USE SIGNAL ;
    SHAPE ABUTMENT ;
    PORT
      LAYER metal3 ;
      RECT 780.605 0.000 780.675 0.070 ;
    END
  END w0_wd_in[82]
  PIN w0_wd_in[83]
    DIRECTION INPUT ;
    USE SIGNAL ;
    SHAPE ABUTMENT ;
    PORT
      LAYER metal3 ;
      RECT 780.745 0.000 780.815 0.070 ;
    END
  END w0_wd_in[83]
  PIN w0_wd_in[84]
    DIRECTION INPUT ;
    USE SIGNAL ;
    SHAPE ABUTMENT ;
    PORT
      LAYER metal3 ;
      RECT 780.885 0.000 780.955 0.070 ;
    END
  END w0_wd_in[84]
  PIN w0_wd_in[85]
    DIRECTION INPUT ;
    USE SIGNAL ;
    SHAPE ABUTMENT ;
    PORT
      LAYER metal3 ;
      RECT 781.025 0.000 781.095 0.070 ;
    END
  END w0_wd_in[85]
  PIN w0_wd_in[86]
    DIRECTION INPUT ;
    USE SIGNAL ;
    SHAPE ABUTMENT ;
    PORT
      LAYER metal3 ;
      RECT 781.165 0.000 781.235 0.070 ;
    END
  END w0_wd_in[86]
  PIN w0_wd_in[87]
    DIRECTION INPUT ;
    USE SIGNAL ;
    SHAPE ABUTMENT ;
    PORT
      LAYER metal3 ;
      RECT 781.305 0.000 781.375 0.070 ;
    END
  END w0_wd_in[87]
  PIN w0_wd_in[88]
    DIRECTION INPUT ;
    USE SIGNAL ;
    SHAPE ABUTMENT ;
    PORT
      LAYER metal3 ;
      RECT 781.445 0.000 781.515 0.070 ;
    END
  END w0_wd_in[88]
  PIN w0_wd_in[89]
    DIRECTION INPUT ;
    USE SIGNAL ;
    SHAPE ABUTMENT ;
    PORT
      LAYER metal3 ;
      RECT 781.585 0.000 781.655 0.070 ;
    END
  END w0_wd_in[89]
  PIN w0_wd_in[90]
    DIRECTION INPUT ;
    USE SIGNAL ;
    SHAPE ABUTMENT ;
    PORT
      LAYER metal3 ;
      RECT 781.725 0.000 781.795 0.070 ;
    END
  END w0_wd_in[90]
  PIN w0_wd_in[91]
    DIRECTION INPUT ;
    USE SIGNAL ;
    SHAPE ABUTMENT ;
    PORT
      LAYER metal3 ;
      RECT 781.865 0.000 781.935 0.070 ;
    END
  END w0_wd_in[91]
  PIN w0_wd_in[92]
    DIRECTION INPUT ;
    USE SIGNAL ;
    SHAPE ABUTMENT ;
    PORT
      LAYER metal3 ;
      RECT 782.005 0.000 782.075 0.070 ;
    END
  END w0_wd_in[92]
  PIN w0_wd_in[93]
    DIRECTION INPUT ;
    USE SIGNAL ;
    SHAPE ABUTMENT ;
    PORT
      LAYER metal3 ;
      RECT 782.145 0.000 782.215 0.070 ;
    END
  END w0_wd_in[93]
  PIN w0_wd_in[94]
    DIRECTION INPUT ;
    USE SIGNAL ;
    SHAPE ABUTMENT ;
    PORT
      LAYER metal3 ;
      RECT 782.285 0.000 782.355 0.070 ;
    END
  END w0_wd_in[94]
  PIN w0_wd_in[95]
    DIRECTION INPUT ;
    USE SIGNAL ;
    SHAPE ABUTMENT ;
    PORT
      LAYER metal3 ;
      RECT 782.425 0.000 782.495 0.070 ;
    END
  END w0_wd_in[95]
  PIN w0_wd_in[96]
    DIRECTION INPUT ;
    USE SIGNAL ;
    SHAPE ABUTMENT ;
    PORT
      LAYER metal3 ;
      RECT 782.565 0.000 782.635 0.070 ;
    END
  END w0_wd_in[96]
  PIN w0_wd_in[97]
    DIRECTION INPUT ;
    USE SIGNAL ;
    SHAPE ABUTMENT ;
    PORT
      LAYER metal3 ;
      RECT 782.705 0.000 782.775 0.070 ;
    END
  END w0_wd_in[97]
  PIN w0_wd_in[98]
    DIRECTION INPUT ;
    USE SIGNAL ;
    SHAPE ABUTMENT ;
    PORT
      LAYER metal3 ;
      RECT 782.845 0.000 782.915 0.070 ;
    END
  END w0_wd_in[98]
  PIN w0_wd_in[99]
    DIRECTION INPUT ;
    USE SIGNAL ;
    SHAPE ABUTMENT ;
    PORT
      LAYER metal3 ;
      RECT 782.985 0.000 783.055 0.070 ;
    END
  END w0_wd_in[99]
  PIN w0_wd_in[100]
    DIRECTION INPUT ;
    USE SIGNAL ;
    SHAPE ABUTMENT ;
    PORT
      LAYER metal3 ;
      RECT 783.125 0.000 783.195 0.070 ;
    END
  END w0_wd_in[100]
  PIN w0_wd_in[101]
    DIRECTION INPUT ;
    USE SIGNAL ;
    SHAPE ABUTMENT ;
    PORT
      LAYER metal3 ;
      RECT 783.265 0.000 783.335 0.070 ;
    END
  END w0_wd_in[101]
  PIN w0_wd_in[102]
    DIRECTION INPUT ;
    USE SIGNAL ;
    SHAPE ABUTMENT ;
    PORT
      LAYER metal3 ;
      RECT 783.405 0.000 783.475 0.070 ;
    END
  END w0_wd_in[102]
  PIN w0_wd_in[103]
    DIRECTION INPUT ;
    USE SIGNAL ;
    SHAPE ABUTMENT ;
    PORT
      LAYER metal3 ;
      RECT 783.545 0.000 783.615 0.070 ;
    END
  END w0_wd_in[103]
  PIN w0_wd_in[104]
    DIRECTION INPUT ;
    USE SIGNAL ;
    SHAPE ABUTMENT ;
    PORT
      LAYER metal3 ;
      RECT 783.685 0.000 783.755 0.070 ;
    END
  END w0_wd_in[104]
  PIN w0_wd_in[105]
    DIRECTION INPUT ;
    USE SIGNAL ;
    SHAPE ABUTMENT ;
    PORT
      LAYER metal3 ;
      RECT 783.825 0.000 783.895 0.070 ;
    END
  END w0_wd_in[105]
  PIN w0_wd_in[106]
    DIRECTION INPUT ;
    USE SIGNAL ;
    SHAPE ABUTMENT ;
    PORT
      LAYER metal3 ;
      RECT 783.965 0.000 784.035 0.070 ;
    END
  END w0_wd_in[106]
  PIN w0_wd_in[107]
    DIRECTION INPUT ;
    USE SIGNAL ;
    SHAPE ABUTMENT ;
    PORT
      LAYER metal3 ;
      RECT 784.105 0.000 784.175 0.070 ;
    END
  END w0_wd_in[107]
  PIN w0_wd_in[108]
    DIRECTION INPUT ;
    USE SIGNAL ;
    SHAPE ABUTMENT ;
    PORT
      LAYER metal3 ;
      RECT 784.245 0.000 784.315 0.070 ;
    END
  END w0_wd_in[108]
  PIN w0_wd_in[109]
    DIRECTION INPUT ;
    USE SIGNAL ;
    SHAPE ABUTMENT ;
    PORT
      LAYER metal3 ;
      RECT 784.385 0.000 784.455 0.070 ;
    END
  END w0_wd_in[109]
  PIN w0_wd_in[110]
    DIRECTION INPUT ;
    USE SIGNAL ;
    SHAPE ABUTMENT ;
    PORT
      LAYER metal3 ;
      RECT 784.525 0.000 784.595 0.070 ;
    END
  END w0_wd_in[110]
  PIN w0_wd_in[111]
    DIRECTION INPUT ;
    USE SIGNAL ;
    SHAPE ABUTMENT ;
    PORT
      LAYER metal3 ;
      RECT 784.665 0.000 784.735 0.070 ;
    END
  END w0_wd_in[111]
  PIN w0_wd_in[112]
    DIRECTION INPUT ;
    USE SIGNAL ;
    SHAPE ABUTMENT ;
    PORT
      LAYER metal3 ;
      RECT 784.805 0.000 784.875 0.070 ;
    END
  END w0_wd_in[112]
  PIN w0_wd_in[113]
    DIRECTION INPUT ;
    USE SIGNAL ;
    SHAPE ABUTMENT ;
    PORT
      LAYER metal3 ;
      RECT 784.945 0.000 785.015 0.070 ;
    END
  END w0_wd_in[113]
  PIN w0_wd_in[114]
    DIRECTION INPUT ;
    USE SIGNAL ;
    SHAPE ABUTMENT ;
    PORT
      LAYER metal3 ;
      RECT 785.085 0.000 785.155 0.070 ;
    END
  END w0_wd_in[114]
  PIN w0_wd_in[115]
    DIRECTION INPUT ;
    USE SIGNAL ;
    SHAPE ABUTMENT ;
    PORT
      LAYER metal3 ;
      RECT 785.225 0.000 785.295 0.070 ;
    END
  END w0_wd_in[115]
  PIN w0_wd_in[116]
    DIRECTION INPUT ;
    USE SIGNAL ;
    SHAPE ABUTMENT ;
    PORT
      LAYER metal3 ;
      RECT 785.365 0.000 785.435 0.070 ;
    END
  END w0_wd_in[116]
  PIN w0_wd_in[117]
    DIRECTION INPUT ;
    USE SIGNAL ;
    SHAPE ABUTMENT ;
    PORT
      LAYER metal3 ;
      RECT 785.505 0.000 785.575 0.070 ;
    END
  END w0_wd_in[117]
  PIN w0_wd_in[118]
    DIRECTION INPUT ;
    USE SIGNAL ;
    SHAPE ABUTMENT ;
    PORT
      LAYER metal3 ;
      RECT 785.645 0.000 785.715 0.070 ;
    END
  END w0_wd_in[118]
  PIN w0_wd_in[119]
    DIRECTION INPUT ;
    USE SIGNAL ;
    SHAPE ABUTMENT ;
    PORT
      LAYER metal3 ;
      RECT 785.785 0.000 785.855 0.070 ;
    END
  END w0_wd_in[119]
  PIN w0_wd_in[120]
    DIRECTION INPUT ;
    USE SIGNAL ;
    SHAPE ABUTMENT ;
    PORT
      LAYER metal3 ;
      RECT 785.925 0.000 785.995 0.070 ;
    END
  END w0_wd_in[120]
  PIN w0_wd_in[121]
    DIRECTION INPUT ;
    USE SIGNAL ;
    SHAPE ABUTMENT ;
    PORT
      LAYER metal3 ;
      RECT 786.065 0.000 786.135 0.070 ;
    END
  END w0_wd_in[121]
  PIN w0_wd_in[122]
    DIRECTION INPUT ;
    USE SIGNAL ;
    SHAPE ABUTMENT ;
    PORT
      LAYER metal3 ;
      RECT 786.205 0.000 786.275 0.070 ;
    END
  END w0_wd_in[122]
  PIN w0_wd_in[123]
    DIRECTION INPUT ;
    USE SIGNAL ;
    SHAPE ABUTMENT ;
    PORT
      LAYER metal3 ;
      RECT 786.345 0.000 786.415 0.070 ;
    END
  END w0_wd_in[123]
  PIN w0_wd_in[124]
    DIRECTION INPUT ;
    USE SIGNAL ;
    SHAPE ABUTMENT ;
    PORT
      LAYER metal3 ;
      RECT 786.485 0.000 786.555 0.070 ;
    END
  END w0_wd_in[124]
  PIN w0_wd_in[125]
    DIRECTION INPUT ;
    USE SIGNAL ;
    SHAPE ABUTMENT ;
    PORT
      LAYER metal3 ;
      RECT 786.625 0.000 786.695 0.070 ;
    END
  END w0_wd_in[125]
  PIN w0_wd_in[126]
    DIRECTION INPUT ;
    USE SIGNAL ;
    SHAPE ABUTMENT ;
    PORT
      LAYER metal3 ;
      RECT 786.765 0.000 786.835 0.070 ;
    END
  END w0_wd_in[126]
  PIN w0_wd_in[127]
    DIRECTION INPUT ;
    USE SIGNAL ;
    SHAPE ABUTMENT ;
    PORT
      LAYER metal3 ;
      RECT 786.905 0.000 786.975 0.070 ;
    END
  END w0_wd_in[127]
  PIN w0_wd_in[128]
    DIRECTION INPUT ;
    USE SIGNAL ;
    SHAPE ABUTMENT ;
    PORT
      LAYER metal3 ;
      RECT 787.045 0.000 787.115 0.070 ;
    END
  END w0_wd_in[128]
  PIN w0_wd_in[129]
    DIRECTION INPUT ;
    USE SIGNAL ;
    SHAPE ABUTMENT ;
    PORT
      LAYER metal3 ;
      RECT 787.185 0.000 787.255 0.070 ;
    END
  END w0_wd_in[129]
  PIN w0_wd_in[130]
    DIRECTION INPUT ;
    USE SIGNAL ;
    SHAPE ABUTMENT ;
    PORT
      LAYER metal3 ;
      RECT 787.325 0.000 787.395 0.070 ;
    END
  END w0_wd_in[130]
  PIN w0_wd_in[131]
    DIRECTION INPUT ;
    USE SIGNAL ;
    SHAPE ABUTMENT ;
    PORT
      LAYER metal3 ;
      RECT 787.465 0.000 787.535 0.070 ;
    END
  END w0_wd_in[131]
  PIN w0_wd_in[132]
    DIRECTION INPUT ;
    USE SIGNAL ;
    SHAPE ABUTMENT ;
    PORT
      LAYER metal3 ;
      RECT 787.605 0.000 787.675 0.070 ;
    END
  END w0_wd_in[132]
  PIN w0_wd_in[133]
    DIRECTION INPUT ;
    USE SIGNAL ;
    SHAPE ABUTMENT ;
    PORT
      LAYER metal3 ;
      RECT 787.745 0.000 787.815 0.070 ;
    END
  END w0_wd_in[133]
  PIN w0_wd_in[134]
    DIRECTION INPUT ;
    USE SIGNAL ;
    SHAPE ABUTMENT ;
    PORT
      LAYER metal3 ;
      RECT 787.885 0.000 787.955 0.070 ;
    END
  END w0_wd_in[134]
  PIN w0_wd_in[135]
    DIRECTION INPUT ;
    USE SIGNAL ;
    SHAPE ABUTMENT ;
    PORT
      LAYER metal3 ;
      RECT 788.025 0.000 788.095 0.070 ;
    END
  END w0_wd_in[135]
  PIN w0_wd_in[136]
    DIRECTION INPUT ;
    USE SIGNAL ;
    SHAPE ABUTMENT ;
    PORT
      LAYER metal3 ;
      RECT 788.165 0.000 788.235 0.070 ;
    END
  END w0_wd_in[136]
  PIN w0_wd_in[137]
    DIRECTION INPUT ;
    USE SIGNAL ;
    SHAPE ABUTMENT ;
    PORT
      LAYER metal3 ;
      RECT 788.305 0.000 788.375 0.070 ;
    END
  END w0_wd_in[137]
  PIN w0_wd_in[138]
    DIRECTION INPUT ;
    USE SIGNAL ;
    SHAPE ABUTMENT ;
    PORT
      LAYER metal3 ;
      RECT 788.445 0.000 788.515 0.070 ;
    END
  END w0_wd_in[138]
  PIN w0_wd_in[139]
    DIRECTION INPUT ;
    USE SIGNAL ;
    SHAPE ABUTMENT ;
    PORT
      LAYER metal3 ;
      RECT 788.585 0.000 788.655 0.070 ;
    END
  END w0_wd_in[139]
  PIN w0_wd_in[140]
    DIRECTION INPUT ;
    USE SIGNAL ;
    SHAPE ABUTMENT ;
    PORT
      LAYER metal3 ;
      RECT 788.725 0.000 788.795 0.070 ;
    END
  END w0_wd_in[140]
  PIN w0_wd_in[141]
    DIRECTION INPUT ;
    USE SIGNAL ;
    SHAPE ABUTMENT ;
    PORT
      LAYER metal3 ;
      RECT 788.865 0.000 788.935 0.070 ;
    END
  END w0_wd_in[141]
  PIN w0_wd_in[142]
    DIRECTION INPUT ;
    USE SIGNAL ;
    SHAPE ABUTMENT ;
    PORT
      LAYER metal3 ;
      RECT 789.005 0.000 789.075 0.070 ;
    END
  END w0_wd_in[142]
  PIN w0_wd_in[143]
    DIRECTION INPUT ;
    USE SIGNAL ;
    SHAPE ABUTMENT ;
    PORT
      LAYER metal3 ;
      RECT 789.145 0.000 789.215 0.070 ;
    END
  END w0_wd_in[143]
  PIN w0_wd_in[144]
    DIRECTION INPUT ;
    USE SIGNAL ;
    SHAPE ABUTMENT ;
    PORT
      LAYER metal3 ;
      RECT 789.285 0.000 789.355 0.070 ;
    END
  END w0_wd_in[144]
  PIN w0_wd_in[145]
    DIRECTION INPUT ;
    USE SIGNAL ;
    SHAPE ABUTMENT ;
    PORT
      LAYER metal3 ;
      RECT 789.425 0.000 789.495 0.070 ;
    END
  END w0_wd_in[145]
  PIN w0_wd_in[146]
    DIRECTION INPUT ;
    USE SIGNAL ;
    SHAPE ABUTMENT ;
    PORT
      LAYER metal3 ;
      RECT 789.565 0.000 789.635 0.070 ;
    END
  END w0_wd_in[146]
  PIN w0_wd_in[147]
    DIRECTION INPUT ;
    USE SIGNAL ;
    SHAPE ABUTMENT ;
    PORT
      LAYER metal3 ;
      RECT 789.705 0.000 789.775 0.070 ;
    END
  END w0_wd_in[147]
  PIN w0_wd_in[148]
    DIRECTION INPUT ;
    USE SIGNAL ;
    SHAPE ABUTMENT ;
    PORT
      LAYER metal3 ;
      RECT 789.845 0.000 789.915 0.070 ;
    END
  END w0_wd_in[148]
  PIN w0_wd_in[149]
    DIRECTION INPUT ;
    USE SIGNAL ;
    SHAPE ABUTMENT ;
    PORT
      LAYER metal3 ;
      RECT 789.985 0.000 790.055 0.070 ;
    END
  END w0_wd_in[149]
  PIN w0_wd_in[150]
    DIRECTION INPUT ;
    USE SIGNAL ;
    SHAPE ABUTMENT ;
    PORT
      LAYER metal3 ;
      RECT 790.125 0.000 790.195 0.070 ;
    END
  END w0_wd_in[150]
  PIN w0_wd_in[151]
    DIRECTION INPUT ;
    USE SIGNAL ;
    SHAPE ABUTMENT ;
    PORT
      LAYER metal3 ;
      RECT 790.265 0.000 790.335 0.070 ;
    END
  END w0_wd_in[151]
  PIN w0_wd_in[152]
    DIRECTION INPUT ;
    USE SIGNAL ;
    SHAPE ABUTMENT ;
    PORT
      LAYER metal3 ;
      RECT 790.405 0.000 790.475 0.070 ;
    END
  END w0_wd_in[152]
  PIN w0_wd_in[153]
    DIRECTION INPUT ;
    USE SIGNAL ;
    SHAPE ABUTMENT ;
    PORT
      LAYER metal3 ;
      RECT 790.545 0.000 790.615 0.070 ;
    END
  END w0_wd_in[153]
  PIN w0_wd_in[154]
    DIRECTION INPUT ;
    USE SIGNAL ;
    SHAPE ABUTMENT ;
    PORT
      LAYER metal3 ;
      RECT 790.685 0.000 790.755 0.070 ;
    END
  END w0_wd_in[154]
  PIN w0_wd_in[155]
    DIRECTION INPUT ;
    USE SIGNAL ;
    SHAPE ABUTMENT ;
    PORT
      LAYER metal3 ;
      RECT 790.825 0.000 790.895 0.070 ;
    END
  END w0_wd_in[155]
  PIN w0_wd_in[156]
    DIRECTION INPUT ;
    USE SIGNAL ;
    SHAPE ABUTMENT ;
    PORT
      LAYER metal3 ;
      RECT 790.965 0.000 791.035 0.070 ;
    END
  END w0_wd_in[156]
  PIN w0_wd_in[157]
    DIRECTION INPUT ;
    USE SIGNAL ;
    SHAPE ABUTMENT ;
    PORT
      LAYER metal3 ;
      RECT 791.105 0.000 791.175 0.070 ;
    END
  END w0_wd_in[157]
  PIN w0_wd_in[158]
    DIRECTION INPUT ;
    USE SIGNAL ;
    SHAPE ABUTMENT ;
    PORT
      LAYER metal3 ;
      RECT 791.245 0.000 791.315 0.070 ;
    END
  END w0_wd_in[158]
  PIN w0_wd_in[159]
    DIRECTION INPUT ;
    USE SIGNAL ;
    SHAPE ABUTMENT ;
    PORT
      LAYER metal3 ;
      RECT 791.385 0.000 791.455 0.070 ;
    END
  END w0_wd_in[159]
  PIN w0_wd_in[160]
    DIRECTION INPUT ;
    USE SIGNAL ;
    SHAPE ABUTMENT ;
    PORT
      LAYER metal3 ;
      RECT 791.525 0.000 791.595 0.070 ;
    END
  END w0_wd_in[160]
  PIN w0_wd_in[161]
    DIRECTION INPUT ;
    USE SIGNAL ;
    SHAPE ABUTMENT ;
    PORT
      LAYER metal3 ;
      RECT 791.665 0.000 791.735 0.070 ;
    END
  END w0_wd_in[161]
  PIN w0_wd_in[162]
    DIRECTION INPUT ;
    USE SIGNAL ;
    SHAPE ABUTMENT ;
    PORT
      LAYER metal3 ;
      RECT 791.805 0.000 791.875 0.070 ;
    END
  END w0_wd_in[162]
  PIN w0_wd_in[163]
    DIRECTION INPUT ;
    USE SIGNAL ;
    SHAPE ABUTMENT ;
    PORT
      LAYER metal3 ;
      RECT 791.945 0.000 792.015 0.070 ;
    END
  END w0_wd_in[163]
  PIN w0_wd_in[164]
    DIRECTION INPUT ;
    USE SIGNAL ;
    SHAPE ABUTMENT ;
    PORT
      LAYER metal3 ;
      RECT 792.085 0.000 792.155 0.070 ;
    END
  END w0_wd_in[164]
  PIN w0_wd_in[165]
    DIRECTION INPUT ;
    USE SIGNAL ;
    SHAPE ABUTMENT ;
    PORT
      LAYER metal3 ;
      RECT 792.225 0.000 792.295 0.070 ;
    END
  END w0_wd_in[165]
  PIN w0_wd_in[166]
    DIRECTION INPUT ;
    USE SIGNAL ;
    SHAPE ABUTMENT ;
    PORT
      LAYER metal3 ;
      RECT 792.365 0.000 792.435 0.070 ;
    END
  END w0_wd_in[166]
  PIN w0_wd_in[167]
    DIRECTION INPUT ;
    USE SIGNAL ;
    SHAPE ABUTMENT ;
    PORT
      LAYER metal3 ;
      RECT 792.505 0.000 792.575 0.070 ;
    END
  END w0_wd_in[167]
  PIN w0_wd_in[168]
    DIRECTION INPUT ;
    USE SIGNAL ;
    SHAPE ABUTMENT ;
    PORT
      LAYER metal3 ;
      RECT 792.645 0.000 792.715 0.070 ;
    END
  END w0_wd_in[168]
  PIN w0_wd_in[169]
    DIRECTION INPUT ;
    USE SIGNAL ;
    SHAPE ABUTMENT ;
    PORT
      LAYER metal3 ;
      RECT 792.785 0.000 792.855 0.070 ;
    END
  END w0_wd_in[169]
  PIN w0_wd_in[170]
    DIRECTION INPUT ;
    USE SIGNAL ;
    SHAPE ABUTMENT ;
    PORT
      LAYER metal3 ;
      RECT 792.925 0.000 792.995 0.070 ;
    END
  END w0_wd_in[170]
  PIN w0_wd_in[171]
    DIRECTION INPUT ;
    USE SIGNAL ;
    SHAPE ABUTMENT ;
    PORT
      LAYER metal3 ;
      RECT 793.065 0.000 793.135 0.070 ;
    END
  END w0_wd_in[171]
  PIN w0_wd_in[172]
    DIRECTION INPUT ;
    USE SIGNAL ;
    SHAPE ABUTMENT ;
    PORT
      LAYER metal3 ;
      RECT 793.205 0.000 793.275 0.070 ;
    END
  END w0_wd_in[172]
  PIN w0_wd_in[173]
    DIRECTION INPUT ;
    USE SIGNAL ;
    SHAPE ABUTMENT ;
    PORT
      LAYER metal3 ;
      RECT 793.345 0.000 793.415 0.070 ;
    END
  END w0_wd_in[173]
  PIN w0_wd_in[174]
    DIRECTION INPUT ;
    USE SIGNAL ;
    SHAPE ABUTMENT ;
    PORT
      LAYER metal3 ;
      RECT 793.485 0.000 793.555 0.070 ;
    END
  END w0_wd_in[174]
  PIN w0_wd_in[175]
    DIRECTION INPUT ;
    USE SIGNAL ;
    SHAPE ABUTMENT ;
    PORT
      LAYER metal3 ;
      RECT 793.625 0.000 793.695 0.070 ;
    END
  END w0_wd_in[175]
  PIN w0_wd_in[176]
    DIRECTION INPUT ;
    USE SIGNAL ;
    SHAPE ABUTMENT ;
    PORT
      LAYER metal3 ;
      RECT 793.765 0.000 793.835 0.070 ;
    END
  END w0_wd_in[176]
  PIN w0_wd_in[177]
    DIRECTION INPUT ;
    USE SIGNAL ;
    SHAPE ABUTMENT ;
    PORT
      LAYER metal3 ;
      RECT 793.905 0.000 793.975 0.070 ;
    END
  END w0_wd_in[177]
  PIN w0_wd_in[178]
    DIRECTION INPUT ;
    USE SIGNAL ;
    SHAPE ABUTMENT ;
    PORT
      LAYER metal3 ;
      RECT 794.045 0.000 794.115 0.070 ;
    END
  END w0_wd_in[178]
  PIN w0_wd_in[179]
    DIRECTION INPUT ;
    USE SIGNAL ;
    SHAPE ABUTMENT ;
    PORT
      LAYER metal3 ;
      RECT 794.185 0.000 794.255 0.070 ;
    END
  END w0_wd_in[179]
  PIN w0_wd_in[180]
    DIRECTION INPUT ;
    USE SIGNAL ;
    SHAPE ABUTMENT ;
    PORT
      LAYER metal3 ;
      RECT 794.325 0.000 794.395 0.070 ;
    END
  END w0_wd_in[180]
  PIN w0_wd_in[181]
    DIRECTION INPUT ;
    USE SIGNAL ;
    SHAPE ABUTMENT ;
    PORT
      LAYER metal3 ;
      RECT 794.465 0.000 794.535 0.070 ;
    END
  END w0_wd_in[181]
  PIN w0_wd_in[182]
    DIRECTION INPUT ;
    USE SIGNAL ;
    SHAPE ABUTMENT ;
    PORT
      LAYER metal3 ;
      RECT 794.605 0.000 794.675 0.070 ;
    END
  END w0_wd_in[182]
  PIN w0_wd_in[183]
    DIRECTION INPUT ;
    USE SIGNAL ;
    SHAPE ABUTMENT ;
    PORT
      LAYER metal3 ;
      RECT 794.745 0.000 794.815 0.070 ;
    END
  END w0_wd_in[183]
  PIN w0_wd_in[184]
    DIRECTION INPUT ;
    USE SIGNAL ;
    SHAPE ABUTMENT ;
    PORT
      LAYER metal3 ;
      RECT 794.885 0.000 794.955 0.070 ;
    END
  END w0_wd_in[184]
  PIN w0_wd_in[185]
    DIRECTION INPUT ;
    USE SIGNAL ;
    SHAPE ABUTMENT ;
    PORT
      LAYER metal3 ;
      RECT 795.025 0.000 795.095 0.070 ;
    END
  END w0_wd_in[185]
  PIN w0_wd_in[186]
    DIRECTION INPUT ;
    USE SIGNAL ;
    SHAPE ABUTMENT ;
    PORT
      LAYER metal3 ;
      RECT 795.165 0.000 795.235 0.070 ;
    END
  END w0_wd_in[186]
  PIN w0_wd_in[187]
    DIRECTION INPUT ;
    USE SIGNAL ;
    SHAPE ABUTMENT ;
    PORT
      LAYER metal3 ;
      RECT 795.305 0.000 795.375 0.070 ;
    END
  END w0_wd_in[187]
  PIN w0_wd_in[188]
    DIRECTION INPUT ;
    USE SIGNAL ;
    SHAPE ABUTMENT ;
    PORT
      LAYER metal3 ;
      RECT 795.445 0.000 795.515 0.070 ;
    END
  END w0_wd_in[188]
  PIN w0_wd_in[189]
    DIRECTION INPUT ;
    USE SIGNAL ;
    SHAPE ABUTMENT ;
    PORT
      LAYER metal3 ;
      RECT 795.585 0.000 795.655 0.070 ;
    END
  END w0_wd_in[189]
  PIN w0_wd_in[190]
    DIRECTION INPUT ;
    USE SIGNAL ;
    SHAPE ABUTMENT ;
    PORT
      LAYER metal3 ;
      RECT 795.725 0.000 795.795 0.070 ;
    END
  END w0_wd_in[190]
  PIN w0_wd_in[191]
    DIRECTION INPUT ;
    USE SIGNAL ;
    SHAPE ABUTMENT ;
    PORT
      LAYER metal3 ;
      RECT 795.865 0.000 795.935 0.070 ;
    END
  END w0_wd_in[191]
  PIN w0_wd_in[192]
    DIRECTION INPUT ;
    USE SIGNAL ;
    SHAPE ABUTMENT ;
    PORT
      LAYER metal3 ;
      RECT 796.005 0.000 796.075 0.070 ;
    END
  END w0_wd_in[192]
  PIN w0_wd_in[193]
    DIRECTION INPUT ;
    USE SIGNAL ;
    SHAPE ABUTMENT ;
    PORT
      LAYER metal3 ;
      RECT 796.145 0.000 796.215 0.070 ;
    END
  END w0_wd_in[193]
  PIN w0_wd_in[194]
    DIRECTION INPUT ;
    USE SIGNAL ;
    SHAPE ABUTMENT ;
    PORT
      LAYER metal3 ;
      RECT 796.285 0.000 796.355 0.070 ;
    END
  END w0_wd_in[194]
  PIN w0_wd_in[195]
    DIRECTION INPUT ;
    USE SIGNAL ;
    SHAPE ABUTMENT ;
    PORT
      LAYER metal3 ;
      RECT 796.425 0.000 796.495 0.070 ;
    END
  END w0_wd_in[195]
  PIN w0_wd_in[196]
    DIRECTION INPUT ;
    USE SIGNAL ;
    SHAPE ABUTMENT ;
    PORT
      LAYER metal3 ;
      RECT 796.565 0.000 796.635 0.070 ;
    END
  END w0_wd_in[196]
  PIN w0_wd_in[197]
    DIRECTION INPUT ;
    USE SIGNAL ;
    SHAPE ABUTMENT ;
    PORT
      LAYER metal3 ;
      RECT 796.705 0.000 796.775 0.070 ;
    END
  END w0_wd_in[197]
  PIN w0_wd_in[198]
    DIRECTION INPUT ;
    USE SIGNAL ;
    SHAPE ABUTMENT ;
    PORT
      LAYER metal3 ;
      RECT 796.845 0.000 796.915 0.070 ;
    END
  END w0_wd_in[198]
  PIN w0_wd_in[199]
    DIRECTION INPUT ;
    USE SIGNAL ;
    SHAPE ABUTMENT ;
    PORT
      LAYER metal3 ;
      RECT 796.985 0.000 797.055 0.070 ;
    END
  END w0_wd_in[199]
  PIN w0_wd_in[200]
    DIRECTION INPUT ;
    USE SIGNAL ;
    SHAPE ABUTMENT ;
    PORT
      LAYER metal3 ;
      RECT 797.125 0.000 797.195 0.070 ;
    END
  END w0_wd_in[200]
  PIN w0_wd_in[201]
    DIRECTION INPUT ;
    USE SIGNAL ;
    SHAPE ABUTMENT ;
    PORT
      LAYER metal3 ;
      RECT 797.265 0.000 797.335 0.070 ;
    END
  END w0_wd_in[201]
  PIN w0_wd_in[202]
    DIRECTION INPUT ;
    USE SIGNAL ;
    SHAPE ABUTMENT ;
    PORT
      LAYER metal3 ;
      RECT 797.405 0.000 797.475 0.070 ;
    END
  END w0_wd_in[202]
  PIN w0_wd_in[203]
    DIRECTION INPUT ;
    USE SIGNAL ;
    SHAPE ABUTMENT ;
    PORT
      LAYER metal3 ;
      RECT 797.545 0.000 797.615 0.070 ;
    END
  END w0_wd_in[203]
  PIN w0_wd_in[204]
    DIRECTION INPUT ;
    USE SIGNAL ;
    SHAPE ABUTMENT ;
    PORT
      LAYER metal3 ;
      RECT 797.685 0.000 797.755 0.070 ;
    END
  END w0_wd_in[204]
  PIN w0_wd_in[205]
    DIRECTION INPUT ;
    USE SIGNAL ;
    SHAPE ABUTMENT ;
    PORT
      LAYER metal3 ;
      RECT 797.825 0.000 797.895 0.070 ;
    END
  END w0_wd_in[205]
  PIN w0_wd_in[206]
    DIRECTION INPUT ;
    USE SIGNAL ;
    SHAPE ABUTMENT ;
    PORT
      LAYER metal3 ;
      RECT 797.965 0.000 798.035 0.070 ;
    END
  END w0_wd_in[206]
  PIN w0_wd_in[207]
    DIRECTION INPUT ;
    USE SIGNAL ;
    SHAPE ABUTMENT ;
    PORT
      LAYER metal3 ;
      RECT 798.105 0.000 798.175 0.070 ;
    END
  END w0_wd_in[207]
  PIN w0_wd_in[208]
    DIRECTION INPUT ;
    USE SIGNAL ;
    SHAPE ABUTMENT ;
    PORT
      LAYER metal3 ;
      RECT 798.245 0.000 798.315 0.070 ;
    END
  END w0_wd_in[208]
  PIN w0_wd_in[209]
    DIRECTION INPUT ;
    USE SIGNAL ;
    SHAPE ABUTMENT ;
    PORT
      LAYER metal3 ;
      RECT 798.385 0.000 798.455 0.070 ;
    END
  END w0_wd_in[209]
  PIN w0_wd_in[210]
    DIRECTION INPUT ;
    USE SIGNAL ;
    SHAPE ABUTMENT ;
    PORT
      LAYER metal3 ;
      RECT 798.525 0.000 798.595 0.070 ;
    END
  END w0_wd_in[210]
  PIN w0_wd_in[211]
    DIRECTION INPUT ;
    USE SIGNAL ;
    SHAPE ABUTMENT ;
    PORT
      LAYER metal3 ;
      RECT 798.665 0.000 798.735 0.070 ;
    END
  END w0_wd_in[211]
  PIN w0_wd_in[212]
    DIRECTION INPUT ;
    USE SIGNAL ;
    SHAPE ABUTMENT ;
    PORT
      LAYER metal3 ;
      RECT 798.805 0.000 798.875 0.070 ;
    END
  END w0_wd_in[212]
  PIN w0_wd_in[213]
    DIRECTION INPUT ;
    USE SIGNAL ;
    SHAPE ABUTMENT ;
    PORT
      LAYER metal3 ;
      RECT 798.945 0.000 799.015 0.070 ;
    END
  END w0_wd_in[213]
  PIN w0_wd_in[214]
    DIRECTION INPUT ;
    USE SIGNAL ;
    SHAPE ABUTMENT ;
    PORT
      LAYER metal3 ;
      RECT 799.085 0.000 799.155 0.070 ;
    END
  END w0_wd_in[214]
  PIN w0_wd_in[215]
    DIRECTION INPUT ;
    USE SIGNAL ;
    SHAPE ABUTMENT ;
    PORT
      LAYER metal3 ;
      RECT 799.225 0.000 799.295 0.070 ;
    END
  END w0_wd_in[215]
  PIN w0_wd_in[216]
    DIRECTION INPUT ;
    USE SIGNAL ;
    SHAPE ABUTMENT ;
    PORT
      LAYER metal3 ;
      RECT 799.365 0.000 799.435 0.070 ;
    END
  END w0_wd_in[216]
  PIN w0_wd_in[217]
    DIRECTION INPUT ;
    USE SIGNAL ;
    SHAPE ABUTMENT ;
    PORT
      LAYER metal3 ;
      RECT 799.505 0.000 799.575 0.070 ;
    END
  END w0_wd_in[217]
  PIN w0_wd_in[218]
    DIRECTION INPUT ;
    USE SIGNAL ;
    SHAPE ABUTMENT ;
    PORT
      LAYER metal3 ;
      RECT 799.645 0.000 799.715 0.070 ;
    END
  END w0_wd_in[218]
  PIN w0_wd_in[219]
    DIRECTION INPUT ;
    USE SIGNAL ;
    SHAPE ABUTMENT ;
    PORT
      LAYER metal3 ;
      RECT 799.785 0.000 799.855 0.070 ;
    END
  END w0_wd_in[219]
  PIN w0_wd_in[220]
    DIRECTION INPUT ;
    USE SIGNAL ;
    SHAPE ABUTMENT ;
    PORT
      LAYER metal3 ;
      RECT 799.925 0.000 799.995 0.070 ;
    END
  END w0_wd_in[220]
  PIN w0_wd_in[221]
    DIRECTION INPUT ;
    USE SIGNAL ;
    SHAPE ABUTMENT ;
    PORT
      LAYER metal3 ;
      RECT 800.065 0.000 800.135 0.070 ;
    END
  END w0_wd_in[221]
  PIN w0_wd_in[222]
    DIRECTION INPUT ;
    USE SIGNAL ;
    SHAPE ABUTMENT ;
    PORT
      LAYER metal3 ;
      RECT 800.205 0.000 800.275 0.070 ;
    END
  END w0_wd_in[222]
  PIN w0_wd_in[223]
    DIRECTION INPUT ;
    USE SIGNAL ;
    SHAPE ABUTMENT ;
    PORT
      LAYER metal3 ;
      RECT 800.345 0.000 800.415 0.070 ;
    END
  END w0_wd_in[223]
  PIN w0_wd_in[224]
    DIRECTION INPUT ;
    USE SIGNAL ;
    SHAPE ABUTMENT ;
    PORT
      LAYER metal3 ;
      RECT 800.485 0.000 800.555 0.070 ;
    END
  END w0_wd_in[224]
  PIN w0_wd_in[225]
    DIRECTION INPUT ;
    USE SIGNAL ;
    SHAPE ABUTMENT ;
    PORT
      LAYER metal3 ;
      RECT 800.625 0.000 800.695 0.070 ;
    END
  END w0_wd_in[225]
  PIN w0_wd_in[226]
    DIRECTION INPUT ;
    USE SIGNAL ;
    SHAPE ABUTMENT ;
    PORT
      LAYER metal3 ;
      RECT 800.765 0.000 800.835 0.070 ;
    END
  END w0_wd_in[226]
  PIN w0_wd_in[227]
    DIRECTION INPUT ;
    USE SIGNAL ;
    SHAPE ABUTMENT ;
    PORT
      LAYER metal3 ;
      RECT 800.905 0.000 800.975 0.070 ;
    END
  END w0_wd_in[227]
  PIN w0_wd_in[228]
    DIRECTION INPUT ;
    USE SIGNAL ;
    SHAPE ABUTMENT ;
    PORT
      LAYER metal3 ;
      RECT 801.045 0.000 801.115 0.070 ;
    END
  END w0_wd_in[228]
  PIN w0_wd_in[229]
    DIRECTION INPUT ;
    USE SIGNAL ;
    SHAPE ABUTMENT ;
    PORT
      LAYER metal3 ;
      RECT 801.185 0.000 801.255 0.070 ;
    END
  END w0_wd_in[229]
  PIN w0_wd_in[230]
    DIRECTION INPUT ;
    USE SIGNAL ;
    SHAPE ABUTMENT ;
    PORT
      LAYER metal3 ;
      RECT 801.325 0.000 801.395 0.070 ;
    END
  END w0_wd_in[230]
  PIN w0_wd_in[231]
    DIRECTION INPUT ;
    USE SIGNAL ;
    SHAPE ABUTMENT ;
    PORT
      LAYER metal3 ;
      RECT 801.465 0.000 801.535 0.070 ;
    END
  END w0_wd_in[231]
  PIN w0_wd_in[232]
    DIRECTION INPUT ;
    USE SIGNAL ;
    SHAPE ABUTMENT ;
    PORT
      LAYER metal3 ;
      RECT 801.605 0.000 801.675 0.070 ;
    END
  END w0_wd_in[232]
  PIN w0_wd_in[233]
    DIRECTION INPUT ;
    USE SIGNAL ;
    SHAPE ABUTMENT ;
    PORT
      LAYER metal3 ;
      RECT 801.745 0.000 801.815 0.070 ;
    END
  END w0_wd_in[233]
  PIN w0_wd_in[234]
    DIRECTION INPUT ;
    USE SIGNAL ;
    SHAPE ABUTMENT ;
    PORT
      LAYER metal3 ;
      RECT 801.885 0.000 801.955 0.070 ;
    END
  END w0_wd_in[234]
  PIN w0_wd_in[235]
    DIRECTION INPUT ;
    USE SIGNAL ;
    SHAPE ABUTMENT ;
    PORT
      LAYER metal3 ;
      RECT 802.025 0.000 802.095 0.070 ;
    END
  END w0_wd_in[235]
  PIN w0_wd_in[236]
    DIRECTION INPUT ;
    USE SIGNAL ;
    SHAPE ABUTMENT ;
    PORT
      LAYER metal3 ;
      RECT 802.165 0.000 802.235 0.070 ;
    END
  END w0_wd_in[236]
  PIN w0_wd_in[237]
    DIRECTION INPUT ;
    USE SIGNAL ;
    SHAPE ABUTMENT ;
    PORT
      LAYER metal3 ;
      RECT 802.305 0.000 802.375 0.070 ;
    END
  END w0_wd_in[237]
  PIN w0_wd_in[238]
    DIRECTION INPUT ;
    USE SIGNAL ;
    SHAPE ABUTMENT ;
    PORT
      LAYER metal3 ;
      RECT 802.445 0.000 802.515 0.070 ;
    END
  END w0_wd_in[238]
  PIN w0_wd_in[239]
    DIRECTION INPUT ;
    USE SIGNAL ;
    SHAPE ABUTMENT ;
    PORT
      LAYER metal3 ;
      RECT 802.585 0.000 802.655 0.070 ;
    END
  END w0_wd_in[239]
  PIN w0_wd_in[240]
    DIRECTION INPUT ;
    USE SIGNAL ;
    SHAPE ABUTMENT ;
    PORT
      LAYER metal3 ;
      RECT 802.725 0.000 802.795 0.070 ;
    END
  END w0_wd_in[240]
  PIN w0_wd_in[241]
    DIRECTION INPUT ;
    USE SIGNAL ;
    SHAPE ABUTMENT ;
    PORT
      LAYER metal3 ;
      RECT 802.865 0.000 802.935 0.070 ;
    END
  END w0_wd_in[241]
  PIN w0_wd_in[242]
    DIRECTION INPUT ;
    USE SIGNAL ;
    SHAPE ABUTMENT ;
    PORT
      LAYER metal3 ;
      RECT 803.005 0.000 803.075 0.070 ;
    END
  END w0_wd_in[242]
  PIN w0_wd_in[243]
    DIRECTION INPUT ;
    USE SIGNAL ;
    SHAPE ABUTMENT ;
    PORT
      LAYER metal3 ;
      RECT 803.145 0.000 803.215 0.070 ;
    END
  END w0_wd_in[243]
  PIN w0_wd_in[244]
    DIRECTION INPUT ;
    USE SIGNAL ;
    SHAPE ABUTMENT ;
    PORT
      LAYER metal3 ;
      RECT 803.285 0.000 803.355 0.070 ;
    END
  END w0_wd_in[244]
  PIN w0_wd_in[245]
    DIRECTION INPUT ;
    USE SIGNAL ;
    SHAPE ABUTMENT ;
    PORT
      LAYER metal3 ;
      RECT 803.425 0.000 803.495 0.070 ;
    END
  END w0_wd_in[245]
  PIN w0_wd_in[246]
    DIRECTION INPUT ;
    USE SIGNAL ;
    SHAPE ABUTMENT ;
    PORT
      LAYER metal3 ;
      RECT 803.565 0.000 803.635 0.070 ;
    END
  END w0_wd_in[246]
  PIN w0_wd_in[247]
    DIRECTION INPUT ;
    USE SIGNAL ;
    SHAPE ABUTMENT ;
    PORT
      LAYER metal3 ;
      RECT 803.705 0.000 803.775 0.070 ;
    END
  END w0_wd_in[247]
  PIN w0_wd_in[248]
    DIRECTION INPUT ;
    USE SIGNAL ;
    SHAPE ABUTMENT ;
    PORT
      LAYER metal3 ;
      RECT 803.845 0.000 803.915 0.070 ;
    END
  END w0_wd_in[248]
  PIN w0_wd_in[249]
    DIRECTION INPUT ;
    USE SIGNAL ;
    SHAPE ABUTMENT ;
    PORT
      LAYER metal3 ;
      RECT 803.985 0.000 804.055 0.070 ;
    END
  END w0_wd_in[249]
  PIN w0_wd_in[250]
    DIRECTION INPUT ;
    USE SIGNAL ;
    SHAPE ABUTMENT ;
    PORT
      LAYER metal3 ;
      RECT 804.125 0.000 804.195 0.070 ;
    END
  END w0_wd_in[250]
  PIN w0_wd_in[251]
    DIRECTION INPUT ;
    USE SIGNAL ;
    SHAPE ABUTMENT ;
    PORT
      LAYER metal3 ;
      RECT 804.265 0.000 804.335 0.070 ;
    END
  END w0_wd_in[251]
  PIN w0_wd_in[252]
    DIRECTION INPUT ;
    USE SIGNAL ;
    SHAPE ABUTMENT ;
    PORT
      LAYER metal3 ;
      RECT 804.405 0.000 804.475 0.070 ;
    END
  END w0_wd_in[252]
  PIN w0_wd_in[253]
    DIRECTION INPUT ;
    USE SIGNAL ;
    SHAPE ABUTMENT ;
    PORT
      LAYER metal3 ;
      RECT 804.545 0.000 804.615 0.070 ;
    END
  END w0_wd_in[253]
  PIN w0_wd_in[254]
    DIRECTION INPUT ;
    USE SIGNAL ;
    SHAPE ABUTMENT ;
    PORT
      LAYER metal3 ;
      RECT 804.685 0.000 804.755 0.070 ;
    END
  END w0_wd_in[254]
  PIN w0_wd_in[255]
    DIRECTION INPUT ;
    USE SIGNAL ;
    SHAPE ABUTMENT ;
    PORT
      LAYER metal3 ;
      RECT 804.825 0.000 804.895 0.070 ;
    END
  END w0_wd_in[255]
  PIN w0_wd_in[256]
    DIRECTION INPUT ;
    USE SIGNAL ;
    SHAPE ABUTMENT ;
    PORT
      LAYER metal3 ;
      RECT 804.965 0.000 805.035 0.070 ;
    END
  END w0_wd_in[256]
  PIN w0_wd_in[257]
    DIRECTION INPUT ;
    USE SIGNAL ;
    SHAPE ABUTMENT ;
    PORT
      LAYER metal3 ;
      RECT 805.105 0.000 805.175 0.070 ;
    END
  END w0_wd_in[257]
  PIN w0_wd_in[258]
    DIRECTION INPUT ;
    USE SIGNAL ;
    SHAPE ABUTMENT ;
    PORT
      LAYER metal3 ;
      RECT 805.245 0.000 805.315 0.070 ;
    END
  END w0_wd_in[258]
  PIN w0_wd_in[259]
    DIRECTION INPUT ;
    USE SIGNAL ;
    SHAPE ABUTMENT ;
    PORT
      LAYER metal3 ;
      RECT 805.385 0.000 805.455 0.070 ;
    END
  END w0_wd_in[259]
  PIN w0_wd_in[260]
    DIRECTION INPUT ;
    USE SIGNAL ;
    SHAPE ABUTMENT ;
    PORT
      LAYER metal3 ;
      RECT 805.525 0.000 805.595 0.070 ;
    END
  END w0_wd_in[260]
  PIN w0_wd_in[261]
    DIRECTION INPUT ;
    USE SIGNAL ;
    SHAPE ABUTMENT ;
    PORT
      LAYER metal3 ;
      RECT 805.665 0.000 805.735 0.070 ;
    END
  END w0_wd_in[261]
  PIN w0_wd_in[262]
    DIRECTION INPUT ;
    USE SIGNAL ;
    SHAPE ABUTMENT ;
    PORT
      LAYER metal3 ;
      RECT 805.805 0.000 805.875 0.070 ;
    END
  END w0_wd_in[262]
  PIN w0_wd_in[263]
    DIRECTION INPUT ;
    USE SIGNAL ;
    SHAPE ABUTMENT ;
    PORT
      LAYER metal3 ;
      RECT 805.945 0.000 806.015 0.070 ;
    END
  END w0_wd_in[263]
  PIN w0_wd_in[264]
    DIRECTION INPUT ;
    USE SIGNAL ;
    SHAPE ABUTMENT ;
    PORT
      LAYER metal3 ;
      RECT 806.085 0.000 806.155 0.070 ;
    END
  END w0_wd_in[264]
  PIN w0_wd_in[265]
    DIRECTION INPUT ;
    USE SIGNAL ;
    SHAPE ABUTMENT ;
    PORT
      LAYER metal3 ;
      RECT 806.225 0.000 806.295 0.070 ;
    END
  END w0_wd_in[265]
  PIN w0_wd_in[266]
    DIRECTION INPUT ;
    USE SIGNAL ;
    SHAPE ABUTMENT ;
    PORT
      LAYER metal3 ;
      RECT 806.365 0.000 806.435 0.070 ;
    END
  END w0_wd_in[266]
  PIN w0_wd_in[267]
    DIRECTION INPUT ;
    USE SIGNAL ;
    SHAPE ABUTMENT ;
    PORT
      LAYER metal3 ;
      RECT 806.505 0.000 806.575 0.070 ;
    END
  END w0_wd_in[267]
  PIN w0_wd_in[268]
    DIRECTION INPUT ;
    USE SIGNAL ;
    SHAPE ABUTMENT ;
    PORT
      LAYER metal3 ;
      RECT 806.645 0.000 806.715 0.070 ;
    END
  END w0_wd_in[268]
  PIN w0_wd_in[269]
    DIRECTION INPUT ;
    USE SIGNAL ;
    SHAPE ABUTMENT ;
    PORT
      LAYER metal3 ;
      RECT 806.785 0.000 806.855 0.070 ;
    END
  END w0_wd_in[269]
  PIN w0_wd_in[270]
    DIRECTION INPUT ;
    USE SIGNAL ;
    SHAPE ABUTMENT ;
    PORT
      LAYER metal3 ;
      RECT 806.925 0.000 806.995 0.070 ;
    END
  END w0_wd_in[270]
  PIN w0_wd_in[271]
    DIRECTION INPUT ;
    USE SIGNAL ;
    SHAPE ABUTMENT ;
    PORT
      LAYER metal3 ;
      RECT 807.065 0.000 807.135 0.070 ;
    END
  END w0_wd_in[271]
  PIN w0_wd_in[272]
    DIRECTION INPUT ;
    USE SIGNAL ;
    SHAPE ABUTMENT ;
    PORT
      LAYER metal3 ;
      RECT 807.205 0.000 807.275 0.070 ;
    END
  END w0_wd_in[272]
  PIN w0_wd_in[273]
    DIRECTION INPUT ;
    USE SIGNAL ;
    SHAPE ABUTMENT ;
    PORT
      LAYER metal3 ;
      RECT 807.345 0.000 807.415 0.070 ;
    END
  END w0_wd_in[273]
  PIN w0_wd_in[274]
    DIRECTION INPUT ;
    USE SIGNAL ;
    SHAPE ABUTMENT ;
    PORT
      LAYER metal3 ;
      RECT 807.485 0.000 807.555 0.070 ;
    END
  END w0_wd_in[274]
  PIN w0_wd_in[275]
    DIRECTION INPUT ;
    USE SIGNAL ;
    SHAPE ABUTMENT ;
    PORT
      LAYER metal3 ;
      RECT 807.625 0.000 807.695 0.070 ;
    END
  END w0_wd_in[275]
  PIN w0_wd_in[276]
    DIRECTION INPUT ;
    USE SIGNAL ;
    SHAPE ABUTMENT ;
    PORT
      LAYER metal3 ;
      RECT 807.765 0.000 807.835 0.070 ;
    END
  END w0_wd_in[276]
  PIN w0_wd_in[277]
    DIRECTION INPUT ;
    USE SIGNAL ;
    SHAPE ABUTMENT ;
    PORT
      LAYER metal3 ;
      RECT 807.905 0.000 807.975 0.070 ;
    END
  END w0_wd_in[277]
  PIN w0_wd_in[278]
    DIRECTION INPUT ;
    USE SIGNAL ;
    SHAPE ABUTMENT ;
    PORT
      LAYER metal3 ;
      RECT 808.045 0.000 808.115 0.070 ;
    END
  END w0_wd_in[278]
  PIN w0_wd_in[279]
    DIRECTION INPUT ;
    USE SIGNAL ;
    SHAPE ABUTMENT ;
    PORT
      LAYER metal3 ;
      RECT 808.185 0.000 808.255 0.070 ;
    END
  END w0_wd_in[279]
  PIN w0_wd_in[280]
    DIRECTION INPUT ;
    USE SIGNAL ;
    SHAPE ABUTMENT ;
    PORT
      LAYER metal3 ;
      RECT 808.325 0.000 808.395 0.070 ;
    END
  END w0_wd_in[280]
  PIN w0_wd_in[281]
    DIRECTION INPUT ;
    USE SIGNAL ;
    SHAPE ABUTMENT ;
    PORT
      LAYER metal3 ;
      RECT 808.465 0.000 808.535 0.070 ;
    END
  END w0_wd_in[281]
  PIN w0_wd_in[282]
    DIRECTION INPUT ;
    USE SIGNAL ;
    SHAPE ABUTMENT ;
    PORT
      LAYER metal3 ;
      RECT 808.605 0.000 808.675 0.070 ;
    END
  END w0_wd_in[282]
  PIN w0_wd_in[283]
    DIRECTION INPUT ;
    USE SIGNAL ;
    SHAPE ABUTMENT ;
    PORT
      LAYER metal3 ;
      RECT 808.745 0.000 808.815 0.070 ;
    END
  END w0_wd_in[283]
  PIN w0_wd_in[284]
    DIRECTION INPUT ;
    USE SIGNAL ;
    SHAPE ABUTMENT ;
    PORT
      LAYER metal3 ;
      RECT 808.885 0.000 808.955 0.070 ;
    END
  END w0_wd_in[284]
  PIN w0_wd_in[285]
    DIRECTION INPUT ;
    USE SIGNAL ;
    SHAPE ABUTMENT ;
    PORT
      LAYER metal3 ;
      RECT 809.025 0.000 809.095 0.070 ;
    END
  END w0_wd_in[285]
  PIN w0_wd_in[286]
    DIRECTION INPUT ;
    USE SIGNAL ;
    SHAPE ABUTMENT ;
    PORT
      LAYER metal3 ;
      RECT 809.165 0.000 809.235 0.070 ;
    END
  END w0_wd_in[286]
  PIN w0_wd_in[287]
    DIRECTION INPUT ;
    USE SIGNAL ;
    SHAPE ABUTMENT ;
    PORT
      LAYER metal3 ;
      RECT 809.305 0.000 809.375 0.070 ;
    END
  END w0_wd_in[287]
  PIN w0_wd_in[288]
    DIRECTION INPUT ;
    USE SIGNAL ;
    SHAPE ABUTMENT ;
    PORT
      LAYER metal3 ;
      RECT 809.445 0.000 809.515 0.070 ;
    END
  END w0_wd_in[288]
  PIN w0_wd_in[289]
    DIRECTION INPUT ;
    USE SIGNAL ;
    SHAPE ABUTMENT ;
    PORT
      LAYER metal3 ;
      RECT 809.585 0.000 809.655 0.070 ;
    END
  END w0_wd_in[289]
  PIN w0_wd_in[290]
    DIRECTION INPUT ;
    USE SIGNAL ;
    SHAPE ABUTMENT ;
    PORT
      LAYER metal3 ;
      RECT 809.725 0.000 809.795 0.070 ;
    END
  END w0_wd_in[290]
  PIN w0_wd_in[291]
    DIRECTION INPUT ;
    USE SIGNAL ;
    SHAPE ABUTMENT ;
    PORT
      LAYER metal3 ;
      RECT 809.865 0.000 809.935 0.070 ;
    END
  END w0_wd_in[291]
  PIN w0_wd_in[292]
    DIRECTION INPUT ;
    USE SIGNAL ;
    SHAPE ABUTMENT ;
    PORT
      LAYER metal3 ;
      RECT 810.005 0.000 810.075 0.070 ;
    END
  END w0_wd_in[292]
  PIN w0_wd_in[293]
    DIRECTION INPUT ;
    USE SIGNAL ;
    SHAPE ABUTMENT ;
    PORT
      LAYER metal3 ;
      RECT 810.145 0.000 810.215 0.070 ;
    END
  END w0_wd_in[293]
  PIN w0_wd_in[294]
    DIRECTION INPUT ;
    USE SIGNAL ;
    SHAPE ABUTMENT ;
    PORT
      LAYER metal3 ;
      RECT 810.285 0.000 810.355 0.070 ;
    END
  END w0_wd_in[294]
  PIN w0_wd_in[295]
    DIRECTION INPUT ;
    USE SIGNAL ;
    SHAPE ABUTMENT ;
    PORT
      LAYER metal3 ;
      RECT 810.425 0.000 810.495 0.070 ;
    END
  END w0_wd_in[295]
  PIN w0_wd_in[296]
    DIRECTION INPUT ;
    USE SIGNAL ;
    SHAPE ABUTMENT ;
    PORT
      LAYER metal3 ;
      RECT 810.565 0.000 810.635 0.070 ;
    END
  END w0_wd_in[296]
  PIN w0_wd_in[297]
    DIRECTION INPUT ;
    USE SIGNAL ;
    SHAPE ABUTMENT ;
    PORT
      LAYER metal3 ;
      RECT 810.705 0.000 810.775 0.070 ;
    END
  END w0_wd_in[297]
  PIN w0_wd_in[298]
    DIRECTION INPUT ;
    USE SIGNAL ;
    SHAPE ABUTMENT ;
    PORT
      LAYER metal3 ;
      RECT 810.845 0.000 810.915 0.070 ;
    END
  END w0_wd_in[298]
  PIN w0_wd_in[299]
    DIRECTION INPUT ;
    USE SIGNAL ;
    SHAPE ABUTMENT ;
    PORT
      LAYER metal3 ;
      RECT 810.985 0.000 811.055 0.070 ;
    END
  END w0_wd_in[299]
  PIN w0_wd_in[300]
    DIRECTION INPUT ;
    USE SIGNAL ;
    SHAPE ABUTMENT ;
    PORT
      LAYER metal3 ;
      RECT 811.125 0.000 811.195 0.070 ;
    END
  END w0_wd_in[300]
  PIN w0_wd_in[301]
    DIRECTION INPUT ;
    USE SIGNAL ;
    SHAPE ABUTMENT ;
    PORT
      LAYER metal3 ;
      RECT 811.265 0.000 811.335 0.070 ;
    END
  END w0_wd_in[301]
  PIN w0_wd_in[302]
    DIRECTION INPUT ;
    USE SIGNAL ;
    SHAPE ABUTMENT ;
    PORT
      LAYER metal3 ;
      RECT 811.405 0.000 811.475 0.070 ;
    END
  END w0_wd_in[302]
  PIN w0_wd_in[303]
    DIRECTION INPUT ;
    USE SIGNAL ;
    SHAPE ABUTMENT ;
    PORT
      LAYER metal3 ;
      RECT 811.545 0.000 811.615 0.070 ;
    END
  END w0_wd_in[303]
  PIN w0_wd_in[304]
    DIRECTION INPUT ;
    USE SIGNAL ;
    SHAPE ABUTMENT ;
    PORT
      LAYER metal3 ;
      RECT 811.685 0.000 811.755 0.070 ;
    END
  END w0_wd_in[304]
  PIN w0_wd_in[305]
    DIRECTION INPUT ;
    USE SIGNAL ;
    SHAPE ABUTMENT ;
    PORT
      LAYER metal3 ;
      RECT 811.825 0.000 811.895 0.070 ;
    END
  END w0_wd_in[305]
  PIN w0_wd_in[306]
    DIRECTION INPUT ;
    USE SIGNAL ;
    SHAPE ABUTMENT ;
    PORT
      LAYER metal3 ;
      RECT 811.965 0.000 812.035 0.070 ;
    END
  END w0_wd_in[306]
  PIN w0_wd_in[307]
    DIRECTION INPUT ;
    USE SIGNAL ;
    SHAPE ABUTMENT ;
    PORT
      LAYER metal3 ;
      RECT 812.105 0.000 812.175 0.070 ;
    END
  END w0_wd_in[307]
  PIN w0_wd_in[308]
    DIRECTION INPUT ;
    USE SIGNAL ;
    SHAPE ABUTMENT ;
    PORT
      LAYER metal3 ;
      RECT 812.245 0.000 812.315 0.070 ;
    END
  END w0_wd_in[308]
  PIN w0_wd_in[309]
    DIRECTION INPUT ;
    USE SIGNAL ;
    SHAPE ABUTMENT ;
    PORT
      LAYER metal3 ;
      RECT 812.385 0.000 812.455 0.070 ;
    END
  END w0_wd_in[309]
  PIN w0_wd_in[310]
    DIRECTION INPUT ;
    USE SIGNAL ;
    SHAPE ABUTMENT ;
    PORT
      LAYER metal3 ;
      RECT 812.525 0.000 812.595 0.070 ;
    END
  END w0_wd_in[310]
  PIN w0_wd_in[311]
    DIRECTION INPUT ;
    USE SIGNAL ;
    SHAPE ABUTMENT ;
    PORT
      LAYER metal3 ;
      RECT 812.665 0.000 812.735 0.070 ;
    END
  END w0_wd_in[311]
  PIN w0_wd_in[312]
    DIRECTION INPUT ;
    USE SIGNAL ;
    SHAPE ABUTMENT ;
    PORT
      LAYER metal3 ;
      RECT 812.805 0.000 812.875 0.070 ;
    END
  END w0_wd_in[312]
  PIN w0_wd_in[313]
    DIRECTION INPUT ;
    USE SIGNAL ;
    SHAPE ABUTMENT ;
    PORT
      LAYER metal3 ;
      RECT 812.945 0.000 813.015 0.070 ;
    END
  END w0_wd_in[313]
  PIN w0_wd_in[314]
    DIRECTION INPUT ;
    USE SIGNAL ;
    SHAPE ABUTMENT ;
    PORT
      LAYER metal3 ;
      RECT 813.085 0.000 813.155 0.070 ;
    END
  END w0_wd_in[314]
  PIN w0_wd_in[315]
    DIRECTION INPUT ;
    USE SIGNAL ;
    SHAPE ABUTMENT ;
    PORT
      LAYER metal3 ;
      RECT 813.225 0.000 813.295 0.070 ;
    END
  END w0_wd_in[315]
  PIN w0_wd_in[316]
    DIRECTION INPUT ;
    USE SIGNAL ;
    SHAPE ABUTMENT ;
    PORT
      LAYER metal3 ;
      RECT 813.365 0.000 813.435 0.070 ;
    END
  END w0_wd_in[316]
  PIN w0_wd_in[317]
    DIRECTION INPUT ;
    USE SIGNAL ;
    SHAPE ABUTMENT ;
    PORT
      LAYER metal3 ;
      RECT 813.505 0.000 813.575 0.070 ;
    END
  END w0_wd_in[317]
  PIN w0_wd_in[318]
    DIRECTION INPUT ;
    USE SIGNAL ;
    SHAPE ABUTMENT ;
    PORT
      LAYER metal3 ;
      RECT 813.645 0.000 813.715 0.070 ;
    END
  END w0_wd_in[318]
  PIN w0_wd_in[319]
    DIRECTION INPUT ;
    USE SIGNAL ;
    SHAPE ABUTMENT ;
    PORT
      LAYER metal3 ;
      RECT 813.785 0.000 813.855 0.070 ;
    END
  END w0_wd_in[319]
  PIN w0_wd_in[320]
    DIRECTION INPUT ;
    USE SIGNAL ;
    SHAPE ABUTMENT ;
    PORT
      LAYER metal3 ;
      RECT 813.925 0.000 813.995 0.070 ;
    END
  END w0_wd_in[320]
  PIN w0_wd_in[321]
    DIRECTION INPUT ;
    USE SIGNAL ;
    SHAPE ABUTMENT ;
    PORT
      LAYER metal3 ;
      RECT 814.065 0.000 814.135 0.070 ;
    END
  END w0_wd_in[321]
  PIN w0_wd_in[322]
    DIRECTION INPUT ;
    USE SIGNAL ;
    SHAPE ABUTMENT ;
    PORT
      LAYER metal3 ;
      RECT 814.205 0.000 814.275 0.070 ;
    END
  END w0_wd_in[322]
  PIN w0_wd_in[323]
    DIRECTION INPUT ;
    USE SIGNAL ;
    SHAPE ABUTMENT ;
    PORT
      LAYER metal3 ;
      RECT 814.345 0.000 814.415 0.070 ;
    END
  END w0_wd_in[323]
  PIN w0_wd_in[324]
    DIRECTION INPUT ;
    USE SIGNAL ;
    SHAPE ABUTMENT ;
    PORT
      LAYER metal3 ;
      RECT 814.485 0.000 814.555 0.070 ;
    END
  END w0_wd_in[324]
  PIN w0_wd_in[325]
    DIRECTION INPUT ;
    USE SIGNAL ;
    SHAPE ABUTMENT ;
    PORT
      LAYER metal3 ;
      RECT 814.625 0.000 814.695 0.070 ;
    END
  END w0_wd_in[325]
  PIN w0_wd_in[326]
    DIRECTION INPUT ;
    USE SIGNAL ;
    SHAPE ABUTMENT ;
    PORT
      LAYER metal3 ;
      RECT 814.765 0.000 814.835 0.070 ;
    END
  END w0_wd_in[326]
  PIN w0_wd_in[327]
    DIRECTION INPUT ;
    USE SIGNAL ;
    SHAPE ABUTMENT ;
    PORT
      LAYER metal3 ;
      RECT 814.905 0.000 814.975 0.070 ;
    END
  END w0_wd_in[327]
  PIN w0_wd_in[328]
    DIRECTION INPUT ;
    USE SIGNAL ;
    SHAPE ABUTMENT ;
    PORT
      LAYER metal3 ;
      RECT 815.045 0.000 815.115 0.070 ;
    END
  END w0_wd_in[328]
  PIN w0_wd_in[329]
    DIRECTION INPUT ;
    USE SIGNAL ;
    SHAPE ABUTMENT ;
    PORT
      LAYER metal3 ;
      RECT 815.185 0.000 815.255 0.070 ;
    END
  END w0_wd_in[329]
  PIN w0_wd_in[330]
    DIRECTION INPUT ;
    USE SIGNAL ;
    SHAPE ABUTMENT ;
    PORT
      LAYER metal3 ;
      RECT 815.325 0.000 815.395 0.070 ;
    END
  END w0_wd_in[330]
  PIN w0_wd_in[331]
    DIRECTION INPUT ;
    USE SIGNAL ;
    SHAPE ABUTMENT ;
    PORT
      LAYER metal3 ;
      RECT 815.465 0.000 815.535 0.070 ;
    END
  END w0_wd_in[331]
  PIN w0_wd_in[332]
    DIRECTION INPUT ;
    USE SIGNAL ;
    SHAPE ABUTMENT ;
    PORT
      LAYER metal3 ;
      RECT 815.605 0.000 815.675 0.070 ;
    END
  END w0_wd_in[332]
  PIN w0_wd_in[333]
    DIRECTION INPUT ;
    USE SIGNAL ;
    SHAPE ABUTMENT ;
    PORT
      LAYER metal3 ;
      RECT 815.745 0.000 815.815 0.070 ;
    END
  END w0_wd_in[333]
  PIN w0_wd_in[334]
    DIRECTION INPUT ;
    USE SIGNAL ;
    SHAPE ABUTMENT ;
    PORT
      LAYER metal3 ;
      RECT 815.885 0.000 815.955 0.070 ;
    END
  END w0_wd_in[334]
  PIN w0_wd_in[335]
    DIRECTION INPUT ;
    USE SIGNAL ;
    SHAPE ABUTMENT ;
    PORT
      LAYER metal3 ;
      RECT 816.025 0.000 816.095 0.070 ;
    END
  END w0_wd_in[335]
  PIN w0_wd_in[336]
    DIRECTION INPUT ;
    USE SIGNAL ;
    SHAPE ABUTMENT ;
    PORT
      LAYER metal3 ;
      RECT 816.165 0.000 816.235 0.070 ;
    END
  END w0_wd_in[336]
  PIN w0_wd_in[337]
    DIRECTION INPUT ;
    USE SIGNAL ;
    SHAPE ABUTMENT ;
    PORT
      LAYER metal3 ;
      RECT 816.305 0.000 816.375 0.070 ;
    END
  END w0_wd_in[337]
  PIN w0_wd_in[338]
    DIRECTION INPUT ;
    USE SIGNAL ;
    SHAPE ABUTMENT ;
    PORT
      LAYER metal3 ;
      RECT 816.445 0.000 816.515 0.070 ;
    END
  END w0_wd_in[338]
  PIN w0_wd_in[339]
    DIRECTION INPUT ;
    USE SIGNAL ;
    SHAPE ABUTMENT ;
    PORT
      LAYER metal3 ;
      RECT 816.585 0.000 816.655 0.070 ;
    END
  END w0_wd_in[339]
  PIN w0_wd_in[340]
    DIRECTION INPUT ;
    USE SIGNAL ;
    SHAPE ABUTMENT ;
    PORT
      LAYER metal3 ;
      RECT 816.725 0.000 816.795 0.070 ;
    END
  END w0_wd_in[340]
  PIN w0_wd_in[341]
    DIRECTION INPUT ;
    USE SIGNAL ;
    SHAPE ABUTMENT ;
    PORT
      LAYER metal3 ;
      RECT 816.865 0.000 816.935 0.070 ;
    END
  END w0_wd_in[341]
  PIN w0_wd_in[342]
    DIRECTION INPUT ;
    USE SIGNAL ;
    SHAPE ABUTMENT ;
    PORT
      LAYER metal3 ;
      RECT 817.005 0.000 817.075 0.070 ;
    END
  END w0_wd_in[342]
  PIN w0_wd_in[343]
    DIRECTION INPUT ;
    USE SIGNAL ;
    SHAPE ABUTMENT ;
    PORT
      LAYER metal3 ;
      RECT 817.145 0.000 817.215 0.070 ;
    END
  END w0_wd_in[343]
  PIN w0_wd_in[344]
    DIRECTION INPUT ;
    USE SIGNAL ;
    SHAPE ABUTMENT ;
    PORT
      LAYER metal3 ;
      RECT 817.285 0.000 817.355 0.070 ;
    END
  END w0_wd_in[344]
  PIN w0_wd_in[345]
    DIRECTION INPUT ;
    USE SIGNAL ;
    SHAPE ABUTMENT ;
    PORT
      LAYER metal3 ;
      RECT 817.425 0.000 817.495 0.070 ;
    END
  END w0_wd_in[345]
  PIN w0_wd_in[346]
    DIRECTION INPUT ;
    USE SIGNAL ;
    SHAPE ABUTMENT ;
    PORT
      LAYER metal3 ;
      RECT 817.565 0.000 817.635 0.070 ;
    END
  END w0_wd_in[346]
  PIN w0_wd_in[347]
    DIRECTION INPUT ;
    USE SIGNAL ;
    SHAPE ABUTMENT ;
    PORT
      LAYER metal3 ;
      RECT 817.705 0.000 817.775 0.070 ;
    END
  END w0_wd_in[347]
  PIN w0_wd_in[348]
    DIRECTION INPUT ;
    USE SIGNAL ;
    SHAPE ABUTMENT ;
    PORT
      LAYER metal3 ;
      RECT 817.845 0.000 817.915 0.070 ;
    END
  END w0_wd_in[348]
  PIN w0_wd_in[349]
    DIRECTION INPUT ;
    USE SIGNAL ;
    SHAPE ABUTMENT ;
    PORT
      LAYER metal3 ;
      RECT 817.985 0.000 818.055 0.070 ;
    END
  END w0_wd_in[349]
  PIN w0_wd_in[350]
    DIRECTION INPUT ;
    USE SIGNAL ;
    SHAPE ABUTMENT ;
    PORT
      LAYER metal3 ;
      RECT 818.125 0.000 818.195 0.070 ;
    END
  END w0_wd_in[350]
  PIN w0_wd_in[351]
    DIRECTION INPUT ;
    USE SIGNAL ;
    SHAPE ABUTMENT ;
    PORT
      LAYER metal3 ;
      RECT 818.265 0.000 818.335 0.070 ;
    END
  END w0_wd_in[351]
  PIN w0_wd_in[352]
    DIRECTION INPUT ;
    USE SIGNAL ;
    SHAPE ABUTMENT ;
    PORT
      LAYER metal3 ;
      RECT 818.405 0.000 818.475 0.070 ;
    END
  END w0_wd_in[352]
  PIN w0_wd_in[353]
    DIRECTION INPUT ;
    USE SIGNAL ;
    SHAPE ABUTMENT ;
    PORT
      LAYER metal3 ;
      RECT 818.545 0.000 818.615 0.070 ;
    END
  END w0_wd_in[353]
  PIN w0_wd_in[354]
    DIRECTION INPUT ;
    USE SIGNAL ;
    SHAPE ABUTMENT ;
    PORT
      LAYER metal3 ;
      RECT 818.685 0.000 818.755 0.070 ;
    END
  END w0_wd_in[354]
  PIN w0_wd_in[355]
    DIRECTION INPUT ;
    USE SIGNAL ;
    SHAPE ABUTMENT ;
    PORT
      LAYER metal3 ;
      RECT 818.825 0.000 818.895 0.070 ;
    END
  END w0_wd_in[355]
  PIN w0_wd_in[356]
    DIRECTION INPUT ;
    USE SIGNAL ;
    SHAPE ABUTMENT ;
    PORT
      LAYER metal3 ;
      RECT 818.965 0.000 819.035 0.070 ;
    END
  END w0_wd_in[356]
  PIN w0_wd_in[357]
    DIRECTION INPUT ;
    USE SIGNAL ;
    SHAPE ABUTMENT ;
    PORT
      LAYER metal3 ;
      RECT 819.105 0.000 819.175 0.070 ;
    END
  END w0_wd_in[357]
  PIN w0_wd_in[358]
    DIRECTION INPUT ;
    USE SIGNAL ;
    SHAPE ABUTMENT ;
    PORT
      LAYER metal3 ;
      RECT 819.245 0.000 819.315 0.070 ;
    END
  END w0_wd_in[358]
  PIN w0_wd_in[359]
    DIRECTION INPUT ;
    USE SIGNAL ;
    SHAPE ABUTMENT ;
    PORT
      LAYER metal3 ;
      RECT 819.385 0.000 819.455 0.070 ;
    END
  END w0_wd_in[359]
  PIN w0_wd_in[360]
    DIRECTION INPUT ;
    USE SIGNAL ;
    SHAPE ABUTMENT ;
    PORT
      LAYER metal3 ;
      RECT 819.525 0.000 819.595 0.070 ;
    END
  END w0_wd_in[360]
  PIN w0_wd_in[361]
    DIRECTION INPUT ;
    USE SIGNAL ;
    SHAPE ABUTMENT ;
    PORT
      LAYER metal3 ;
      RECT 819.665 0.000 819.735 0.070 ;
    END
  END w0_wd_in[361]
  PIN w0_wd_in[362]
    DIRECTION INPUT ;
    USE SIGNAL ;
    SHAPE ABUTMENT ;
    PORT
      LAYER metal3 ;
      RECT 819.805 0.000 819.875 0.070 ;
    END
  END w0_wd_in[362]
  PIN w0_wd_in[363]
    DIRECTION INPUT ;
    USE SIGNAL ;
    SHAPE ABUTMENT ;
    PORT
      LAYER metal3 ;
      RECT 819.945 0.000 820.015 0.070 ;
    END
  END w0_wd_in[363]
  PIN w0_wd_in[364]
    DIRECTION INPUT ;
    USE SIGNAL ;
    SHAPE ABUTMENT ;
    PORT
      LAYER metal3 ;
      RECT 820.085 0.000 820.155 0.070 ;
    END
  END w0_wd_in[364]
  PIN w0_wd_in[365]
    DIRECTION INPUT ;
    USE SIGNAL ;
    SHAPE ABUTMENT ;
    PORT
      LAYER metal3 ;
      RECT 820.225 0.000 820.295 0.070 ;
    END
  END w0_wd_in[365]
  PIN w0_wd_in[366]
    DIRECTION INPUT ;
    USE SIGNAL ;
    SHAPE ABUTMENT ;
    PORT
      LAYER metal3 ;
      RECT 820.365 0.000 820.435 0.070 ;
    END
  END w0_wd_in[366]
  PIN w0_wd_in[367]
    DIRECTION INPUT ;
    USE SIGNAL ;
    SHAPE ABUTMENT ;
    PORT
      LAYER metal3 ;
      RECT 820.505 0.000 820.575 0.070 ;
    END
  END w0_wd_in[367]
  PIN w0_wd_in[368]
    DIRECTION INPUT ;
    USE SIGNAL ;
    SHAPE ABUTMENT ;
    PORT
      LAYER metal3 ;
      RECT 820.645 0.000 820.715 0.070 ;
    END
  END w0_wd_in[368]
  PIN w0_wd_in[369]
    DIRECTION INPUT ;
    USE SIGNAL ;
    SHAPE ABUTMENT ;
    PORT
      LAYER metal3 ;
      RECT 820.785 0.000 820.855 0.070 ;
    END
  END w0_wd_in[369]
  PIN w0_wd_in[370]
    DIRECTION INPUT ;
    USE SIGNAL ;
    SHAPE ABUTMENT ;
    PORT
      LAYER metal3 ;
      RECT 820.925 0.000 820.995 0.070 ;
    END
  END w0_wd_in[370]
  PIN w0_wd_in[371]
    DIRECTION INPUT ;
    USE SIGNAL ;
    SHAPE ABUTMENT ;
    PORT
      LAYER metal3 ;
      RECT 821.065 0.000 821.135 0.070 ;
    END
  END w0_wd_in[371]
  PIN w0_wd_in[372]
    DIRECTION INPUT ;
    USE SIGNAL ;
    SHAPE ABUTMENT ;
    PORT
      LAYER metal3 ;
      RECT 821.205 0.000 821.275 0.070 ;
    END
  END w0_wd_in[372]
  PIN w0_wd_in[373]
    DIRECTION INPUT ;
    USE SIGNAL ;
    SHAPE ABUTMENT ;
    PORT
      LAYER metal3 ;
      RECT 821.345 0.000 821.415 0.070 ;
    END
  END w0_wd_in[373]
  PIN w0_wd_in[374]
    DIRECTION INPUT ;
    USE SIGNAL ;
    SHAPE ABUTMENT ;
    PORT
      LAYER metal3 ;
      RECT 821.485 0.000 821.555 0.070 ;
    END
  END w0_wd_in[374]
  PIN w0_wd_in[375]
    DIRECTION INPUT ;
    USE SIGNAL ;
    SHAPE ABUTMENT ;
    PORT
      LAYER metal3 ;
      RECT 821.625 0.000 821.695 0.070 ;
    END
  END w0_wd_in[375]
  PIN w0_wd_in[376]
    DIRECTION INPUT ;
    USE SIGNAL ;
    SHAPE ABUTMENT ;
    PORT
      LAYER metal3 ;
      RECT 821.765 0.000 821.835 0.070 ;
    END
  END w0_wd_in[376]
  PIN w0_wd_in[377]
    DIRECTION INPUT ;
    USE SIGNAL ;
    SHAPE ABUTMENT ;
    PORT
      LAYER metal3 ;
      RECT 821.905 0.000 821.975 0.070 ;
    END
  END w0_wd_in[377]
  PIN w0_wd_in[378]
    DIRECTION INPUT ;
    USE SIGNAL ;
    SHAPE ABUTMENT ;
    PORT
      LAYER metal3 ;
      RECT 822.045 0.000 822.115 0.070 ;
    END
  END w0_wd_in[378]
  PIN w0_wd_in[379]
    DIRECTION INPUT ;
    USE SIGNAL ;
    SHAPE ABUTMENT ;
    PORT
      LAYER metal3 ;
      RECT 822.185 0.000 822.255 0.070 ;
    END
  END w0_wd_in[379]
  PIN w0_wd_in[380]
    DIRECTION INPUT ;
    USE SIGNAL ;
    SHAPE ABUTMENT ;
    PORT
      LAYER metal3 ;
      RECT 822.325 0.000 822.395 0.070 ;
    END
  END w0_wd_in[380]
  PIN w0_wd_in[381]
    DIRECTION INPUT ;
    USE SIGNAL ;
    SHAPE ABUTMENT ;
    PORT
      LAYER metal3 ;
      RECT 822.465 0.000 822.535 0.070 ;
    END
  END w0_wd_in[381]
  PIN w0_wd_in[382]
    DIRECTION INPUT ;
    USE SIGNAL ;
    SHAPE ABUTMENT ;
    PORT
      LAYER metal3 ;
      RECT 822.605 0.000 822.675 0.070 ;
    END
  END w0_wd_in[382]
  PIN w0_wd_in[383]
    DIRECTION INPUT ;
    USE SIGNAL ;
    SHAPE ABUTMENT ;
    PORT
      LAYER metal3 ;
      RECT 822.745 0.000 822.815 0.070 ;
    END
  END w0_wd_in[383]
  PIN w0_wd_in[384]
    DIRECTION INPUT ;
    USE SIGNAL ;
    SHAPE ABUTMENT ;
    PORT
      LAYER metal3 ;
      RECT 822.885 0.000 822.955 0.070 ;
    END
  END w0_wd_in[384]
  PIN w0_wd_in[385]
    DIRECTION INPUT ;
    USE SIGNAL ;
    SHAPE ABUTMENT ;
    PORT
      LAYER metal3 ;
      RECT 823.025 0.000 823.095 0.070 ;
    END
  END w0_wd_in[385]
  PIN w0_wd_in[386]
    DIRECTION INPUT ;
    USE SIGNAL ;
    SHAPE ABUTMENT ;
    PORT
      LAYER metal3 ;
      RECT 823.165 0.000 823.235 0.070 ;
    END
  END w0_wd_in[386]
  PIN w0_wd_in[387]
    DIRECTION INPUT ;
    USE SIGNAL ;
    SHAPE ABUTMENT ;
    PORT
      LAYER metal3 ;
      RECT 823.305 0.000 823.375 0.070 ;
    END
  END w0_wd_in[387]
  PIN w0_wd_in[388]
    DIRECTION INPUT ;
    USE SIGNAL ;
    SHAPE ABUTMENT ;
    PORT
      LAYER metal3 ;
      RECT 823.445 0.000 823.515 0.070 ;
    END
  END w0_wd_in[388]
  PIN w0_wd_in[389]
    DIRECTION INPUT ;
    USE SIGNAL ;
    SHAPE ABUTMENT ;
    PORT
      LAYER metal3 ;
      RECT 823.585 0.000 823.655 0.070 ;
    END
  END w0_wd_in[389]
  PIN w0_wd_in[390]
    DIRECTION INPUT ;
    USE SIGNAL ;
    SHAPE ABUTMENT ;
    PORT
      LAYER metal3 ;
      RECT 823.725 0.000 823.795 0.070 ;
    END
  END w0_wd_in[390]
  PIN w0_wd_in[391]
    DIRECTION INPUT ;
    USE SIGNAL ;
    SHAPE ABUTMENT ;
    PORT
      LAYER metal3 ;
      RECT 823.865 0.000 823.935 0.070 ;
    END
  END w0_wd_in[391]
  PIN w0_wd_in[392]
    DIRECTION INPUT ;
    USE SIGNAL ;
    SHAPE ABUTMENT ;
    PORT
      LAYER metal3 ;
      RECT 824.005 0.000 824.075 0.070 ;
    END
  END w0_wd_in[392]
  PIN w0_wd_in[393]
    DIRECTION INPUT ;
    USE SIGNAL ;
    SHAPE ABUTMENT ;
    PORT
      LAYER metal3 ;
      RECT 824.145 0.000 824.215 0.070 ;
    END
  END w0_wd_in[393]
  PIN w0_wd_in[394]
    DIRECTION INPUT ;
    USE SIGNAL ;
    SHAPE ABUTMENT ;
    PORT
      LAYER metal3 ;
      RECT 824.285 0.000 824.355 0.070 ;
    END
  END w0_wd_in[394]
  PIN w0_wd_in[395]
    DIRECTION INPUT ;
    USE SIGNAL ;
    SHAPE ABUTMENT ;
    PORT
      LAYER metal3 ;
      RECT 824.425 0.000 824.495 0.070 ;
    END
  END w0_wd_in[395]
  PIN w0_wd_in[396]
    DIRECTION INPUT ;
    USE SIGNAL ;
    SHAPE ABUTMENT ;
    PORT
      LAYER metal3 ;
      RECT 824.565 0.000 824.635 0.070 ;
    END
  END w0_wd_in[396]
  PIN w0_wd_in[397]
    DIRECTION INPUT ;
    USE SIGNAL ;
    SHAPE ABUTMENT ;
    PORT
      LAYER metal3 ;
      RECT 824.705 0.000 824.775 0.070 ;
    END
  END w0_wd_in[397]
  PIN w0_wd_in[398]
    DIRECTION INPUT ;
    USE SIGNAL ;
    SHAPE ABUTMENT ;
    PORT
      LAYER metal3 ;
      RECT 824.845 0.000 824.915 0.070 ;
    END
  END w0_wd_in[398]
  PIN w0_wd_in[399]
    DIRECTION INPUT ;
    USE SIGNAL ;
    SHAPE ABUTMENT ;
    PORT
      LAYER metal3 ;
      RECT 824.985 0.000 825.055 0.070 ;
    END
  END w0_wd_in[399]
  PIN w0_wd_in[400]
    DIRECTION INPUT ;
    USE SIGNAL ;
    SHAPE ABUTMENT ;
    PORT
      LAYER metal3 ;
      RECT 825.125 0.000 825.195 0.070 ;
    END
  END w0_wd_in[400]
  PIN w0_wd_in[401]
    DIRECTION INPUT ;
    USE SIGNAL ;
    SHAPE ABUTMENT ;
    PORT
      LAYER metal3 ;
      RECT 825.265 0.000 825.335 0.070 ;
    END
  END w0_wd_in[401]
  PIN w0_wd_in[402]
    DIRECTION INPUT ;
    USE SIGNAL ;
    SHAPE ABUTMENT ;
    PORT
      LAYER metal3 ;
      RECT 825.405 0.000 825.475 0.070 ;
    END
  END w0_wd_in[402]
  PIN w0_wd_in[403]
    DIRECTION INPUT ;
    USE SIGNAL ;
    SHAPE ABUTMENT ;
    PORT
      LAYER metal3 ;
      RECT 825.545 0.000 825.615 0.070 ;
    END
  END w0_wd_in[403]
  PIN w0_wd_in[404]
    DIRECTION INPUT ;
    USE SIGNAL ;
    SHAPE ABUTMENT ;
    PORT
      LAYER metal3 ;
      RECT 825.685 0.000 825.755 0.070 ;
    END
  END w0_wd_in[404]
  PIN w0_wd_in[405]
    DIRECTION INPUT ;
    USE SIGNAL ;
    SHAPE ABUTMENT ;
    PORT
      LAYER metal3 ;
      RECT 825.825 0.000 825.895 0.070 ;
    END
  END w0_wd_in[405]
  PIN w0_wd_in[406]
    DIRECTION INPUT ;
    USE SIGNAL ;
    SHAPE ABUTMENT ;
    PORT
      LAYER metal3 ;
      RECT 825.965 0.000 826.035 0.070 ;
    END
  END w0_wd_in[406]
  PIN w0_wd_in[407]
    DIRECTION INPUT ;
    USE SIGNAL ;
    SHAPE ABUTMENT ;
    PORT
      LAYER metal3 ;
      RECT 826.105 0.000 826.175 0.070 ;
    END
  END w0_wd_in[407]
  PIN w0_wd_in[408]
    DIRECTION INPUT ;
    USE SIGNAL ;
    SHAPE ABUTMENT ;
    PORT
      LAYER metal3 ;
      RECT 826.245 0.000 826.315 0.070 ;
    END
  END w0_wd_in[408]
  PIN w0_wd_in[409]
    DIRECTION INPUT ;
    USE SIGNAL ;
    SHAPE ABUTMENT ;
    PORT
      LAYER metal3 ;
      RECT 826.385 0.000 826.455 0.070 ;
    END
  END w0_wd_in[409]
  PIN w0_wd_in[410]
    DIRECTION INPUT ;
    USE SIGNAL ;
    SHAPE ABUTMENT ;
    PORT
      LAYER metal3 ;
      RECT 826.525 0.000 826.595 0.070 ;
    END
  END w0_wd_in[410]
  PIN w0_wd_in[411]
    DIRECTION INPUT ;
    USE SIGNAL ;
    SHAPE ABUTMENT ;
    PORT
      LAYER metal3 ;
      RECT 826.665 0.000 826.735 0.070 ;
    END
  END w0_wd_in[411]
  PIN w0_wd_in[412]
    DIRECTION INPUT ;
    USE SIGNAL ;
    SHAPE ABUTMENT ;
    PORT
      LAYER metal3 ;
      RECT 826.805 0.000 826.875 0.070 ;
    END
  END w0_wd_in[412]
  PIN w0_wd_in[413]
    DIRECTION INPUT ;
    USE SIGNAL ;
    SHAPE ABUTMENT ;
    PORT
      LAYER metal3 ;
      RECT 826.945 0.000 827.015 0.070 ;
    END
  END w0_wd_in[413]
  PIN w0_wd_in[414]
    DIRECTION INPUT ;
    USE SIGNAL ;
    SHAPE ABUTMENT ;
    PORT
      LAYER metal3 ;
      RECT 827.085 0.000 827.155 0.070 ;
    END
  END w0_wd_in[414]
  PIN w0_wd_in[415]
    DIRECTION INPUT ;
    USE SIGNAL ;
    SHAPE ABUTMENT ;
    PORT
      LAYER metal3 ;
      RECT 827.225 0.000 827.295 0.070 ;
    END
  END w0_wd_in[415]
  PIN w0_wd_in[416]
    DIRECTION INPUT ;
    USE SIGNAL ;
    SHAPE ABUTMENT ;
    PORT
      LAYER metal3 ;
      RECT 827.365 0.000 827.435 0.070 ;
    END
  END w0_wd_in[416]
  PIN w0_wd_in[417]
    DIRECTION INPUT ;
    USE SIGNAL ;
    SHAPE ABUTMENT ;
    PORT
      LAYER metal3 ;
      RECT 827.505 0.000 827.575 0.070 ;
    END
  END w0_wd_in[417]
  PIN w0_wd_in[418]
    DIRECTION INPUT ;
    USE SIGNAL ;
    SHAPE ABUTMENT ;
    PORT
      LAYER metal3 ;
      RECT 827.645 0.000 827.715 0.070 ;
    END
  END w0_wd_in[418]
  PIN w0_wd_in[419]
    DIRECTION INPUT ;
    USE SIGNAL ;
    SHAPE ABUTMENT ;
    PORT
      LAYER metal3 ;
      RECT 827.785 0.000 827.855 0.070 ;
    END
  END w0_wd_in[419]
  PIN w0_wd_in[420]
    DIRECTION INPUT ;
    USE SIGNAL ;
    SHAPE ABUTMENT ;
    PORT
      LAYER metal3 ;
      RECT 827.925 0.000 827.995 0.070 ;
    END
  END w0_wd_in[420]
  PIN w0_wd_in[421]
    DIRECTION INPUT ;
    USE SIGNAL ;
    SHAPE ABUTMENT ;
    PORT
      LAYER metal3 ;
      RECT 828.065 0.000 828.135 0.070 ;
    END
  END w0_wd_in[421]
  PIN w0_wd_in[422]
    DIRECTION INPUT ;
    USE SIGNAL ;
    SHAPE ABUTMENT ;
    PORT
      LAYER metal3 ;
      RECT 828.205 0.000 828.275 0.070 ;
    END
  END w0_wd_in[422]
  PIN w0_wd_in[423]
    DIRECTION INPUT ;
    USE SIGNAL ;
    SHAPE ABUTMENT ;
    PORT
      LAYER metal3 ;
      RECT 828.345 0.000 828.415 0.070 ;
    END
  END w0_wd_in[423]
  PIN w0_wd_in[424]
    DIRECTION INPUT ;
    USE SIGNAL ;
    SHAPE ABUTMENT ;
    PORT
      LAYER metal3 ;
      RECT 828.485 0.000 828.555 0.070 ;
    END
  END w0_wd_in[424]
  PIN w0_wd_in[425]
    DIRECTION INPUT ;
    USE SIGNAL ;
    SHAPE ABUTMENT ;
    PORT
      LAYER metal3 ;
      RECT 828.625 0.000 828.695 0.070 ;
    END
  END w0_wd_in[425]
  PIN w0_wd_in[426]
    DIRECTION INPUT ;
    USE SIGNAL ;
    SHAPE ABUTMENT ;
    PORT
      LAYER metal3 ;
      RECT 828.765 0.000 828.835 0.070 ;
    END
  END w0_wd_in[426]
  PIN w0_wd_in[427]
    DIRECTION INPUT ;
    USE SIGNAL ;
    SHAPE ABUTMENT ;
    PORT
      LAYER metal3 ;
      RECT 828.905 0.000 828.975 0.070 ;
    END
  END w0_wd_in[427]
  PIN w0_wd_in[428]
    DIRECTION INPUT ;
    USE SIGNAL ;
    SHAPE ABUTMENT ;
    PORT
      LAYER metal3 ;
      RECT 829.045 0.000 829.115 0.070 ;
    END
  END w0_wd_in[428]
  PIN w0_wd_in[429]
    DIRECTION INPUT ;
    USE SIGNAL ;
    SHAPE ABUTMENT ;
    PORT
      LAYER metal3 ;
      RECT 829.185 0.000 829.255 0.070 ;
    END
  END w0_wd_in[429]
  PIN w0_wd_in[430]
    DIRECTION INPUT ;
    USE SIGNAL ;
    SHAPE ABUTMENT ;
    PORT
      LAYER metal3 ;
      RECT 829.325 0.000 829.395 0.070 ;
    END
  END w0_wd_in[430]
  PIN w0_wd_in[431]
    DIRECTION INPUT ;
    USE SIGNAL ;
    SHAPE ABUTMENT ;
    PORT
      LAYER metal3 ;
      RECT 829.465 0.000 829.535 0.070 ;
    END
  END w0_wd_in[431]
  PIN w0_wd_in[432]
    DIRECTION INPUT ;
    USE SIGNAL ;
    SHAPE ABUTMENT ;
    PORT
      LAYER metal3 ;
      RECT 829.605 0.000 829.675 0.070 ;
    END
  END w0_wd_in[432]
  PIN w0_wd_in[433]
    DIRECTION INPUT ;
    USE SIGNAL ;
    SHAPE ABUTMENT ;
    PORT
      LAYER metal3 ;
      RECT 829.745 0.000 829.815 0.070 ;
    END
  END w0_wd_in[433]
  PIN w0_wd_in[434]
    DIRECTION INPUT ;
    USE SIGNAL ;
    SHAPE ABUTMENT ;
    PORT
      LAYER metal3 ;
      RECT 829.885 0.000 829.955 0.070 ;
    END
  END w0_wd_in[434]
  PIN w0_wd_in[435]
    DIRECTION INPUT ;
    USE SIGNAL ;
    SHAPE ABUTMENT ;
    PORT
      LAYER metal3 ;
      RECT 830.025 0.000 830.095 0.070 ;
    END
  END w0_wd_in[435]
  PIN w0_wd_in[436]
    DIRECTION INPUT ;
    USE SIGNAL ;
    SHAPE ABUTMENT ;
    PORT
      LAYER metal3 ;
      RECT 830.165 0.000 830.235 0.070 ;
    END
  END w0_wd_in[436]
  PIN w0_wd_in[437]
    DIRECTION INPUT ;
    USE SIGNAL ;
    SHAPE ABUTMENT ;
    PORT
      LAYER metal3 ;
      RECT 830.305 0.000 830.375 0.070 ;
    END
  END w0_wd_in[437]
  PIN w0_wd_in[438]
    DIRECTION INPUT ;
    USE SIGNAL ;
    SHAPE ABUTMENT ;
    PORT
      LAYER metal3 ;
      RECT 830.445 0.000 830.515 0.070 ;
    END
  END w0_wd_in[438]
  PIN w0_wd_in[439]
    DIRECTION INPUT ;
    USE SIGNAL ;
    SHAPE ABUTMENT ;
    PORT
      LAYER metal3 ;
      RECT 830.585 0.000 830.655 0.070 ;
    END
  END w0_wd_in[439]
  PIN w0_wd_in[440]
    DIRECTION INPUT ;
    USE SIGNAL ;
    SHAPE ABUTMENT ;
    PORT
      LAYER metal3 ;
      RECT 830.725 0.000 830.795 0.070 ;
    END
  END w0_wd_in[440]
  PIN w0_wd_in[441]
    DIRECTION INPUT ;
    USE SIGNAL ;
    SHAPE ABUTMENT ;
    PORT
      LAYER metal3 ;
      RECT 830.865 0.000 830.935 0.070 ;
    END
  END w0_wd_in[441]
  PIN w0_wd_in[442]
    DIRECTION INPUT ;
    USE SIGNAL ;
    SHAPE ABUTMENT ;
    PORT
      LAYER metal3 ;
      RECT 831.005 0.000 831.075 0.070 ;
    END
  END w0_wd_in[442]
  PIN w0_wd_in[443]
    DIRECTION INPUT ;
    USE SIGNAL ;
    SHAPE ABUTMENT ;
    PORT
      LAYER metal3 ;
      RECT 831.145 0.000 831.215 0.070 ;
    END
  END w0_wd_in[443]
  PIN w0_wd_in[444]
    DIRECTION INPUT ;
    USE SIGNAL ;
    SHAPE ABUTMENT ;
    PORT
      LAYER metal3 ;
      RECT 831.285 0.000 831.355 0.070 ;
    END
  END w0_wd_in[444]
  PIN w0_wd_in[445]
    DIRECTION INPUT ;
    USE SIGNAL ;
    SHAPE ABUTMENT ;
    PORT
      LAYER metal3 ;
      RECT 831.425 0.000 831.495 0.070 ;
    END
  END w0_wd_in[445]
  PIN w0_wd_in[446]
    DIRECTION INPUT ;
    USE SIGNAL ;
    SHAPE ABUTMENT ;
    PORT
      LAYER metal3 ;
      RECT 831.565 0.000 831.635 0.070 ;
    END
  END w0_wd_in[446]
  PIN w0_wd_in[447]
    DIRECTION INPUT ;
    USE SIGNAL ;
    SHAPE ABUTMENT ;
    PORT
      LAYER metal3 ;
      RECT 831.705 0.000 831.775 0.070 ;
    END
  END w0_wd_in[447]
  PIN w0_wd_in[448]
    DIRECTION INPUT ;
    USE SIGNAL ;
    SHAPE ABUTMENT ;
    PORT
      LAYER metal3 ;
      RECT 831.845 0.000 831.915 0.070 ;
    END
  END w0_wd_in[448]
  PIN w0_wd_in[449]
    DIRECTION INPUT ;
    USE SIGNAL ;
    SHAPE ABUTMENT ;
    PORT
      LAYER metal3 ;
      RECT 831.985 0.000 832.055 0.070 ;
    END
  END w0_wd_in[449]
  PIN w0_wd_in[450]
    DIRECTION INPUT ;
    USE SIGNAL ;
    SHAPE ABUTMENT ;
    PORT
      LAYER metal3 ;
      RECT 832.125 0.000 832.195 0.070 ;
    END
  END w0_wd_in[450]
  PIN w0_wd_in[451]
    DIRECTION INPUT ;
    USE SIGNAL ;
    SHAPE ABUTMENT ;
    PORT
      LAYER metal3 ;
      RECT 832.265 0.000 832.335 0.070 ;
    END
  END w0_wd_in[451]
  PIN w0_wd_in[452]
    DIRECTION INPUT ;
    USE SIGNAL ;
    SHAPE ABUTMENT ;
    PORT
      LAYER metal3 ;
      RECT 832.405 0.000 832.475 0.070 ;
    END
  END w0_wd_in[452]
  PIN w0_wd_in[453]
    DIRECTION INPUT ;
    USE SIGNAL ;
    SHAPE ABUTMENT ;
    PORT
      LAYER metal3 ;
      RECT 832.545 0.000 832.615 0.070 ;
    END
  END w0_wd_in[453]
  PIN w0_wd_in[454]
    DIRECTION INPUT ;
    USE SIGNAL ;
    SHAPE ABUTMENT ;
    PORT
      LAYER metal3 ;
      RECT 832.685 0.000 832.755 0.070 ;
    END
  END w0_wd_in[454]
  PIN w0_wd_in[455]
    DIRECTION INPUT ;
    USE SIGNAL ;
    SHAPE ABUTMENT ;
    PORT
      LAYER metal3 ;
      RECT 832.825 0.000 832.895 0.070 ;
    END
  END w0_wd_in[455]
  PIN w0_wd_in[456]
    DIRECTION INPUT ;
    USE SIGNAL ;
    SHAPE ABUTMENT ;
    PORT
      LAYER metal3 ;
      RECT 832.965 0.000 833.035 0.070 ;
    END
  END w0_wd_in[456]
  PIN w0_wd_in[457]
    DIRECTION INPUT ;
    USE SIGNAL ;
    SHAPE ABUTMENT ;
    PORT
      LAYER metal3 ;
      RECT 833.105 0.000 833.175 0.070 ;
    END
  END w0_wd_in[457]
  PIN w0_wd_in[458]
    DIRECTION INPUT ;
    USE SIGNAL ;
    SHAPE ABUTMENT ;
    PORT
      LAYER metal3 ;
      RECT 833.245 0.000 833.315 0.070 ;
    END
  END w0_wd_in[458]
  PIN w0_wd_in[459]
    DIRECTION INPUT ;
    USE SIGNAL ;
    SHAPE ABUTMENT ;
    PORT
      LAYER metal3 ;
      RECT 833.385 0.000 833.455 0.070 ;
    END
  END w0_wd_in[459]
  PIN w0_wd_in[460]
    DIRECTION INPUT ;
    USE SIGNAL ;
    SHAPE ABUTMENT ;
    PORT
      LAYER metal3 ;
      RECT 833.525 0.000 833.595 0.070 ;
    END
  END w0_wd_in[460]
  PIN w0_wd_in[461]
    DIRECTION INPUT ;
    USE SIGNAL ;
    SHAPE ABUTMENT ;
    PORT
      LAYER metal3 ;
      RECT 833.665 0.000 833.735 0.070 ;
    END
  END w0_wd_in[461]
  PIN w0_wd_in[462]
    DIRECTION INPUT ;
    USE SIGNAL ;
    SHAPE ABUTMENT ;
    PORT
      LAYER metal3 ;
      RECT 833.805 0.000 833.875 0.070 ;
    END
  END w0_wd_in[462]
  PIN w0_wd_in[463]
    DIRECTION INPUT ;
    USE SIGNAL ;
    SHAPE ABUTMENT ;
    PORT
      LAYER metal3 ;
      RECT 833.945 0.000 834.015 0.070 ;
    END
  END w0_wd_in[463]
  PIN w0_wd_in[464]
    DIRECTION INPUT ;
    USE SIGNAL ;
    SHAPE ABUTMENT ;
    PORT
      LAYER metal3 ;
      RECT 834.085 0.000 834.155 0.070 ;
    END
  END w0_wd_in[464]
  PIN w0_wd_in[465]
    DIRECTION INPUT ;
    USE SIGNAL ;
    SHAPE ABUTMENT ;
    PORT
      LAYER metal3 ;
      RECT 834.225 0.000 834.295 0.070 ;
    END
  END w0_wd_in[465]
  PIN w0_wd_in[466]
    DIRECTION INPUT ;
    USE SIGNAL ;
    SHAPE ABUTMENT ;
    PORT
      LAYER metal3 ;
      RECT 834.365 0.000 834.435 0.070 ;
    END
  END w0_wd_in[466]
  PIN w0_wd_in[467]
    DIRECTION INPUT ;
    USE SIGNAL ;
    SHAPE ABUTMENT ;
    PORT
      LAYER metal3 ;
      RECT 834.505 0.000 834.575 0.070 ;
    END
  END w0_wd_in[467]
  PIN w0_wd_in[468]
    DIRECTION INPUT ;
    USE SIGNAL ;
    SHAPE ABUTMENT ;
    PORT
      LAYER metal3 ;
      RECT 834.645 0.000 834.715 0.070 ;
    END
  END w0_wd_in[468]
  PIN w0_wd_in[469]
    DIRECTION INPUT ;
    USE SIGNAL ;
    SHAPE ABUTMENT ;
    PORT
      LAYER metal3 ;
      RECT 834.785 0.000 834.855 0.070 ;
    END
  END w0_wd_in[469]
  PIN w0_wd_in[470]
    DIRECTION INPUT ;
    USE SIGNAL ;
    SHAPE ABUTMENT ;
    PORT
      LAYER metal3 ;
      RECT 834.925 0.000 834.995 0.070 ;
    END
  END w0_wd_in[470]
  PIN w0_wd_in[471]
    DIRECTION INPUT ;
    USE SIGNAL ;
    SHAPE ABUTMENT ;
    PORT
      LAYER metal3 ;
      RECT 835.065 0.000 835.135 0.070 ;
    END
  END w0_wd_in[471]
  PIN w0_wd_in[472]
    DIRECTION INPUT ;
    USE SIGNAL ;
    SHAPE ABUTMENT ;
    PORT
      LAYER metal3 ;
      RECT 835.205 0.000 835.275 0.070 ;
    END
  END w0_wd_in[472]
  PIN w0_wd_in[473]
    DIRECTION INPUT ;
    USE SIGNAL ;
    SHAPE ABUTMENT ;
    PORT
      LAYER metal3 ;
      RECT 835.345 0.000 835.415 0.070 ;
    END
  END w0_wd_in[473]
  PIN w0_wd_in[474]
    DIRECTION INPUT ;
    USE SIGNAL ;
    SHAPE ABUTMENT ;
    PORT
      LAYER metal3 ;
      RECT 835.485 0.000 835.555 0.070 ;
    END
  END w0_wd_in[474]
  PIN w0_wd_in[475]
    DIRECTION INPUT ;
    USE SIGNAL ;
    SHAPE ABUTMENT ;
    PORT
      LAYER metal3 ;
      RECT 835.625 0.000 835.695 0.070 ;
    END
  END w0_wd_in[475]
  PIN w0_wd_in[476]
    DIRECTION INPUT ;
    USE SIGNAL ;
    SHAPE ABUTMENT ;
    PORT
      LAYER metal3 ;
      RECT 835.765 0.000 835.835 0.070 ;
    END
  END w0_wd_in[476]
  PIN w0_wd_in[477]
    DIRECTION INPUT ;
    USE SIGNAL ;
    SHAPE ABUTMENT ;
    PORT
      LAYER metal3 ;
      RECT 835.905 0.000 835.975 0.070 ;
    END
  END w0_wd_in[477]
  PIN w0_wd_in[478]
    DIRECTION INPUT ;
    USE SIGNAL ;
    SHAPE ABUTMENT ;
    PORT
      LAYER metal3 ;
      RECT 836.045 0.000 836.115 0.070 ;
    END
  END w0_wd_in[478]
  PIN w0_wd_in[479]
    DIRECTION INPUT ;
    USE SIGNAL ;
    SHAPE ABUTMENT ;
    PORT
      LAYER metal3 ;
      RECT 836.185 0.000 836.255 0.070 ;
    END
  END w0_wd_in[479]
  PIN w0_wd_in[480]
    DIRECTION INPUT ;
    USE SIGNAL ;
    SHAPE ABUTMENT ;
    PORT
      LAYER metal3 ;
      RECT 836.325 0.000 836.395 0.070 ;
    END
  END w0_wd_in[480]
  PIN w0_wd_in[481]
    DIRECTION INPUT ;
    USE SIGNAL ;
    SHAPE ABUTMENT ;
    PORT
      LAYER metal3 ;
      RECT 836.465 0.000 836.535 0.070 ;
    END
  END w0_wd_in[481]
  PIN w0_wd_in[482]
    DIRECTION INPUT ;
    USE SIGNAL ;
    SHAPE ABUTMENT ;
    PORT
      LAYER metal3 ;
      RECT 836.605 0.000 836.675 0.070 ;
    END
  END w0_wd_in[482]
  PIN w0_wd_in[483]
    DIRECTION INPUT ;
    USE SIGNAL ;
    SHAPE ABUTMENT ;
    PORT
      LAYER metal3 ;
      RECT 836.745 0.000 836.815 0.070 ;
    END
  END w0_wd_in[483]
  PIN w0_wd_in[484]
    DIRECTION INPUT ;
    USE SIGNAL ;
    SHAPE ABUTMENT ;
    PORT
      LAYER metal3 ;
      RECT 836.885 0.000 836.955 0.070 ;
    END
  END w0_wd_in[484]
  PIN w0_wd_in[485]
    DIRECTION INPUT ;
    USE SIGNAL ;
    SHAPE ABUTMENT ;
    PORT
      LAYER metal3 ;
      RECT 837.025 0.000 837.095 0.070 ;
    END
  END w0_wd_in[485]
  PIN w0_wd_in[486]
    DIRECTION INPUT ;
    USE SIGNAL ;
    SHAPE ABUTMENT ;
    PORT
      LAYER metal3 ;
      RECT 837.165 0.000 837.235 0.070 ;
    END
  END w0_wd_in[486]
  PIN w0_wd_in[487]
    DIRECTION INPUT ;
    USE SIGNAL ;
    SHAPE ABUTMENT ;
    PORT
      LAYER metal3 ;
      RECT 837.305 0.000 837.375 0.070 ;
    END
  END w0_wd_in[487]
  PIN w0_wd_in[488]
    DIRECTION INPUT ;
    USE SIGNAL ;
    SHAPE ABUTMENT ;
    PORT
      LAYER metal3 ;
      RECT 837.445 0.000 837.515 0.070 ;
    END
  END w0_wd_in[488]
  PIN w0_wd_in[489]
    DIRECTION INPUT ;
    USE SIGNAL ;
    SHAPE ABUTMENT ;
    PORT
      LAYER metal3 ;
      RECT 837.585 0.000 837.655 0.070 ;
    END
  END w0_wd_in[489]
  PIN w0_wd_in[490]
    DIRECTION INPUT ;
    USE SIGNAL ;
    SHAPE ABUTMENT ;
    PORT
      LAYER metal3 ;
      RECT 837.725 0.000 837.795 0.070 ;
    END
  END w0_wd_in[490]
  PIN w0_wd_in[491]
    DIRECTION INPUT ;
    USE SIGNAL ;
    SHAPE ABUTMENT ;
    PORT
      LAYER metal3 ;
      RECT 837.865 0.000 837.935 0.070 ;
    END
  END w0_wd_in[491]
  PIN w0_wd_in[492]
    DIRECTION INPUT ;
    USE SIGNAL ;
    SHAPE ABUTMENT ;
    PORT
      LAYER metal3 ;
      RECT 838.005 0.000 838.075 0.070 ;
    END
  END w0_wd_in[492]
  PIN w0_wd_in[493]
    DIRECTION INPUT ;
    USE SIGNAL ;
    SHAPE ABUTMENT ;
    PORT
      LAYER metal3 ;
      RECT 838.145 0.000 838.215 0.070 ;
    END
  END w0_wd_in[493]
  PIN w0_wd_in[494]
    DIRECTION INPUT ;
    USE SIGNAL ;
    SHAPE ABUTMENT ;
    PORT
      LAYER metal3 ;
      RECT 838.285 0.000 838.355 0.070 ;
    END
  END w0_wd_in[494]
  PIN w0_wd_in[495]
    DIRECTION INPUT ;
    USE SIGNAL ;
    SHAPE ABUTMENT ;
    PORT
      LAYER metal3 ;
      RECT 838.425 0.000 838.495 0.070 ;
    END
  END w0_wd_in[495]
  PIN w0_wd_in[496]
    DIRECTION INPUT ;
    USE SIGNAL ;
    SHAPE ABUTMENT ;
    PORT
      LAYER metal3 ;
      RECT 838.565 0.000 838.635 0.070 ;
    END
  END w0_wd_in[496]
  PIN w0_wd_in[497]
    DIRECTION INPUT ;
    USE SIGNAL ;
    SHAPE ABUTMENT ;
    PORT
      LAYER metal3 ;
      RECT 838.705 0.000 838.775 0.070 ;
    END
  END w0_wd_in[497]
  PIN w0_wd_in[498]
    DIRECTION INPUT ;
    USE SIGNAL ;
    SHAPE ABUTMENT ;
    PORT
      LAYER metal3 ;
      RECT 838.845 0.000 838.915 0.070 ;
    END
  END w0_wd_in[498]
  PIN w0_wd_in[499]
    DIRECTION INPUT ;
    USE SIGNAL ;
    SHAPE ABUTMENT ;
    PORT
      LAYER metal3 ;
      RECT 838.985 0.000 839.055 0.070 ;
    END
  END w0_wd_in[499]
  PIN w0_wd_in[500]
    DIRECTION INPUT ;
    USE SIGNAL ;
    SHAPE ABUTMENT ;
    PORT
      LAYER metal3 ;
      RECT 839.125 0.000 839.195 0.070 ;
    END
  END w0_wd_in[500]
  PIN w0_wd_in[501]
    DIRECTION INPUT ;
    USE SIGNAL ;
    SHAPE ABUTMENT ;
    PORT
      LAYER metal3 ;
      RECT 839.265 0.000 839.335 0.070 ;
    END
  END w0_wd_in[501]
  PIN w0_wd_in[502]
    DIRECTION INPUT ;
    USE SIGNAL ;
    SHAPE ABUTMENT ;
    PORT
      LAYER metal3 ;
      RECT 839.405 0.000 839.475 0.070 ;
    END
  END w0_wd_in[502]
  PIN w0_wd_in[503]
    DIRECTION INPUT ;
    USE SIGNAL ;
    SHAPE ABUTMENT ;
    PORT
      LAYER metal3 ;
      RECT 839.545 0.000 839.615 0.070 ;
    END
  END w0_wd_in[503]
  PIN w0_wd_in[504]
    DIRECTION INPUT ;
    USE SIGNAL ;
    SHAPE ABUTMENT ;
    PORT
      LAYER metal3 ;
      RECT 839.685 0.000 839.755 0.070 ;
    END
  END w0_wd_in[504]
  PIN w0_wd_in[505]
    DIRECTION INPUT ;
    USE SIGNAL ;
    SHAPE ABUTMENT ;
    PORT
      LAYER metal3 ;
      RECT 839.825 0.000 839.895 0.070 ;
    END
  END w0_wd_in[505]
  PIN w0_wd_in[506]
    DIRECTION INPUT ;
    USE SIGNAL ;
    SHAPE ABUTMENT ;
    PORT
      LAYER metal3 ;
      RECT 839.965 0.000 840.035 0.070 ;
    END
  END w0_wd_in[506]
  PIN w0_wd_in[507]
    DIRECTION INPUT ;
    USE SIGNAL ;
    SHAPE ABUTMENT ;
    PORT
      LAYER metal3 ;
      RECT 840.105 0.000 840.175 0.070 ;
    END
  END w0_wd_in[507]
  PIN w0_wd_in[508]
    DIRECTION INPUT ;
    USE SIGNAL ;
    SHAPE ABUTMENT ;
    PORT
      LAYER metal3 ;
      RECT 840.245 0.000 840.315 0.070 ;
    END
  END w0_wd_in[508]
  PIN w0_wd_in[509]
    DIRECTION INPUT ;
    USE SIGNAL ;
    SHAPE ABUTMENT ;
    PORT
      LAYER metal3 ;
      RECT 840.385 0.000 840.455 0.070 ;
    END
  END w0_wd_in[509]
  PIN w0_wd_in[510]
    DIRECTION INPUT ;
    USE SIGNAL ;
    SHAPE ABUTMENT ;
    PORT
      LAYER metal3 ;
      RECT 840.525 0.000 840.595 0.070 ;
    END
  END w0_wd_in[510]
  PIN w0_wd_in[511]
    DIRECTION INPUT ;
    USE SIGNAL ;
    SHAPE ABUTMENT ;
    PORT
      LAYER metal3 ;
      RECT 840.665 0.000 840.735 0.070 ;
    END
  END w0_wd_in[511]
  PIN VSS
    DIRECTION INOUT ;
    USE GROUND ;
    PORT
      LAYER metal4 ;
      RECT 2.450 0.140 2.730 1516.130 ;
      RECT 4.690 0.140 4.970 1516.130 ;
      RECT 6.930 0.140 7.210 1516.130 ;
      RECT 9.170 0.140 9.450 1516.130 ;
      RECT 11.410 0.140 11.690 1516.130 ;
      RECT 13.650 0.140 13.930 1516.130 ;
      RECT 15.890 0.140 16.170 1516.130 ;
      RECT 18.130 0.140 18.410 1516.130 ;
      RECT 20.370 0.140 20.650 1516.130 ;
      RECT 22.610 0.140 22.890 1516.130 ;
      RECT 24.850 0.140 25.130 1516.130 ;
      RECT 27.090 0.140 27.370 1516.130 ;
      RECT 29.330 0.140 29.610 1516.130 ;
      RECT 31.570 0.140 31.850 1516.130 ;
      RECT 33.810 0.140 34.090 1516.130 ;
      RECT 36.050 0.140 36.330 1516.130 ;
      RECT 38.290 0.140 38.570 1516.130 ;
      RECT 40.530 0.140 40.810 1516.130 ;
      RECT 42.770 0.140 43.050 1516.130 ;
      RECT 45.010 0.140 45.290 1516.130 ;
      RECT 47.250 0.140 47.530 1516.130 ;
      RECT 49.490 0.140 49.770 1516.130 ;
      RECT 51.730 0.140 52.010 1516.130 ;
      RECT 53.970 0.140 54.250 1516.130 ;
      RECT 56.210 0.140 56.490 1516.130 ;
      RECT 58.450 0.140 58.730 1516.130 ;
      RECT 60.690 0.140 60.970 1516.130 ;
      RECT 62.930 0.140 63.210 1516.130 ;
      RECT 65.170 0.140 65.450 1516.130 ;
      RECT 67.410 0.140 67.690 1516.130 ;
      RECT 69.650 0.140 69.930 1516.130 ;
      RECT 71.890 0.140 72.170 1516.130 ;
      RECT 74.130 0.140 74.410 1516.130 ;
      RECT 76.370 0.140 76.650 1516.130 ;
      RECT 78.610 0.140 78.890 1516.130 ;
      RECT 80.850 0.140 81.130 1516.130 ;
      RECT 83.090 0.140 83.370 1516.130 ;
      RECT 85.330 0.140 85.610 1516.130 ;
      RECT 87.570 0.140 87.850 1516.130 ;
      RECT 89.810 0.140 90.090 1516.130 ;
      RECT 92.050 0.140 92.330 1516.130 ;
      RECT 94.290 0.140 94.570 1516.130 ;
      RECT 96.530 0.140 96.810 1516.130 ;
      RECT 98.770 0.140 99.050 1516.130 ;
      RECT 101.010 0.140 101.290 1516.130 ;
      RECT 103.250 0.140 103.530 1516.130 ;
      RECT 105.490 0.140 105.770 1516.130 ;
      RECT 107.730 0.140 108.010 1516.130 ;
      RECT 109.970 0.140 110.250 1516.130 ;
      RECT 112.210 0.140 112.490 1516.130 ;
      RECT 114.450 0.140 114.730 1516.130 ;
      RECT 116.690 0.140 116.970 1516.130 ;
      RECT 118.930 0.140 119.210 1516.130 ;
      RECT 121.170 0.140 121.450 1516.130 ;
      RECT 123.410 0.140 123.690 1516.130 ;
      RECT 125.650 0.140 125.930 1516.130 ;
      RECT 127.890 0.140 128.170 1516.130 ;
      RECT 130.130 0.140 130.410 1516.130 ;
      RECT 132.370 0.140 132.650 1516.130 ;
      RECT 134.610 0.140 134.890 1516.130 ;
      RECT 136.850 0.140 137.130 1516.130 ;
      RECT 139.090 0.140 139.370 1516.130 ;
      RECT 141.330 0.140 141.610 1516.130 ;
      RECT 143.570 0.140 143.850 1516.130 ;
      RECT 145.810 0.140 146.090 1516.130 ;
      RECT 148.050 0.140 148.330 1516.130 ;
      RECT 150.290 0.140 150.570 1516.130 ;
      RECT 152.530 0.140 152.810 1516.130 ;
      RECT 154.770 0.140 155.050 1516.130 ;
      RECT 157.010 0.140 157.290 1516.130 ;
      RECT 159.250 0.140 159.530 1516.130 ;
      RECT 161.490 0.140 161.770 1516.130 ;
      RECT 163.730 0.140 164.010 1516.130 ;
      RECT 165.970 0.140 166.250 1516.130 ;
      RECT 168.210 0.140 168.490 1516.130 ;
      RECT 170.450 0.140 170.730 1516.130 ;
      RECT 172.690 0.140 172.970 1516.130 ;
      RECT 174.930 0.140 175.210 1516.130 ;
      RECT 177.170 0.140 177.450 1516.130 ;
      RECT 179.410 0.140 179.690 1516.130 ;
      RECT 181.650 0.140 181.930 1516.130 ;
      RECT 183.890 0.140 184.170 1516.130 ;
      RECT 186.130 0.140 186.410 1516.130 ;
      RECT 188.370 0.140 188.650 1516.130 ;
      RECT 190.610 0.140 190.890 1516.130 ;
      RECT 192.850 0.140 193.130 1516.130 ;
      RECT 195.090 0.140 195.370 1516.130 ;
      RECT 197.330 0.140 197.610 1516.130 ;
      RECT 199.570 0.140 199.850 1516.130 ;
      RECT 201.810 0.140 202.090 1516.130 ;
      RECT 204.050 0.140 204.330 1516.130 ;
      RECT 206.290 0.140 206.570 1516.130 ;
      RECT 208.530 0.140 208.810 1516.130 ;
      RECT 210.770 0.140 211.050 1516.130 ;
      RECT 213.010 0.140 213.290 1516.130 ;
      RECT 215.250 0.140 215.530 1516.130 ;
      RECT 217.490 0.140 217.770 1516.130 ;
      RECT 219.730 0.140 220.010 1516.130 ;
      RECT 221.970 0.140 222.250 1516.130 ;
      RECT 224.210 0.140 224.490 1516.130 ;
      RECT 226.450 0.140 226.730 1516.130 ;
      RECT 228.690 0.140 228.970 1516.130 ;
      RECT 230.930 0.140 231.210 1516.130 ;
      RECT 233.170 0.140 233.450 1516.130 ;
      RECT 235.410 0.140 235.690 1516.130 ;
      RECT 237.650 0.140 237.930 1516.130 ;
      RECT 239.890 0.140 240.170 1516.130 ;
      RECT 242.130 0.140 242.410 1516.130 ;
      RECT 244.370 0.140 244.650 1516.130 ;
      RECT 246.610 0.140 246.890 1516.130 ;
      RECT 248.850 0.140 249.130 1516.130 ;
      RECT 251.090 0.140 251.370 1516.130 ;
      RECT 253.330 0.140 253.610 1516.130 ;
      RECT 255.570 0.140 255.850 1516.130 ;
      RECT 257.810 0.140 258.090 1516.130 ;
      RECT 260.050 0.140 260.330 1516.130 ;
      RECT 262.290 0.140 262.570 1516.130 ;
      RECT 264.530 0.140 264.810 1516.130 ;
      RECT 266.770 0.140 267.050 1516.130 ;
      RECT 269.010 0.140 269.290 1516.130 ;
      RECT 271.250 0.140 271.530 1516.130 ;
      RECT 273.490 0.140 273.770 1516.130 ;
      RECT 275.730 0.140 276.010 1516.130 ;
      RECT 277.970 0.140 278.250 1516.130 ;
      RECT 280.210 0.140 280.490 1516.130 ;
      RECT 282.450 0.140 282.730 1516.130 ;
      RECT 284.690 0.140 284.970 1516.130 ;
      RECT 286.930 0.140 287.210 1516.130 ;
      RECT 289.170 0.140 289.450 1516.130 ;
      RECT 291.410 0.140 291.690 1516.130 ;
      RECT 293.650 0.140 293.930 1516.130 ;
      RECT 295.890 0.140 296.170 1516.130 ;
      RECT 298.130 0.140 298.410 1516.130 ;
      RECT 300.370 0.140 300.650 1516.130 ;
      RECT 302.610 0.140 302.890 1516.130 ;
      RECT 304.850 0.140 305.130 1516.130 ;
      RECT 307.090 0.140 307.370 1516.130 ;
      RECT 309.330 0.140 309.610 1516.130 ;
      RECT 311.570 0.140 311.850 1516.130 ;
      RECT 313.810 0.140 314.090 1516.130 ;
      RECT 316.050 0.140 316.330 1516.130 ;
      RECT 318.290 0.140 318.570 1516.130 ;
      RECT 320.530 0.140 320.810 1516.130 ;
      RECT 322.770 0.140 323.050 1516.130 ;
      RECT 325.010 0.140 325.290 1516.130 ;
      RECT 327.250 0.140 327.530 1516.130 ;
      RECT 329.490 0.140 329.770 1516.130 ;
      RECT 331.730 0.140 332.010 1516.130 ;
      RECT 333.970 0.140 334.250 1516.130 ;
      RECT 336.210 0.140 336.490 1516.130 ;
      RECT 338.450 0.140 338.730 1516.130 ;
      RECT 340.690 0.140 340.970 1516.130 ;
      RECT 342.930 0.140 343.210 1516.130 ;
      RECT 345.170 0.140 345.450 1516.130 ;
      RECT 347.410 0.140 347.690 1516.130 ;
      RECT 349.650 0.140 349.930 1516.130 ;
      RECT 351.890 0.140 352.170 1516.130 ;
      RECT 354.130 0.140 354.410 1516.130 ;
      RECT 356.370 0.140 356.650 1516.130 ;
      RECT 358.610 0.140 358.890 1516.130 ;
      RECT 360.850 0.140 361.130 1516.130 ;
      RECT 363.090 0.140 363.370 1516.130 ;
      RECT 365.330 0.140 365.610 1516.130 ;
      RECT 367.570 0.140 367.850 1516.130 ;
      RECT 369.810 0.140 370.090 1516.130 ;
      RECT 372.050 0.140 372.330 1516.130 ;
      RECT 374.290 0.140 374.570 1516.130 ;
      RECT 376.530 0.140 376.810 1516.130 ;
      RECT 378.770 0.140 379.050 1516.130 ;
      RECT 381.010 0.140 381.290 1516.130 ;
      RECT 383.250 0.140 383.530 1516.130 ;
      RECT 385.490 0.140 385.770 1516.130 ;
      RECT 387.730 0.140 388.010 1516.130 ;
      RECT 389.970 0.140 390.250 1516.130 ;
      RECT 392.210 0.140 392.490 1516.130 ;
      RECT 394.450 0.140 394.730 1516.130 ;
      RECT 396.690 0.140 396.970 1516.130 ;
      RECT 398.930 0.140 399.210 1516.130 ;
      RECT 401.170 0.140 401.450 1516.130 ;
      RECT 403.410 0.140 403.690 1516.130 ;
      RECT 405.650 0.140 405.930 1516.130 ;
      RECT 407.890 0.140 408.170 1516.130 ;
      RECT 410.130 0.140 410.410 1516.130 ;
      RECT 412.370 0.140 412.650 1516.130 ;
      RECT 414.610 0.140 414.890 1516.130 ;
      RECT 416.850 0.140 417.130 1516.130 ;
      RECT 419.090 0.140 419.370 1516.130 ;
      RECT 421.330 0.140 421.610 1516.130 ;
      RECT 423.570 0.140 423.850 1516.130 ;
      RECT 425.810 0.140 426.090 1516.130 ;
      RECT 428.050 0.140 428.330 1516.130 ;
      RECT 430.290 0.140 430.570 1516.130 ;
      RECT 432.530 0.140 432.810 1516.130 ;
      RECT 434.770 0.140 435.050 1516.130 ;
      RECT 437.010 0.140 437.290 1516.130 ;
      RECT 439.250 0.140 439.530 1516.130 ;
      RECT 441.490 0.140 441.770 1516.130 ;
      RECT 443.730 0.140 444.010 1516.130 ;
      RECT 445.970 0.140 446.250 1516.130 ;
      RECT 448.210 0.140 448.490 1516.130 ;
      RECT 450.450 0.140 450.730 1516.130 ;
      RECT 452.690 0.140 452.970 1516.130 ;
      RECT 454.930 0.140 455.210 1516.130 ;
      RECT 457.170 0.140 457.450 1516.130 ;
      RECT 459.410 0.140 459.690 1516.130 ;
      RECT 461.650 0.140 461.930 1516.130 ;
      RECT 463.890 0.140 464.170 1516.130 ;
      RECT 466.130 0.140 466.410 1516.130 ;
      RECT 468.370 0.140 468.650 1516.130 ;
      RECT 470.610 0.140 470.890 1516.130 ;
      RECT 472.850 0.140 473.130 1516.130 ;
      RECT 475.090 0.140 475.370 1516.130 ;
      RECT 477.330 0.140 477.610 1516.130 ;
      RECT 479.570 0.140 479.850 1516.130 ;
      RECT 481.810 0.140 482.090 1516.130 ;
      RECT 484.050 0.140 484.330 1516.130 ;
      RECT 486.290 0.140 486.570 1516.130 ;
      RECT 488.530 0.140 488.810 1516.130 ;
      RECT 490.770 0.140 491.050 1516.130 ;
      RECT 493.010 0.140 493.290 1516.130 ;
      RECT 495.250 0.140 495.530 1516.130 ;
      RECT 497.490 0.140 497.770 1516.130 ;
      RECT 499.730 0.140 500.010 1516.130 ;
      RECT 501.970 0.140 502.250 1516.130 ;
      RECT 504.210 0.140 504.490 1516.130 ;
      RECT 506.450 0.140 506.730 1516.130 ;
      RECT 508.690 0.140 508.970 1516.130 ;
      RECT 510.930 0.140 511.210 1516.130 ;
      RECT 513.170 0.140 513.450 1516.130 ;
      RECT 515.410 0.140 515.690 1516.130 ;
      RECT 517.650 0.140 517.930 1516.130 ;
      RECT 519.890 0.140 520.170 1516.130 ;
      RECT 522.130 0.140 522.410 1516.130 ;
      RECT 524.370 0.140 524.650 1516.130 ;
      RECT 526.610 0.140 526.890 1516.130 ;
      RECT 528.850 0.140 529.130 1516.130 ;
      RECT 531.090 0.140 531.370 1516.130 ;
      RECT 533.330 0.140 533.610 1516.130 ;
      RECT 535.570 0.140 535.850 1516.130 ;
      RECT 537.810 0.140 538.090 1516.130 ;
      RECT 540.050 0.140 540.330 1516.130 ;
      RECT 542.290 0.140 542.570 1516.130 ;
      RECT 544.530 0.140 544.810 1516.130 ;
      RECT 546.770 0.140 547.050 1516.130 ;
      RECT 549.010 0.140 549.290 1516.130 ;
      RECT 551.250 0.140 551.530 1516.130 ;
      RECT 553.490 0.140 553.770 1516.130 ;
      RECT 555.730 0.140 556.010 1516.130 ;
      RECT 557.970 0.140 558.250 1516.130 ;
      RECT 560.210 0.140 560.490 1516.130 ;
      RECT 562.450 0.140 562.730 1516.130 ;
      RECT 564.690 0.140 564.970 1516.130 ;
      RECT 566.930 0.140 567.210 1516.130 ;
      RECT 569.170 0.140 569.450 1516.130 ;
      RECT 571.410 0.140 571.690 1516.130 ;
      RECT 573.650 0.140 573.930 1516.130 ;
      RECT 575.890 0.140 576.170 1516.130 ;
      RECT 578.130 0.140 578.410 1516.130 ;
      RECT 580.370 0.140 580.650 1516.130 ;
      RECT 582.610 0.140 582.890 1516.130 ;
      RECT 584.850 0.140 585.130 1516.130 ;
      RECT 587.090 0.140 587.370 1516.130 ;
      RECT 589.330 0.140 589.610 1516.130 ;
      RECT 591.570 0.140 591.850 1516.130 ;
      RECT 593.810 0.140 594.090 1516.130 ;
      RECT 596.050 0.140 596.330 1516.130 ;
      RECT 598.290 0.140 598.570 1516.130 ;
      RECT 600.530 0.140 600.810 1516.130 ;
      RECT 602.770 0.140 603.050 1516.130 ;
      RECT 605.010 0.140 605.290 1516.130 ;
      RECT 607.250 0.140 607.530 1516.130 ;
      RECT 609.490 0.140 609.770 1516.130 ;
      RECT 611.730 0.140 612.010 1516.130 ;
      RECT 613.970 0.140 614.250 1516.130 ;
      RECT 616.210 0.140 616.490 1516.130 ;
      RECT 618.450 0.140 618.730 1516.130 ;
      RECT 620.690 0.140 620.970 1516.130 ;
      RECT 622.930 0.140 623.210 1516.130 ;
      RECT 625.170 0.140 625.450 1516.130 ;
      RECT 627.410 0.140 627.690 1516.130 ;
      RECT 629.650 0.140 629.930 1516.130 ;
      RECT 631.890 0.140 632.170 1516.130 ;
      RECT 634.130 0.140 634.410 1516.130 ;
      RECT 636.370 0.140 636.650 1516.130 ;
      RECT 638.610 0.140 638.890 1516.130 ;
      RECT 640.850 0.140 641.130 1516.130 ;
      RECT 643.090 0.140 643.370 1516.130 ;
      RECT 645.330 0.140 645.610 1516.130 ;
      RECT 647.570 0.140 647.850 1516.130 ;
      RECT 649.810 0.140 650.090 1516.130 ;
      RECT 652.050 0.140 652.330 1516.130 ;
      RECT 654.290 0.140 654.570 1516.130 ;
      RECT 656.530 0.140 656.810 1516.130 ;
      RECT 658.770 0.140 659.050 1516.130 ;
      RECT 661.010 0.140 661.290 1516.130 ;
      RECT 663.250 0.140 663.530 1516.130 ;
      RECT 665.490 0.140 665.770 1516.130 ;
      RECT 667.730 0.140 668.010 1516.130 ;
      RECT 669.970 0.140 670.250 1516.130 ;
      RECT 672.210 0.140 672.490 1516.130 ;
      RECT 674.450 0.140 674.730 1516.130 ;
      RECT 676.690 0.140 676.970 1516.130 ;
      RECT 678.930 0.140 679.210 1516.130 ;
      RECT 681.170 0.140 681.450 1516.130 ;
      RECT 683.410 0.140 683.690 1516.130 ;
      RECT 685.650 0.140 685.930 1516.130 ;
      RECT 687.890 0.140 688.170 1516.130 ;
      RECT 690.130 0.140 690.410 1516.130 ;
      RECT 692.370 0.140 692.650 1516.130 ;
      RECT 694.610 0.140 694.890 1516.130 ;
      RECT 696.850 0.140 697.130 1516.130 ;
      RECT 699.090 0.140 699.370 1516.130 ;
      RECT 701.330 0.140 701.610 1516.130 ;
      RECT 703.570 0.140 703.850 1516.130 ;
      RECT 705.810 0.140 706.090 1516.130 ;
      RECT 708.050 0.140 708.330 1516.130 ;
      RECT 710.290 0.140 710.570 1516.130 ;
      RECT 712.530 0.140 712.810 1516.130 ;
      RECT 714.770 0.140 715.050 1516.130 ;
      RECT 717.010 0.140 717.290 1516.130 ;
      RECT 719.250 0.140 719.530 1516.130 ;
      RECT 721.490 0.140 721.770 1516.130 ;
      RECT 723.730 0.140 724.010 1516.130 ;
      RECT 725.970 0.140 726.250 1516.130 ;
      RECT 728.210 0.140 728.490 1516.130 ;
      RECT 730.450 0.140 730.730 1516.130 ;
      RECT 732.690 0.140 732.970 1516.130 ;
      RECT 734.930 0.140 735.210 1516.130 ;
      RECT 737.170 0.140 737.450 1516.130 ;
      RECT 739.410 0.140 739.690 1516.130 ;
      RECT 741.650 0.140 741.930 1516.130 ;
      RECT 743.890 0.140 744.170 1516.130 ;
      RECT 746.130 0.140 746.410 1516.130 ;
      RECT 748.370 0.140 748.650 1516.130 ;
      RECT 750.610 0.140 750.890 1516.130 ;
      RECT 752.850 0.140 753.130 1516.130 ;
      RECT 755.090 0.140 755.370 1516.130 ;
      RECT 757.330 0.140 757.610 1516.130 ;
      RECT 759.570 0.140 759.850 1516.130 ;
      RECT 761.810 0.140 762.090 1516.130 ;
      RECT 764.050 0.140 764.330 1516.130 ;
      RECT 766.290 0.140 766.570 1516.130 ;
      RECT 768.530 0.140 768.810 1516.130 ;
      RECT 770.770 0.140 771.050 1516.130 ;
      RECT 773.010 0.140 773.290 1516.130 ;
      RECT 775.250 0.140 775.530 1516.130 ;
      RECT 777.490 0.140 777.770 1516.130 ;
      RECT 779.730 0.140 780.010 1516.130 ;
      RECT 781.970 0.140 782.250 1516.130 ;
      RECT 784.210 0.140 784.490 1516.130 ;
      RECT 786.450 0.140 786.730 1516.130 ;
      RECT 788.690 0.140 788.970 1516.130 ;
      RECT 790.930 0.140 791.210 1516.130 ;
      RECT 793.170 0.140 793.450 1516.130 ;
      RECT 795.410 0.140 795.690 1516.130 ;
      RECT 797.650 0.140 797.930 1516.130 ;
      RECT 799.890 0.140 800.170 1516.130 ;
      RECT 802.130 0.140 802.410 1516.130 ;
      RECT 804.370 0.140 804.650 1516.130 ;
      RECT 806.610 0.140 806.890 1516.130 ;
      RECT 808.850 0.140 809.130 1516.130 ;
      RECT 811.090 0.140 811.370 1516.130 ;
      RECT 813.330 0.140 813.610 1516.130 ;
      RECT 815.570 0.140 815.850 1516.130 ;
      RECT 817.810 0.140 818.090 1516.130 ;
      RECT 820.050 0.140 820.330 1516.130 ;
      RECT 822.290 0.140 822.570 1516.130 ;
      RECT 824.530 0.140 824.810 1516.130 ;
      RECT 826.770 0.140 827.050 1516.130 ;
      RECT 829.010 0.140 829.290 1516.130 ;
      RECT 831.250 0.140 831.530 1516.130 ;
      RECT 833.490 0.140 833.770 1516.130 ;
      RECT 835.730 0.140 836.010 1516.130 ;
      RECT 837.970 0.140 838.250 1516.130 ;
      RECT 840.210 0.140 840.490 1516.130 ;
      RECT 842.450 0.140 842.730 1516.130 ;
      RECT 844.690 0.140 844.970 1516.130 ;
      RECT 846.930 0.140 847.210 1516.130 ;
      RECT 849.170 0.140 849.450 1516.130 ;
      RECT 851.410 0.140 851.690 1516.130 ;
      RECT 853.650 0.140 853.930 1516.130 ;
      RECT 855.890 0.140 856.170 1516.130 ;
      RECT 858.130 0.140 858.410 1516.130 ;
      RECT 860.370 0.140 860.650 1516.130 ;
      RECT 862.610 0.140 862.890 1516.130 ;
      RECT 864.850 0.140 865.130 1516.130 ;
      RECT 867.090 0.140 867.370 1516.130 ;
      RECT 869.330 0.140 869.610 1516.130 ;
      RECT 871.570 0.140 871.850 1516.130 ;
      RECT 873.810 0.140 874.090 1516.130 ;
      RECT 876.050 0.140 876.330 1516.130 ;
      RECT 878.290 0.140 878.570 1516.130 ;
      RECT 880.530 0.140 880.810 1516.130 ;
      RECT 882.770 0.140 883.050 1516.130 ;
      RECT 885.010 0.140 885.290 1516.130 ;
      RECT 887.250 0.140 887.530 1516.130 ;
      RECT 889.490 0.140 889.770 1516.130 ;
      RECT 891.730 0.140 892.010 1516.130 ;
      RECT 893.970 0.140 894.250 1516.130 ;
      RECT 896.210 0.140 896.490 1516.130 ;
      RECT 898.450 0.140 898.730 1516.130 ;
      RECT 900.690 0.140 900.970 1516.130 ;
      RECT 902.930 0.140 903.210 1516.130 ;
      RECT 905.170 0.140 905.450 1516.130 ;
      RECT 907.410 0.140 907.690 1516.130 ;
      RECT 909.650 0.140 909.930 1516.130 ;
      RECT 911.890 0.140 912.170 1516.130 ;
      RECT 914.130 0.140 914.410 1516.130 ;
      RECT 916.370 0.140 916.650 1516.130 ;
      RECT 918.610 0.140 918.890 1516.130 ;
      RECT 920.850 0.140 921.130 1516.130 ;
      RECT 923.090 0.140 923.370 1516.130 ;
      RECT 925.330 0.140 925.610 1516.130 ;
      RECT 927.570 0.140 927.850 1516.130 ;
      RECT 929.810 0.140 930.090 1516.130 ;
      RECT 932.050 0.140 932.330 1516.130 ;
      RECT 934.290 0.140 934.570 1516.130 ;
      RECT 936.530 0.140 936.810 1516.130 ;
      RECT 938.770 0.140 939.050 1516.130 ;
      RECT 941.010 0.140 941.290 1516.130 ;
      RECT 943.250 0.140 943.530 1516.130 ;
      RECT 945.490 0.140 945.770 1516.130 ;
      RECT 947.730 0.140 948.010 1516.130 ;
      RECT 949.970 0.140 950.250 1516.130 ;
      RECT 952.210 0.140 952.490 1516.130 ;
      RECT 954.450 0.140 954.730 1516.130 ;
      RECT 956.690 0.140 956.970 1516.130 ;
      RECT 958.930 0.140 959.210 1516.130 ;
      RECT 961.170 0.140 961.450 1516.130 ;
      RECT 963.410 0.140 963.690 1516.130 ;
      RECT 965.650 0.140 965.930 1516.130 ;
      RECT 967.890 0.140 968.170 1516.130 ;
      RECT 970.130 0.140 970.410 1516.130 ;
      RECT 972.370 0.140 972.650 1516.130 ;
      RECT 974.610 0.140 974.890 1516.130 ;
      RECT 976.850 0.140 977.130 1516.130 ;
      RECT 979.090 0.140 979.370 1516.130 ;
      RECT 981.330 0.140 981.610 1516.130 ;
      RECT 983.570 0.140 983.850 1516.130 ;
      RECT 985.810 0.140 986.090 1516.130 ;
      RECT 988.050 0.140 988.330 1516.130 ;
      RECT 990.290 0.140 990.570 1516.130 ;
      RECT 992.530 0.140 992.810 1516.130 ;
      RECT 994.770 0.140 995.050 1516.130 ;
      RECT 997.010 0.140 997.290 1516.130 ;
      RECT 999.250 0.140 999.530 1516.130 ;
      RECT 1001.490 0.140 1001.770 1516.130 ;
      RECT 1003.730 0.140 1004.010 1516.130 ;
      RECT 1005.970 0.140 1006.250 1516.130 ;
      RECT 1008.210 0.140 1008.490 1516.130 ;
      RECT 1010.450 0.140 1010.730 1516.130 ;
      RECT 1012.690 0.140 1012.970 1516.130 ;
      RECT 1014.930 0.140 1015.210 1516.130 ;
      RECT 1017.170 0.140 1017.450 1516.130 ;
      RECT 1019.410 0.140 1019.690 1516.130 ;
      RECT 1021.650 0.140 1021.930 1516.130 ;
      RECT 1023.890 0.140 1024.170 1516.130 ;
      RECT 1026.130 0.140 1026.410 1516.130 ;
      RECT 1028.370 0.140 1028.650 1516.130 ;
      RECT 1030.610 0.140 1030.890 1516.130 ;
      RECT 1032.850 0.140 1033.130 1516.130 ;
      RECT 1035.090 0.140 1035.370 1516.130 ;
      RECT 1037.330 0.140 1037.610 1516.130 ;
      RECT 1039.570 0.140 1039.850 1516.130 ;
      RECT 1041.810 0.140 1042.090 1516.130 ;
      RECT 1044.050 0.140 1044.330 1516.130 ;
      RECT 1046.290 0.140 1046.570 1516.130 ;
      RECT 1048.530 0.140 1048.810 1516.130 ;
      RECT 1050.770 0.140 1051.050 1516.130 ;
      RECT 1053.010 0.140 1053.290 1516.130 ;
      RECT 1055.250 0.140 1055.530 1516.130 ;
      RECT 1057.490 0.140 1057.770 1516.130 ;
      RECT 1059.730 0.140 1060.010 1516.130 ;
      RECT 1061.970 0.140 1062.250 1516.130 ;
      RECT 1064.210 0.140 1064.490 1516.130 ;
      RECT 1066.450 0.140 1066.730 1516.130 ;
      RECT 1068.690 0.140 1068.970 1516.130 ;
      RECT 1070.930 0.140 1071.210 1516.130 ;
      RECT 1073.170 0.140 1073.450 1516.130 ;
      RECT 1075.410 0.140 1075.690 1516.130 ;
      RECT 1077.650 0.140 1077.930 1516.130 ;
      RECT 1079.890 0.140 1080.170 1516.130 ;
      RECT 1082.130 0.140 1082.410 1516.130 ;
      RECT 1084.370 0.140 1084.650 1516.130 ;
      RECT 1086.610 0.140 1086.890 1516.130 ;
      RECT 1088.850 0.140 1089.130 1516.130 ;
      RECT 1091.090 0.140 1091.370 1516.130 ;
      RECT 1093.330 0.140 1093.610 1516.130 ;
      RECT 1095.570 0.140 1095.850 1516.130 ;
      RECT 1097.810 0.140 1098.090 1516.130 ;
      RECT 1100.050 0.140 1100.330 1516.130 ;
      RECT 1102.290 0.140 1102.570 1516.130 ;
      RECT 1104.530 0.140 1104.810 1516.130 ;
      RECT 1106.770 0.140 1107.050 1516.130 ;
      RECT 1109.010 0.140 1109.290 1516.130 ;
      RECT 1111.250 0.140 1111.530 1516.130 ;
      RECT 1113.490 0.140 1113.770 1516.130 ;
      RECT 1115.730 0.140 1116.010 1516.130 ;
      RECT 1117.970 0.140 1118.250 1516.130 ;
      RECT 1120.210 0.140 1120.490 1516.130 ;
      RECT 1122.450 0.140 1122.730 1516.130 ;
      RECT 1124.690 0.140 1124.970 1516.130 ;
      RECT 1126.930 0.140 1127.210 1516.130 ;
      RECT 1129.170 0.140 1129.450 1516.130 ;
      RECT 1131.410 0.140 1131.690 1516.130 ;
      RECT 1133.650 0.140 1133.930 1516.130 ;
      RECT 1135.890 0.140 1136.170 1516.130 ;
      RECT 1138.130 0.140 1138.410 1516.130 ;
      RECT 1140.370 0.140 1140.650 1516.130 ;
      RECT 1142.610 0.140 1142.890 1516.130 ;
      RECT 1144.850 0.140 1145.130 1516.130 ;
      RECT 1147.090 0.140 1147.370 1516.130 ;
      RECT 1149.330 0.140 1149.610 1516.130 ;
      RECT 1151.570 0.140 1151.850 1516.130 ;
      RECT 1153.810 0.140 1154.090 1516.130 ;
      RECT 1156.050 0.140 1156.330 1516.130 ;
      RECT 1158.290 0.140 1158.570 1516.130 ;
      RECT 1160.530 0.140 1160.810 1516.130 ;
      RECT 1162.770 0.140 1163.050 1516.130 ;
      RECT 1165.010 0.140 1165.290 1516.130 ;
      RECT 1167.250 0.140 1167.530 1516.130 ;
      RECT 1169.490 0.140 1169.770 1516.130 ;
      RECT 1171.730 0.140 1172.010 1516.130 ;
      RECT 1173.970 0.140 1174.250 1516.130 ;
      RECT 1176.210 0.140 1176.490 1516.130 ;
      RECT 1178.450 0.140 1178.730 1516.130 ;
      RECT 1180.690 0.140 1180.970 1516.130 ;
      RECT 1182.930 0.140 1183.210 1516.130 ;
      RECT 1185.170 0.140 1185.450 1516.130 ;
      RECT 1187.410 0.140 1187.690 1516.130 ;
      RECT 1189.650 0.140 1189.930 1516.130 ;
      RECT 1191.890 0.140 1192.170 1516.130 ;
      RECT 1194.130 0.140 1194.410 1516.130 ;
      RECT 1196.370 0.140 1196.650 1516.130 ;
      RECT 1198.610 0.140 1198.890 1516.130 ;
      RECT 1200.850 0.140 1201.130 1516.130 ;
      RECT 1203.090 0.140 1203.370 1516.130 ;
      RECT 1205.330 0.140 1205.610 1516.130 ;
      RECT 1207.570 0.140 1207.850 1516.130 ;
      RECT 1209.810 0.140 1210.090 1516.130 ;
      RECT 1212.050 0.140 1212.330 1516.130 ;
      RECT 1214.290 0.140 1214.570 1516.130 ;
      RECT 1216.530 0.140 1216.810 1516.130 ;
      RECT 1218.770 0.140 1219.050 1516.130 ;
      RECT 1221.010 0.140 1221.290 1516.130 ;
      RECT 1223.250 0.140 1223.530 1516.130 ;
      RECT 1225.490 0.140 1225.770 1516.130 ;
      RECT 1227.730 0.140 1228.010 1516.130 ;
      RECT 1229.970 0.140 1230.250 1516.130 ;
      RECT 1232.210 0.140 1232.490 1516.130 ;
      RECT 1234.450 0.140 1234.730 1516.130 ;
      RECT 1236.690 0.140 1236.970 1516.130 ;
      RECT 1238.930 0.140 1239.210 1516.130 ;
      RECT 1241.170 0.140 1241.450 1516.130 ;
      RECT 1243.410 0.140 1243.690 1516.130 ;
      RECT 1245.650 0.140 1245.930 1516.130 ;
      RECT 1247.890 0.140 1248.170 1516.130 ;
      RECT 1250.130 0.140 1250.410 1516.130 ;
      RECT 1252.370 0.140 1252.650 1516.130 ;
      RECT 1254.610 0.140 1254.890 1516.130 ;
      RECT 1256.850 0.140 1257.130 1516.130 ;
      RECT 1259.090 0.140 1259.370 1516.130 ;
      RECT 1261.330 0.140 1261.610 1516.130 ;
      RECT 1263.570 0.140 1263.850 1516.130 ;
      RECT 1265.810 0.140 1266.090 1516.130 ;
      RECT 1268.050 0.140 1268.330 1516.130 ;
      RECT 1270.290 0.140 1270.570 1516.130 ;
      RECT 1272.530 0.140 1272.810 1516.130 ;
      RECT 1274.770 0.140 1275.050 1516.130 ;
      RECT 1277.010 0.140 1277.290 1516.130 ;
      RECT 1279.250 0.140 1279.530 1516.130 ;
      RECT 1281.490 0.140 1281.770 1516.130 ;
      RECT 1283.730 0.140 1284.010 1516.130 ;
      RECT 1285.970 0.140 1286.250 1516.130 ;
      RECT 1288.210 0.140 1288.490 1516.130 ;
      RECT 1290.450 0.140 1290.730 1516.130 ;
      RECT 1292.690 0.140 1292.970 1516.130 ;
      RECT 1294.930 0.140 1295.210 1516.130 ;
      RECT 1297.170 0.140 1297.450 1516.130 ;
      RECT 1299.410 0.140 1299.690 1516.130 ;
      RECT 1301.650 0.140 1301.930 1516.130 ;
      RECT 1303.890 0.140 1304.170 1516.130 ;
      RECT 1306.130 0.140 1306.410 1516.130 ;
      RECT 1308.370 0.140 1308.650 1516.130 ;
      RECT 1310.610 0.140 1310.890 1516.130 ;
      RECT 1312.850 0.140 1313.130 1516.130 ;
      RECT 1315.090 0.140 1315.370 1516.130 ;
      RECT 1317.330 0.140 1317.610 1516.130 ;
      RECT 1319.570 0.140 1319.850 1516.130 ;
      RECT 1321.810 0.140 1322.090 1516.130 ;
      RECT 1324.050 0.140 1324.330 1516.130 ;
      RECT 1326.290 0.140 1326.570 1516.130 ;
      RECT 1328.530 0.140 1328.810 1516.130 ;
      RECT 1330.770 0.140 1331.050 1516.130 ;
      RECT 1333.010 0.140 1333.290 1516.130 ;
      RECT 1335.250 0.140 1335.530 1516.130 ;
      RECT 1337.490 0.140 1337.770 1516.130 ;
      RECT 1339.730 0.140 1340.010 1516.130 ;
      RECT 1341.970 0.140 1342.250 1516.130 ;
      RECT 1344.210 0.140 1344.490 1516.130 ;
      RECT 1346.450 0.140 1346.730 1516.130 ;
      RECT 1348.690 0.140 1348.970 1516.130 ;
      RECT 1350.930 0.140 1351.210 1516.130 ;
      RECT 1353.170 0.140 1353.450 1516.130 ;
      RECT 1355.410 0.140 1355.690 1516.130 ;
      RECT 1357.650 0.140 1357.930 1516.130 ;
      RECT 1359.890 0.140 1360.170 1516.130 ;
      RECT 1362.130 0.140 1362.410 1516.130 ;
      RECT 1364.370 0.140 1364.650 1516.130 ;
      RECT 1366.610 0.140 1366.890 1516.130 ;
      RECT 1368.850 0.140 1369.130 1516.130 ;
      RECT 1371.090 0.140 1371.370 1516.130 ;
      RECT 1373.330 0.140 1373.610 1516.130 ;
      RECT 1375.570 0.140 1375.850 1516.130 ;
      RECT 1377.810 0.140 1378.090 1516.130 ;
      RECT 1380.050 0.140 1380.330 1516.130 ;
      RECT 1382.290 0.140 1382.570 1516.130 ;
      RECT 1384.530 0.140 1384.810 1516.130 ;
      RECT 1386.770 0.140 1387.050 1516.130 ;
      RECT 1389.010 0.140 1389.290 1516.130 ;
      RECT 1391.250 0.140 1391.530 1516.130 ;
      RECT 1393.490 0.140 1393.770 1516.130 ;
      RECT 1395.730 0.140 1396.010 1516.130 ;
      RECT 1397.970 0.140 1398.250 1516.130 ;
      RECT 1400.210 0.140 1400.490 1516.130 ;
      RECT 1402.450 0.140 1402.730 1516.130 ;
      RECT 1404.690 0.140 1404.970 1516.130 ;
      RECT 1406.930 0.140 1407.210 1516.130 ;
      RECT 1409.170 0.140 1409.450 1516.130 ;
      RECT 1411.410 0.140 1411.690 1516.130 ;
      RECT 1413.650 0.140 1413.930 1516.130 ;
      RECT 1415.890 0.140 1416.170 1516.130 ;
      RECT 1418.130 0.140 1418.410 1516.130 ;
      RECT 1420.370 0.140 1420.650 1516.130 ;
      RECT 1422.610 0.140 1422.890 1516.130 ;
      RECT 1424.850 0.140 1425.130 1516.130 ;
      RECT 1427.090 0.140 1427.370 1516.130 ;
      RECT 1429.330 0.140 1429.610 1516.130 ;
      RECT 1431.570 0.140 1431.850 1516.130 ;
      RECT 1433.810 0.140 1434.090 1516.130 ;
      RECT 1436.050 0.140 1436.330 1516.130 ;
      RECT 1438.290 0.140 1438.570 1516.130 ;
      RECT 1440.530 0.140 1440.810 1516.130 ;
      RECT 1442.770 0.140 1443.050 1516.130 ;
      RECT 1445.010 0.140 1445.290 1516.130 ;
      RECT 1447.250 0.140 1447.530 1516.130 ;
      RECT 1449.490 0.140 1449.770 1516.130 ;
      RECT 1451.730 0.140 1452.010 1516.130 ;
      RECT 1453.970 0.140 1454.250 1516.130 ;
      RECT 1456.210 0.140 1456.490 1516.130 ;
      RECT 1458.450 0.140 1458.730 1516.130 ;
      RECT 1460.690 0.140 1460.970 1516.130 ;
      RECT 1462.930 0.140 1463.210 1516.130 ;
      RECT 1465.170 0.140 1465.450 1516.130 ;
      RECT 1467.410 0.140 1467.690 1516.130 ;
      RECT 1469.650 0.140 1469.930 1516.130 ;
      RECT 1471.890 0.140 1472.170 1516.130 ;
      RECT 1474.130 0.140 1474.410 1516.130 ;
      RECT 1476.370 0.140 1476.650 1516.130 ;
      RECT 1478.610 0.140 1478.890 1516.130 ;
      RECT 1480.850 0.140 1481.130 1516.130 ;
      RECT 1483.090 0.140 1483.370 1516.130 ;
      RECT 1485.330 0.140 1485.610 1516.130 ;
      RECT 1487.570 0.140 1487.850 1516.130 ;
      RECT 1489.810 0.140 1490.090 1516.130 ;
      RECT 1492.050 0.140 1492.330 1516.130 ;
      RECT 1494.290 0.140 1494.570 1516.130 ;
      RECT 1496.530 0.140 1496.810 1516.130 ;
      RECT 1498.770 0.140 1499.050 1516.130 ;
      RECT 1501.010 0.140 1501.290 1516.130 ;
      RECT 1503.250 0.140 1503.530 1516.130 ;
      RECT 1505.490 0.140 1505.770 1516.130 ;
      RECT 1507.730 0.140 1508.010 1516.130 ;
      RECT 1509.970 0.140 1510.250 1516.130 ;
      RECT 1512.210 0.140 1512.490 1516.130 ;
      RECT 1514.450 0.140 1514.730 1516.130 ;
      RECT 1516.690 0.140 1516.970 1516.130 ;
      RECT 1518.930 0.140 1519.210 1516.130 ;
      RECT 1521.170 0.140 1521.450 1516.130 ;
      RECT 1523.410 0.140 1523.690 1516.130 ;
      RECT 1525.650 0.140 1525.930 1516.130 ;
      RECT 1527.890 0.140 1528.170 1516.130 ;
      RECT 1530.130 0.140 1530.410 1516.130 ;
      RECT 1532.370 0.140 1532.650 1516.130 ;
      RECT 1534.610 0.140 1534.890 1516.130 ;
      RECT 1536.850 0.140 1537.130 1516.130 ;
      RECT 1539.090 0.140 1539.370 1516.130 ;
      RECT 1541.330 0.140 1541.610 1516.130 ;
      RECT 1543.570 0.140 1543.850 1516.130 ;
      RECT 1545.810 0.140 1546.090 1516.130 ;
      RECT 1548.050 0.140 1548.330 1516.130 ;
      RECT 1550.290 0.140 1550.570 1516.130 ;
      RECT 1552.530 0.140 1552.810 1516.130 ;
      RECT 1554.770 0.140 1555.050 1516.130 ;
      RECT 1557.010 0.140 1557.290 1516.130 ;
      RECT 1559.250 0.140 1559.530 1516.130 ;
      RECT 1561.490 0.140 1561.770 1516.130 ;
      RECT 1563.730 0.140 1564.010 1516.130 ;
      RECT 1565.970 0.140 1566.250 1516.130 ;
      RECT 1568.210 0.140 1568.490 1516.130 ;
      RECT 1570.450 0.140 1570.730 1516.130 ;
      RECT 1572.690 0.140 1572.970 1516.130 ;
      RECT 1574.930 0.140 1575.210 1516.130 ;
      RECT 1577.170 0.140 1577.450 1516.130 ;
      RECT 1579.410 0.140 1579.690 1516.130 ;
      RECT 1581.650 0.140 1581.930 1516.130 ;
      RECT 1583.890 0.140 1584.170 1516.130 ;
      RECT 1586.130 0.140 1586.410 1516.130 ;
      RECT 1588.370 0.140 1588.650 1516.130 ;
      RECT 1590.610 0.140 1590.890 1516.130 ;
      RECT 1592.850 0.140 1593.130 1516.130 ;
      RECT 1595.090 0.140 1595.370 1516.130 ;
      RECT 1597.330 0.140 1597.610 1516.130 ;
      RECT 1599.570 0.140 1599.850 1516.130 ;
      RECT 1601.810 0.140 1602.090 1516.130 ;
      RECT 1604.050 0.140 1604.330 1516.130 ;
      RECT 1606.290 0.140 1606.570 1516.130 ;
      RECT 1608.530 0.140 1608.810 1516.130 ;
    END
  END VSS
  PIN VDD
    DIRECTION INOUT ;
    USE POWER ;
    PORT
      LAYER metal4 ;
      RECT 1.330 0.140 1.610 1516.130 ;
      RECT 3.570 0.140 3.850 1516.130 ;
      RECT 5.810 0.140 6.090 1516.130 ;
      RECT 8.050 0.140 8.330 1516.130 ;
      RECT 10.290 0.140 10.570 1516.130 ;
      RECT 12.530 0.140 12.810 1516.130 ;
      RECT 14.770 0.140 15.050 1516.130 ;
      RECT 17.010 0.140 17.290 1516.130 ;
      RECT 19.250 0.140 19.530 1516.130 ;
      RECT 21.490 0.140 21.770 1516.130 ;
      RECT 23.730 0.140 24.010 1516.130 ;
      RECT 25.970 0.140 26.250 1516.130 ;
      RECT 28.210 0.140 28.490 1516.130 ;
      RECT 30.450 0.140 30.730 1516.130 ;
      RECT 32.690 0.140 32.970 1516.130 ;
      RECT 34.930 0.140 35.210 1516.130 ;
      RECT 37.170 0.140 37.450 1516.130 ;
      RECT 39.410 0.140 39.690 1516.130 ;
      RECT 41.650 0.140 41.930 1516.130 ;
      RECT 43.890 0.140 44.170 1516.130 ;
      RECT 46.130 0.140 46.410 1516.130 ;
      RECT 48.370 0.140 48.650 1516.130 ;
      RECT 50.610 0.140 50.890 1516.130 ;
      RECT 52.850 0.140 53.130 1516.130 ;
      RECT 55.090 0.140 55.370 1516.130 ;
      RECT 57.330 0.140 57.610 1516.130 ;
      RECT 59.570 0.140 59.850 1516.130 ;
      RECT 61.810 0.140 62.090 1516.130 ;
      RECT 64.050 0.140 64.330 1516.130 ;
      RECT 66.290 0.140 66.570 1516.130 ;
      RECT 68.530 0.140 68.810 1516.130 ;
      RECT 70.770 0.140 71.050 1516.130 ;
      RECT 73.010 0.140 73.290 1516.130 ;
      RECT 75.250 0.140 75.530 1516.130 ;
      RECT 77.490 0.140 77.770 1516.130 ;
      RECT 79.730 0.140 80.010 1516.130 ;
      RECT 81.970 0.140 82.250 1516.130 ;
      RECT 84.210 0.140 84.490 1516.130 ;
      RECT 86.450 0.140 86.730 1516.130 ;
      RECT 88.690 0.140 88.970 1516.130 ;
      RECT 90.930 0.140 91.210 1516.130 ;
      RECT 93.170 0.140 93.450 1516.130 ;
      RECT 95.410 0.140 95.690 1516.130 ;
      RECT 97.650 0.140 97.930 1516.130 ;
      RECT 99.890 0.140 100.170 1516.130 ;
      RECT 102.130 0.140 102.410 1516.130 ;
      RECT 104.370 0.140 104.650 1516.130 ;
      RECT 106.610 0.140 106.890 1516.130 ;
      RECT 108.850 0.140 109.130 1516.130 ;
      RECT 111.090 0.140 111.370 1516.130 ;
      RECT 113.330 0.140 113.610 1516.130 ;
      RECT 115.570 0.140 115.850 1516.130 ;
      RECT 117.810 0.140 118.090 1516.130 ;
      RECT 120.050 0.140 120.330 1516.130 ;
      RECT 122.290 0.140 122.570 1516.130 ;
      RECT 124.530 0.140 124.810 1516.130 ;
      RECT 126.770 0.140 127.050 1516.130 ;
      RECT 129.010 0.140 129.290 1516.130 ;
      RECT 131.250 0.140 131.530 1516.130 ;
      RECT 133.490 0.140 133.770 1516.130 ;
      RECT 135.730 0.140 136.010 1516.130 ;
      RECT 137.970 0.140 138.250 1516.130 ;
      RECT 140.210 0.140 140.490 1516.130 ;
      RECT 142.450 0.140 142.730 1516.130 ;
      RECT 144.690 0.140 144.970 1516.130 ;
      RECT 146.930 0.140 147.210 1516.130 ;
      RECT 149.170 0.140 149.450 1516.130 ;
      RECT 151.410 0.140 151.690 1516.130 ;
      RECT 153.650 0.140 153.930 1516.130 ;
      RECT 155.890 0.140 156.170 1516.130 ;
      RECT 158.130 0.140 158.410 1516.130 ;
      RECT 160.370 0.140 160.650 1516.130 ;
      RECT 162.610 0.140 162.890 1516.130 ;
      RECT 164.850 0.140 165.130 1516.130 ;
      RECT 167.090 0.140 167.370 1516.130 ;
      RECT 169.330 0.140 169.610 1516.130 ;
      RECT 171.570 0.140 171.850 1516.130 ;
      RECT 173.810 0.140 174.090 1516.130 ;
      RECT 176.050 0.140 176.330 1516.130 ;
      RECT 178.290 0.140 178.570 1516.130 ;
      RECT 180.530 0.140 180.810 1516.130 ;
      RECT 182.770 0.140 183.050 1516.130 ;
      RECT 185.010 0.140 185.290 1516.130 ;
      RECT 187.250 0.140 187.530 1516.130 ;
      RECT 189.490 0.140 189.770 1516.130 ;
      RECT 191.730 0.140 192.010 1516.130 ;
      RECT 193.970 0.140 194.250 1516.130 ;
      RECT 196.210 0.140 196.490 1516.130 ;
      RECT 198.450 0.140 198.730 1516.130 ;
      RECT 200.690 0.140 200.970 1516.130 ;
      RECT 202.930 0.140 203.210 1516.130 ;
      RECT 205.170 0.140 205.450 1516.130 ;
      RECT 207.410 0.140 207.690 1516.130 ;
      RECT 209.650 0.140 209.930 1516.130 ;
      RECT 211.890 0.140 212.170 1516.130 ;
      RECT 214.130 0.140 214.410 1516.130 ;
      RECT 216.370 0.140 216.650 1516.130 ;
      RECT 218.610 0.140 218.890 1516.130 ;
      RECT 220.850 0.140 221.130 1516.130 ;
      RECT 223.090 0.140 223.370 1516.130 ;
      RECT 225.330 0.140 225.610 1516.130 ;
      RECT 227.570 0.140 227.850 1516.130 ;
      RECT 229.810 0.140 230.090 1516.130 ;
      RECT 232.050 0.140 232.330 1516.130 ;
      RECT 234.290 0.140 234.570 1516.130 ;
      RECT 236.530 0.140 236.810 1516.130 ;
      RECT 238.770 0.140 239.050 1516.130 ;
      RECT 241.010 0.140 241.290 1516.130 ;
      RECT 243.250 0.140 243.530 1516.130 ;
      RECT 245.490 0.140 245.770 1516.130 ;
      RECT 247.730 0.140 248.010 1516.130 ;
      RECT 249.970 0.140 250.250 1516.130 ;
      RECT 252.210 0.140 252.490 1516.130 ;
      RECT 254.450 0.140 254.730 1516.130 ;
      RECT 256.690 0.140 256.970 1516.130 ;
      RECT 258.930 0.140 259.210 1516.130 ;
      RECT 261.170 0.140 261.450 1516.130 ;
      RECT 263.410 0.140 263.690 1516.130 ;
      RECT 265.650 0.140 265.930 1516.130 ;
      RECT 267.890 0.140 268.170 1516.130 ;
      RECT 270.130 0.140 270.410 1516.130 ;
      RECT 272.370 0.140 272.650 1516.130 ;
      RECT 274.610 0.140 274.890 1516.130 ;
      RECT 276.850 0.140 277.130 1516.130 ;
      RECT 279.090 0.140 279.370 1516.130 ;
      RECT 281.330 0.140 281.610 1516.130 ;
      RECT 283.570 0.140 283.850 1516.130 ;
      RECT 285.810 0.140 286.090 1516.130 ;
      RECT 288.050 0.140 288.330 1516.130 ;
      RECT 290.290 0.140 290.570 1516.130 ;
      RECT 292.530 0.140 292.810 1516.130 ;
      RECT 294.770 0.140 295.050 1516.130 ;
      RECT 297.010 0.140 297.290 1516.130 ;
      RECT 299.250 0.140 299.530 1516.130 ;
      RECT 301.490 0.140 301.770 1516.130 ;
      RECT 303.730 0.140 304.010 1516.130 ;
      RECT 305.970 0.140 306.250 1516.130 ;
      RECT 308.210 0.140 308.490 1516.130 ;
      RECT 310.450 0.140 310.730 1516.130 ;
      RECT 312.690 0.140 312.970 1516.130 ;
      RECT 314.930 0.140 315.210 1516.130 ;
      RECT 317.170 0.140 317.450 1516.130 ;
      RECT 319.410 0.140 319.690 1516.130 ;
      RECT 321.650 0.140 321.930 1516.130 ;
      RECT 323.890 0.140 324.170 1516.130 ;
      RECT 326.130 0.140 326.410 1516.130 ;
      RECT 328.370 0.140 328.650 1516.130 ;
      RECT 330.610 0.140 330.890 1516.130 ;
      RECT 332.850 0.140 333.130 1516.130 ;
      RECT 335.090 0.140 335.370 1516.130 ;
      RECT 337.330 0.140 337.610 1516.130 ;
      RECT 339.570 0.140 339.850 1516.130 ;
      RECT 341.810 0.140 342.090 1516.130 ;
      RECT 344.050 0.140 344.330 1516.130 ;
      RECT 346.290 0.140 346.570 1516.130 ;
      RECT 348.530 0.140 348.810 1516.130 ;
      RECT 350.770 0.140 351.050 1516.130 ;
      RECT 353.010 0.140 353.290 1516.130 ;
      RECT 355.250 0.140 355.530 1516.130 ;
      RECT 357.490 0.140 357.770 1516.130 ;
      RECT 359.730 0.140 360.010 1516.130 ;
      RECT 361.970 0.140 362.250 1516.130 ;
      RECT 364.210 0.140 364.490 1516.130 ;
      RECT 366.450 0.140 366.730 1516.130 ;
      RECT 368.690 0.140 368.970 1516.130 ;
      RECT 370.930 0.140 371.210 1516.130 ;
      RECT 373.170 0.140 373.450 1516.130 ;
      RECT 375.410 0.140 375.690 1516.130 ;
      RECT 377.650 0.140 377.930 1516.130 ;
      RECT 379.890 0.140 380.170 1516.130 ;
      RECT 382.130 0.140 382.410 1516.130 ;
      RECT 384.370 0.140 384.650 1516.130 ;
      RECT 386.610 0.140 386.890 1516.130 ;
      RECT 388.850 0.140 389.130 1516.130 ;
      RECT 391.090 0.140 391.370 1516.130 ;
      RECT 393.330 0.140 393.610 1516.130 ;
      RECT 395.570 0.140 395.850 1516.130 ;
      RECT 397.810 0.140 398.090 1516.130 ;
      RECT 400.050 0.140 400.330 1516.130 ;
      RECT 402.290 0.140 402.570 1516.130 ;
      RECT 404.530 0.140 404.810 1516.130 ;
      RECT 406.770 0.140 407.050 1516.130 ;
      RECT 409.010 0.140 409.290 1516.130 ;
      RECT 411.250 0.140 411.530 1516.130 ;
      RECT 413.490 0.140 413.770 1516.130 ;
      RECT 415.730 0.140 416.010 1516.130 ;
      RECT 417.970 0.140 418.250 1516.130 ;
      RECT 420.210 0.140 420.490 1516.130 ;
      RECT 422.450 0.140 422.730 1516.130 ;
      RECT 424.690 0.140 424.970 1516.130 ;
      RECT 426.930 0.140 427.210 1516.130 ;
      RECT 429.170 0.140 429.450 1516.130 ;
      RECT 431.410 0.140 431.690 1516.130 ;
      RECT 433.650 0.140 433.930 1516.130 ;
      RECT 435.890 0.140 436.170 1516.130 ;
      RECT 438.130 0.140 438.410 1516.130 ;
      RECT 440.370 0.140 440.650 1516.130 ;
      RECT 442.610 0.140 442.890 1516.130 ;
      RECT 444.850 0.140 445.130 1516.130 ;
      RECT 447.090 0.140 447.370 1516.130 ;
      RECT 449.330 0.140 449.610 1516.130 ;
      RECT 451.570 0.140 451.850 1516.130 ;
      RECT 453.810 0.140 454.090 1516.130 ;
      RECT 456.050 0.140 456.330 1516.130 ;
      RECT 458.290 0.140 458.570 1516.130 ;
      RECT 460.530 0.140 460.810 1516.130 ;
      RECT 462.770 0.140 463.050 1516.130 ;
      RECT 465.010 0.140 465.290 1516.130 ;
      RECT 467.250 0.140 467.530 1516.130 ;
      RECT 469.490 0.140 469.770 1516.130 ;
      RECT 471.730 0.140 472.010 1516.130 ;
      RECT 473.970 0.140 474.250 1516.130 ;
      RECT 476.210 0.140 476.490 1516.130 ;
      RECT 478.450 0.140 478.730 1516.130 ;
      RECT 480.690 0.140 480.970 1516.130 ;
      RECT 482.930 0.140 483.210 1516.130 ;
      RECT 485.170 0.140 485.450 1516.130 ;
      RECT 487.410 0.140 487.690 1516.130 ;
      RECT 489.650 0.140 489.930 1516.130 ;
      RECT 491.890 0.140 492.170 1516.130 ;
      RECT 494.130 0.140 494.410 1516.130 ;
      RECT 496.370 0.140 496.650 1516.130 ;
      RECT 498.610 0.140 498.890 1516.130 ;
      RECT 500.850 0.140 501.130 1516.130 ;
      RECT 503.090 0.140 503.370 1516.130 ;
      RECT 505.330 0.140 505.610 1516.130 ;
      RECT 507.570 0.140 507.850 1516.130 ;
      RECT 509.810 0.140 510.090 1516.130 ;
      RECT 512.050 0.140 512.330 1516.130 ;
      RECT 514.290 0.140 514.570 1516.130 ;
      RECT 516.530 0.140 516.810 1516.130 ;
      RECT 518.770 0.140 519.050 1516.130 ;
      RECT 521.010 0.140 521.290 1516.130 ;
      RECT 523.250 0.140 523.530 1516.130 ;
      RECT 525.490 0.140 525.770 1516.130 ;
      RECT 527.730 0.140 528.010 1516.130 ;
      RECT 529.970 0.140 530.250 1516.130 ;
      RECT 532.210 0.140 532.490 1516.130 ;
      RECT 534.450 0.140 534.730 1516.130 ;
      RECT 536.690 0.140 536.970 1516.130 ;
      RECT 538.930 0.140 539.210 1516.130 ;
      RECT 541.170 0.140 541.450 1516.130 ;
      RECT 543.410 0.140 543.690 1516.130 ;
      RECT 545.650 0.140 545.930 1516.130 ;
      RECT 547.890 0.140 548.170 1516.130 ;
      RECT 550.130 0.140 550.410 1516.130 ;
      RECT 552.370 0.140 552.650 1516.130 ;
      RECT 554.610 0.140 554.890 1516.130 ;
      RECT 556.850 0.140 557.130 1516.130 ;
      RECT 559.090 0.140 559.370 1516.130 ;
      RECT 561.330 0.140 561.610 1516.130 ;
      RECT 563.570 0.140 563.850 1516.130 ;
      RECT 565.810 0.140 566.090 1516.130 ;
      RECT 568.050 0.140 568.330 1516.130 ;
      RECT 570.290 0.140 570.570 1516.130 ;
      RECT 572.530 0.140 572.810 1516.130 ;
      RECT 574.770 0.140 575.050 1516.130 ;
      RECT 577.010 0.140 577.290 1516.130 ;
      RECT 579.250 0.140 579.530 1516.130 ;
      RECT 581.490 0.140 581.770 1516.130 ;
      RECT 583.730 0.140 584.010 1516.130 ;
      RECT 585.970 0.140 586.250 1516.130 ;
      RECT 588.210 0.140 588.490 1516.130 ;
      RECT 590.450 0.140 590.730 1516.130 ;
      RECT 592.690 0.140 592.970 1516.130 ;
      RECT 594.930 0.140 595.210 1516.130 ;
      RECT 597.170 0.140 597.450 1516.130 ;
      RECT 599.410 0.140 599.690 1516.130 ;
      RECT 601.650 0.140 601.930 1516.130 ;
      RECT 603.890 0.140 604.170 1516.130 ;
      RECT 606.130 0.140 606.410 1516.130 ;
      RECT 608.370 0.140 608.650 1516.130 ;
      RECT 610.610 0.140 610.890 1516.130 ;
      RECT 612.850 0.140 613.130 1516.130 ;
      RECT 615.090 0.140 615.370 1516.130 ;
      RECT 617.330 0.140 617.610 1516.130 ;
      RECT 619.570 0.140 619.850 1516.130 ;
      RECT 621.810 0.140 622.090 1516.130 ;
      RECT 624.050 0.140 624.330 1516.130 ;
      RECT 626.290 0.140 626.570 1516.130 ;
      RECT 628.530 0.140 628.810 1516.130 ;
      RECT 630.770 0.140 631.050 1516.130 ;
      RECT 633.010 0.140 633.290 1516.130 ;
      RECT 635.250 0.140 635.530 1516.130 ;
      RECT 637.490 0.140 637.770 1516.130 ;
      RECT 639.730 0.140 640.010 1516.130 ;
      RECT 641.970 0.140 642.250 1516.130 ;
      RECT 644.210 0.140 644.490 1516.130 ;
      RECT 646.450 0.140 646.730 1516.130 ;
      RECT 648.690 0.140 648.970 1516.130 ;
      RECT 650.930 0.140 651.210 1516.130 ;
      RECT 653.170 0.140 653.450 1516.130 ;
      RECT 655.410 0.140 655.690 1516.130 ;
      RECT 657.650 0.140 657.930 1516.130 ;
      RECT 659.890 0.140 660.170 1516.130 ;
      RECT 662.130 0.140 662.410 1516.130 ;
      RECT 664.370 0.140 664.650 1516.130 ;
      RECT 666.610 0.140 666.890 1516.130 ;
      RECT 668.850 0.140 669.130 1516.130 ;
      RECT 671.090 0.140 671.370 1516.130 ;
      RECT 673.330 0.140 673.610 1516.130 ;
      RECT 675.570 0.140 675.850 1516.130 ;
      RECT 677.810 0.140 678.090 1516.130 ;
      RECT 680.050 0.140 680.330 1516.130 ;
      RECT 682.290 0.140 682.570 1516.130 ;
      RECT 684.530 0.140 684.810 1516.130 ;
      RECT 686.770 0.140 687.050 1516.130 ;
      RECT 689.010 0.140 689.290 1516.130 ;
      RECT 691.250 0.140 691.530 1516.130 ;
      RECT 693.490 0.140 693.770 1516.130 ;
      RECT 695.730 0.140 696.010 1516.130 ;
      RECT 697.970 0.140 698.250 1516.130 ;
      RECT 700.210 0.140 700.490 1516.130 ;
      RECT 702.450 0.140 702.730 1516.130 ;
      RECT 704.690 0.140 704.970 1516.130 ;
      RECT 706.930 0.140 707.210 1516.130 ;
      RECT 709.170 0.140 709.450 1516.130 ;
      RECT 711.410 0.140 711.690 1516.130 ;
      RECT 713.650 0.140 713.930 1516.130 ;
      RECT 715.890 0.140 716.170 1516.130 ;
      RECT 718.130 0.140 718.410 1516.130 ;
      RECT 720.370 0.140 720.650 1516.130 ;
      RECT 722.610 0.140 722.890 1516.130 ;
      RECT 724.850 0.140 725.130 1516.130 ;
      RECT 727.090 0.140 727.370 1516.130 ;
      RECT 729.330 0.140 729.610 1516.130 ;
      RECT 731.570 0.140 731.850 1516.130 ;
      RECT 733.810 0.140 734.090 1516.130 ;
      RECT 736.050 0.140 736.330 1516.130 ;
      RECT 738.290 0.140 738.570 1516.130 ;
      RECT 740.530 0.140 740.810 1516.130 ;
      RECT 742.770 0.140 743.050 1516.130 ;
      RECT 745.010 0.140 745.290 1516.130 ;
      RECT 747.250 0.140 747.530 1516.130 ;
      RECT 749.490 0.140 749.770 1516.130 ;
      RECT 751.730 0.140 752.010 1516.130 ;
      RECT 753.970 0.140 754.250 1516.130 ;
      RECT 756.210 0.140 756.490 1516.130 ;
      RECT 758.450 0.140 758.730 1516.130 ;
      RECT 760.690 0.140 760.970 1516.130 ;
      RECT 762.930 0.140 763.210 1516.130 ;
      RECT 765.170 0.140 765.450 1516.130 ;
      RECT 767.410 0.140 767.690 1516.130 ;
      RECT 769.650 0.140 769.930 1516.130 ;
      RECT 771.890 0.140 772.170 1516.130 ;
      RECT 774.130 0.140 774.410 1516.130 ;
      RECT 776.370 0.140 776.650 1516.130 ;
      RECT 778.610 0.140 778.890 1516.130 ;
      RECT 780.850 0.140 781.130 1516.130 ;
      RECT 783.090 0.140 783.370 1516.130 ;
      RECT 785.330 0.140 785.610 1516.130 ;
      RECT 787.570 0.140 787.850 1516.130 ;
      RECT 789.810 0.140 790.090 1516.130 ;
      RECT 792.050 0.140 792.330 1516.130 ;
      RECT 794.290 0.140 794.570 1516.130 ;
      RECT 796.530 0.140 796.810 1516.130 ;
      RECT 798.770 0.140 799.050 1516.130 ;
      RECT 801.010 0.140 801.290 1516.130 ;
      RECT 803.250 0.140 803.530 1516.130 ;
      RECT 805.490 0.140 805.770 1516.130 ;
      RECT 807.730 0.140 808.010 1516.130 ;
      RECT 809.970 0.140 810.250 1516.130 ;
      RECT 812.210 0.140 812.490 1516.130 ;
      RECT 814.450 0.140 814.730 1516.130 ;
      RECT 816.690 0.140 816.970 1516.130 ;
      RECT 818.930 0.140 819.210 1516.130 ;
      RECT 821.170 0.140 821.450 1516.130 ;
      RECT 823.410 0.140 823.690 1516.130 ;
      RECT 825.650 0.140 825.930 1516.130 ;
      RECT 827.890 0.140 828.170 1516.130 ;
      RECT 830.130 0.140 830.410 1516.130 ;
      RECT 832.370 0.140 832.650 1516.130 ;
      RECT 834.610 0.140 834.890 1516.130 ;
      RECT 836.850 0.140 837.130 1516.130 ;
      RECT 839.090 0.140 839.370 1516.130 ;
      RECT 841.330 0.140 841.610 1516.130 ;
      RECT 843.570 0.140 843.850 1516.130 ;
      RECT 845.810 0.140 846.090 1516.130 ;
      RECT 848.050 0.140 848.330 1516.130 ;
      RECT 850.290 0.140 850.570 1516.130 ;
      RECT 852.530 0.140 852.810 1516.130 ;
      RECT 854.770 0.140 855.050 1516.130 ;
      RECT 857.010 0.140 857.290 1516.130 ;
      RECT 859.250 0.140 859.530 1516.130 ;
      RECT 861.490 0.140 861.770 1516.130 ;
      RECT 863.730 0.140 864.010 1516.130 ;
      RECT 865.970 0.140 866.250 1516.130 ;
      RECT 868.210 0.140 868.490 1516.130 ;
      RECT 870.450 0.140 870.730 1516.130 ;
      RECT 872.690 0.140 872.970 1516.130 ;
      RECT 874.930 0.140 875.210 1516.130 ;
      RECT 877.170 0.140 877.450 1516.130 ;
      RECT 879.410 0.140 879.690 1516.130 ;
      RECT 881.650 0.140 881.930 1516.130 ;
      RECT 883.890 0.140 884.170 1516.130 ;
      RECT 886.130 0.140 886.410 1516.130 ;
      RECT 888.370 0.140 888.650 1516.130 ;
      RECT 890.610 0.140 890.890 1516.130 ;
      RECT 892.850 0.140 893.130 1516.130 ;
      RECT 895.090 0.140 895.370 1516.130 ;
      RECT 897.330 0.140 897.610 1516.130 ;
      RECT 899.570 0.140 899.850 1516.130 ;
      RECT 901.810 0.140 902.090 1516.130 ;
      RECT 904.050 0.140 904.330 1516.130 ;
      RECT 906.290 0.140 906.570 1516.130 ;
      RECT 908.530 0.140 908.810 1516.130 ;
      RECT 910.770 0.140 911.050 1516.130 ;
      RECT 913.010 0.140 913.290 1516.130 ;
      RECT 915.250 0.140 915.530 1516.130 ;
      RECT 917.490 0.140 917.770 1516.130 ;
      RECT 919.730 0.140 920.010 1516.130 ;
      RECT 921.970 0.140 922.250 1516.130 ;
      RECT 924.210 0.140 924.490 1516.130 ;
      RECT 926.450 0.140 926.730 1516.130 ;
      RECT 928.690 0.140 928.970 1516.130 ;
      RECT 930.930 0.140 931.210 1516.130 ;
      RECT 933.170 0.140 933.450 1516.130 ;
      RECT 935.410 0.140 935.690 1516.130 ;
      RECT 937.650 0.140 937.930 1516.130 ;
      RECT 939.890 0.140 940.170 1516.130 ;
      RECT 942.130 0.140 942.410 1516.130 ;
      RECT 944.370 0.140 944.650 1516.130 ;
      RECT 946.610 0.140 946.890 1516.130 ;
      RECT 948.850 0.140 949.130 1516.130 ;
      RECT 951.090 0.140 951.370 1516.130 ;
      RECT 953.330 0.140 953.610 1516.130 ;
      RECT 955.570 0.140 955.850 1516.130 ;
      RECT 957.810 0.140 958.090 1516.130 ;
      RECT 960.050 0.140 960.330 1516.130 ;
      RECT 962.290 0.140 962.570 1516.130 ;
      RECT 964.530 0.140 964.810 1516.130 ;
      RECT 966.770 0.140 967.050 1516.130 ;
      RECT 969.010 0.140 969.290 1516.130 ;
      RECT 971.250 0.140 971.530 1516.130 ;
      RECT 973.490 0.140 973.770 1516.130 ;
      RECT 975.730 0.140 976.010 1516.130 ;
      RECT 977.970 0.140 978.250 1516.130 ;
      RECT 980.210 0.140 980.490 1516.130 ;
      RECT 982.450 0.140 982.730 1516.130 ;
      RECT 984.690 0.140 984.970 1516.130 ;
      RECT 986.930 0.140 987.210 1516.130 ;
      RECT 989.170 0.140 989.450 1516.130 ;
      RECT 991.410 0.140 991.690 1516.130 ;
      RECT 993.650 0.140 993.930 1516.130 ;
      RECT 995.890 0.140 996.170 1516.130 ;
      RECT 998.130 0.140 998.410 1516.130 ;
      RECT 1000.370 0.140 1000.650 1516.130 ;
      RECT 1002.610 0.140 1002.890 1516.130 ;
      RECT 1004.850 0.140 1005.130 1516.130 ;
      RECT 1007.090 0.140 1007.370 1516.130 ;
      RECT 1009.330 0.140 1009.610 1516.130 ;
      RECT 1011.570 0.140 1011.850 1516.130 ;
      RECT 1013.810 0.140 1014.090 1516.130 ;
      RECT 1016.050 0.140 1016.330 1516.130 ;
      RECT 1018.290 0.140 1018.570 1516.130 ;
      RECT 1020.530 0.140 1020.810 1516.130 ;
      RECT 1022.770 0.140 1023.050 1516.130 ;
      RECT 1025.010 0.140 1025.290 1516.130 ;
      RECT 1027.250 0.140 1027.530 1516.130 ;
      RECT 1029.490 0.140 1029.770 1516.130 ;
      RECT 1031.730 0.140 1032.010 1516.130 ;
      RECT 1033.970 0.140 1034.250 1516.130 ;
      RECT 1036.210 0.140 1036.490 1516.130 ;
      RECT 1038.450 0.140 1038.730 1516.130 ;
      RECT 1040.690 0.140 1040.970 1516.130 ;
      RECT 1042.930 0.140 1043.210 1516.130 ;
      RECT 1045.170 0.140 1045.450 1516.130 ;
      RECT 1047.410 0.140 1047.690 1516.130 ;
      RECT 1049.650 0.140 1049.930 1516.130 ;
      RECT 1051.890 0.140 1052.170 1516.130 ;
      RECT 1054.130 0.140 1054.410 1516.130 ;
      RECT 1056.370 0.140 1056.650 1516.130 ;
      RECT 1058.610 0.140 1058.890 1516.130 ;
      RECT 1060.850 0.140 1061.130 1516.130 ;
      RECT 1063.090 0.140 1063.370 1516.130 ;
      RECT 1065.330 0.140 1065.610 1516.130 ;
      RECT 1067.570 0.140 1067.850 1516.130 ;
      RECT 1069.810 0.140 1070.090 1516.130 ;
      RECT 1072.050 0.140 1072.330 1516.130 ;
      RECT 1074.290 0.140 1074.570 1516.130 ;
      RECT 1076.530 0.140 1076.810 1516.130 ;
      RECT 1078.770 0.140 1079.050 1516.130 ;
      RECT 1081.010 0.140 1081.290 1516.130 ;
      RECT 1083.250 0.140 1083.530 1516.130 ;
      RECT 1085.490 0.140 1085.770 1516.130 ;
      RECT 1087.730 0.140 1088.010 1516.130 ;
      RECT 1089.970 0.140 1090.250 1516.130 ;
      RECT 1092.210 0.140 1092.490 1516.130 ;
      RECT 1094.450 0.140 1094.730 1516.130 ;
      RECT 1096.690 0.140 1096.970 1516.130 ;
      RECT 1098.930 0.140 1099.210 1516.130 ;
      RECT 1101.170 0.140 1101.450 1516.130 ;
      RECT 1103.410 0.140 1103.690 1516.130 ;
      RECT 1105.650 0.140 1105.930 1516.130 ;
      RECT 1107.890 0.140 1108.170 1516.130 ;
      RECT 1110.130 0.140 1110.410 1516.130 ;
      RECT 1112.370 0.140 1112.650 1516.130 ;
      RECT 1114.610 0.140 1114.890 1516.130 ;
      RECT 1116.850 0.140 1117.130 1516.130 ;
      RECT 1119.090 0.140 1119.370 1516.130 ;
      RECT 1121.330 0.140 1121.610 1516.130 ;
      RECT 1123.570 0.140 1123.850 1516.130 ;
      RECT 1125.810 0.140 1126.090 1516.130 ;
      RECT 1128.050 0.140 1128.330 1516.130 ;
      RECT 1130.290 0.140 1130.570 1516.130 ;
      RECT 1132.530 0.140 1132.810 1516.130 ;
      RECT 1134.770 0.140 1135.050 1516.130 ;
      RECT 1137.010 0.140 1137.290 1516.130 ;
      RECT 1139.250 0.140 1139.530 1516.130 ;
      RECT 1141.490 0.140 1141.770 1516.130 ;
      RECT 1143.730 0.140 1144.010 1516.130 ;
      RECT 1145.970 0.140 1146.250 1516.130 ;
      RECT 1148.210 0.140 1148.490 1516.130 ;
      RECT 1150.450 0.140 1150.730 1516.130 ;
      RECT 1152.690 0.140 1152.970 1516.130 ;
      RECT 1154.930 0.140 1155.210 1516.130 ;
      RECT 1157.170 0.140 1157.450 1516.130 ;
      RECT 1159.410 0.140 1159.690 1516.130 ;
      RECT 1161.650 0.140 1161.930 1516.130 ;
      RECT 1163.890 0.140 1164.170 1516.130 ;
      RECT 1166.130 0.140 1166.410 1516.130 ;
      RECT 1168.370 0.140 1168.650 1516.130 ;
      RECT 1170.610 0.140 1170.890 1516.130 ;
      RECT 1172.850 0.140 1173.130 1516.130 ;
      RECT 1175.090 0.140 1175.370 1516.130 ;
      RECT 1177.330 0.140 1177.610 1516.130 ;
      RECT 1179.570 0.140 1179.850 1516.130 ;
      RECT 1181.810 0.140 1182.090 1516.130 ;
      RECT 1184.050 0.140 1184.330 1516.130 ;
      RECT 1186.290 0.140 1186.570 1516.130 ;
      RECT 1188.530 0.140 1188.810 1516.130 ;
      RECT 1190.770 0.140 1191.050 1516.130 ;
      RECT 1193.010 0.140 1193.290 1516.130 ;
      RECT 1195.250 0.140 1195.530 1516.130 ;
      RECT 1197.490 0.140 1197.770 1516.130 ;
      RECT 1199.730 0.140 1200.010 1516.130 ;
      RECT 1201.970 0.140 1202.250 1516.130 ;
      RECT 1204.210 0.140 1204.490 1516.130 ;
      RECT 1206.450 0.140 1206.730 1516.130 ;
      RECT 1208.690 0.140 1208.970 1516.130 ;
      RECT 1210.930 0.140 1211.210 1516.130 ;
      RECT 1213.170 0.140 1213.450 1516.130 ;
      RECT 1215.410 0.140 1215.690 1516.130 ;
      RECT 1217.650 0.140 1217.930 1516.130 ;
      RECT 1219.890 0.140 1220.170 1516.130 ;
      RECT 1222.130 0.140 1222.410 1516.130 ;
      RECT 1224.370 0.140 1224.650 1516.130 ;
      RECT 1226.610 0.140 1226.890 1516.130 ;
      RECT 1228.850 0.140 1229.130 1516.130 ;
      RECT 1231.090 0.140 1231.370 1516.130 ;
      RECT 1233.330 0.140 1233.610 1516.130 ;
      RECT 1235.570 0.140 1235.850 1516.130 ;
      RECT 1237.810 0.140 1238.090 1516.130 ;
      RECT 1240.050 0.140 1240.330 1516.130 ;
      RECT 1242.290 0.140 1242.570 1516.130 ;
      RECT 1244.530 0.140 1244.810 1516.130 ;
      RECT 1246.770 0.140 1247.050 1516.130 ;
      RECT 1249.010 0.140 1249.290 1516.130 ;
      RECT 1251.250 0.140 1251.530 1516.130 ;
      RECT 1253.490 0.140 1253.770 1516.130 ;
      RECT 1255.730 0.140 1256.010 1516.130 ;
      RECT 1257.970 0.140 1258.250 1516.130 ;
      RECT 1260.210 0.140 1260.490 1516.130 ;
      RECT 1262.450 0.140 1262.730 1516.130 ;
      RECT 1264.690 0.140 1264.970 1516.130 ;
      RECT 1266.930 0.140 1267.210 1516.130 ;
      RECT 1269.170 0.140 1269.450 1516.130 ;
      RECT 1271.410 0.140 1271.690 1516.130 ;
      RECT 1273.650 0.140 1273.930 1516.130 ;
      RECT 1275.890 0.140 1276.170 1516.130 ;
      RECT 1278.130 0.140 1278.410 1516.130 ;
      RECT 1280.370 0.140 1280.650 1516.130 ;
      RECT 1282.610 0.140 1282.890 1516.130 ;
      RECT 1284.850 0.140 1285.130 1516.130 ;
      RECT 1287.090 0.140 1287.370 1516.130 ;
      RECT 1289.330 0.140 1289.610 1516.130 ;
      RECT 1291.570 0.140 1291.850 1516.130 ;
      RECT 1293.810 0.140 1294.090 1516.130 ;
      RECT 1296.050 0.140 1296.330 1516.130 ;
      RECT 1298.290 0.140 1298.570 1516.130 ;
      RECT 1300.530 0.140 1300.810 1516.130 ;
      RECT 1302.770 0.140 1303.050 1516.130 ;
      RECT 1305.010 0.140 1305.290 1516.130 ;
      RECT 1307.250 0.140 1307.530 1516.130 ;
      RECT 1309.490 0.140 1309.770 1516.130 ;
      RECT 1311.730 0.140 1312.010 1516.130 ;
      RECT 1313.970 0.140 1314.250 1516.130 ;
      RECT 1316.210 0.140 1316.490 1516.130 ;
      RECT 1318.450 0.140 1318.730 1516.130 ;
      RECT 1320.690 0.140 1320.970 1516.130 ;
      RECT 1322.930 0.140 1323.210 1516.130 ;
      RECT 1325.170 0.140 1325.450 1516.130 ;
      RECT 1327.410 0.140 1327.690 1516.130 ;
      RECT 1329.650 0.140 1329.930 1516.130 ;
      RECT 1331.890 0.140 1332.170 1516.130 ;
      RECT 1334.130 0.140 1334.410 1516.130 ;
      RECT 1336.370 0.140 1336.650 1516.130 ;
      RECT 1338.610 0.140 1338.890 1516.130 ;
      RECT 1340.850 0.140 1341.130 1516.130 ;
      RECT 1343.090 0.140 1343.370 1516.130 ;
      RECT 1345.330 0.140 1345.610 1516.130 ;
      RECT 1347.570 0.140 1347.850 1516.130 ;
      RECT 1349.810 0.140 1350.090 1516.130 ;
      RECT 1352.050 0.140 1352.330 1516.130 ;
      RECT 1354.290 0.140 1354.570 1516.130 ;
      RECT 1356.530 0.140 1356.810 1516.130 ;
      RECT 1358.770 0.140 1359.050 1516.130 ;
      RECT 1361.010 0.140 1361.290 1516.130 ;
      RECT 1363.250 0.140 1363.530 1516.130 ;
      RECT 1365.490 0.140 1365.770 1516.130 ;
      RECT 1367.730 0.140 1368.010 1516.130 ;
      RECT 1369.970 0.140 1370.250 1516.130 ;
      RECT 1372.210 0.140 1372.490 1516.130 ;
      RECT 1374.450 0.140 1374.730 1516.130 ;
      RECT 1376.690 0.140 1376.970 1516.130 ;
      RECT 1378.930 0.140 1379.210 1516.130 ;
      RECT 1381.170 0.140 1381.450 1516.130 ;
      RECT 1383.410 0.140 1383.690 1516.130 ;
      RECT 1385.650 0.140 1385.930 1516.130 ;
      RECT 1387.890 0.140 1388.170 1516.130 ;
      RECT 1390.130 0.140 1390.410 1516.130 ;
      RECT 1392.370 0.140 1392.650 1516.130 ;
      RECT 1394.610 0.140 1394.890 1516.130 ;
      RECT 1396.850 0.140 1397.130 1516.130 ;
      RECT 1399.090 0.140 1399.370 1516.130 ;
      RECT 1401.330 0.140 1401.610 1516.130 ;
      RECT 1403.570 0.140 1403.850 1516.130 ;
      RECT 1405.810 0.140 1406.090 1516.130 ;
      RECT 1408.050 0.140 1408.330 1516.130 ;
      RECT 1410.290 0.140 1410.570 1516.130 ;
      RECT 1412.530 0.140 1412.810 1516.130 ;
      RECT 1414.770 0.140 1415.050 1516.130 ;
      RECT 1417.010 0.140 1417.290 1516.130 ;
      RECT 1419.250 0.140 1419.530 1516.130 ;
      RECT 1421.490 0.140 1421.770 1516.130 ;
      RECT 1423.730 0.140 1424.010 1516.130 ;
      RECT 1425.970 0.140 1426.250 1516.130 ;
      RECT 1428.210 0.140 1428.490 1516.130 ;
      RECT 1430.450 0.140 1430.730 1516.130 ;
      RECT 1432.690 0.140 1432.970 1516.130 ;
      RECT 1434.930 0.140 1435.210 1516.130 ;
      RECT 1437.170 0.140 1437.450 1516.130 ;
      RECT 1439.410 0.140 1439.690 1516.130 ;
      RECT 1441.650 0.140 1441.930 1516.130 ;
      RECT 1443.890 0.140 1444.170 1516.130 ;
      RECT 1446.130 0.140 1446.410 1516.130 ;
      RECT 1448.370 0.140 1448.650 1516.130 ;
      RECT 1450.610 0.140 1450.890 1516.130 ;
      RECT 1452.850 0.140 1453.130 1516.130 ;
      RECT 1455.090 0.140 1455.370 1516.130 ;
      RECT 1457.330 0.140 1457.610 1516.130 ;
      RECT 1459.570 0.140 1459.850 1516.130 ;
      RECT 1461.810 0.140 1462.090 1516.130 ;
      RECT 1464.050 0.140 1464.330 1516.130 ;
      RECT 1466.290 0.140 1466.570 1516.130 ;
      RECT 1468.530 0.140 1468.810 1516.130 ;
      RECT 1470.770 0.140 1471.050 1516.130 ;
      RECT 1473.010 0.140 1473.290 1516.130 ;
      RECT 1475.250 0.140 1475.530 1516.130 ;
      RECT 1477.490 0.140 1477.770 1516.130 ;
      RECT 1479.730 0.140 1480.010 1516.130 ;
      RECT 1481.970 0.140 1482.250 1516.130 ;
      RECT 1484.210 0.140 1484.490 1516.130 ;
      RECT 1486.450 0.140 1486.730 1516.130 ;
      RECT 1488.690 0.140 1488.970 1516.130 ;
      RECT 1490.930 0.140 1491.210 1516.130 ;
      RECT 1493.170 0.140 1493.450 1516.130 ;
      RECT 1495.410 0.140 1495.690 1516.130 ;
      RECT 1497.650 0.140 1497.930 1516.130 ;
      RECT 1499.890 0.140 1500.170 1516.130 ;
      RECT 1502.130 0.140 1502.410 1516.130 ;
      RECT 1504.370 0.140 1504.650 1516.130 ;
      RECT 1506.610 0.140 1506.890 1516.130 ;
      RECT 1508.850 0.140 1509.130 1516.130 ;
      RECT 1511.090 0.140 1511.370 1516.130 ;
      RECT 1513.330 0.140 1513.610 1516.130 ;
      RECT 1515.570 0.140 1515.850 1516.130 ;
      RECT 1517.810 0.140 1518.090 1516.130 ;
      RECT 1520.050 0.140 1520.330 1516.130 ;
      RECT 1522.290 0.140 1522.570 1516.130 ;
      RECT 1524.530 0.140 1524.810 1516.130 ;
      RECT 1526.770 0.140 1527.050 1516.130 ;
      RECT 1529.010 0.140 1529.290 1516.130 ;
      RECT 1531.250 0.140 1531.530 1516.130 ;
      RECT 1533.490 0.140 1533.770 1516.130 ;
      RECT 1535.730 0.140 1536.010 1516.130 ;
      RECT 1537.970 0.140 1538.250 1516.130 ;
      RECT 1540.210 0.140 1540.490 1516.130 ;
      RECT 1542.450 0.140 1542.730 1516.130 ;
      RECT 1544.690 0.140 1544.970 1516.130 ;
      RECT 1546.930 0.140 1547.210 1516.130 ;
      RECT 1549.170 0.140 1549.450 1516.130 ;
      RECT 1551.410 0.140 1551.690 1516.130 ;
      RECT 1553.650 0.140 1553.930 1516.130 ;
      RECT 1555.890 0.140 1556.170 1516.130 ;
      RECT 1558.130 0.140 1558.410 1516.130 ;
      RECT 1560.370 0.140 1560.650 1516.130 ;
      RECT 1562.610 0.140 1562.890 1516.130 ;
      RECT 1564.850 0.140 1565.130 1516.130 ;
      RECT 1567.090 0.140 1567.370 1516.130 ;
      RECT 1569.330 0.140 1569.610 1516.130 ;
      RECT 1571.570 0.140 1571.850 1516.130 ;
      RECT 1573.810 0.140 1574.090 1516.130 ;
      RECT 1576.050 0.140 1576.330 1516.130 ;
      RECT 1578.290 0.140 1578.570 1516.130 ;
      RECT 1580.530 0.140 1580.810 1516.130 ;
      RECT 1582.770 0.140 1583.050 1516.130 ;
      RECT 1585.010 0.140 1585.290 1516.130 ;
      RECT 1587.250 0.140 1587.530 1516.130 ;
      RECT 1589.490 0.140 1589.770 1516.130 ;
      RECT 1591.730 0.140 1592.010 1516.130 ;
      RECT 1593.970 0.140 1594.250 1516.130 ;
      RECT 1596.210 0.140 1596.490 1516.130 ;
      RECT 1598.450 0.140 1598.730 1516.130 ;
      RECT 1600.690 0.140 1600.970 1516.130 ;
      RECT 1602.930 0.140 1603.210 1516.130 ;
      RECT 1605.170 0.140 1605.450 1516.130 ;
      RECT 1607.410 0.140 1607.690 1516.130 ;
      RECT 1609.650 0.140 1609.930 1516.130 ;
    END
  END VDD
  OBS
    LAYER metal1 ;
    RECT 0 0 1610.280 1516.270 ;
    LAYER metal2 ;
    RECT 0 0 1610.280 1516.270 ;
    LAYER metal3 ;
    RECT 0 0 1610.280 1516.270 ;
    LAYER metal4 ;
    RECT 0 0 1610.280 1516.270 ;
    LAYER OVERLAP ;
    RECT 0 0 1610.280 1516.270 ;
  END
END fakeram_512x2048_1r1w

END LIBRARY
